###############################################################
#  Generated by:      Cadence Innovus 20.13-s083_1
#  OS:                Linux x86_64(Host ID iron-502-27)
#  Generated on:      Fri Jun 17 14:07:25 2022
#  Design:            user_proj_example
#  Command:           write_lef_abstract -specifyTopLayer 5 -PGPinLayers {5 6} -extractBlockObs -stripePin results/user_proj_example.lef
###############################################################

VERSION 5.8 ;

BUSBITCHARS "[]" ;
DIVIDERCHAR "/" ;

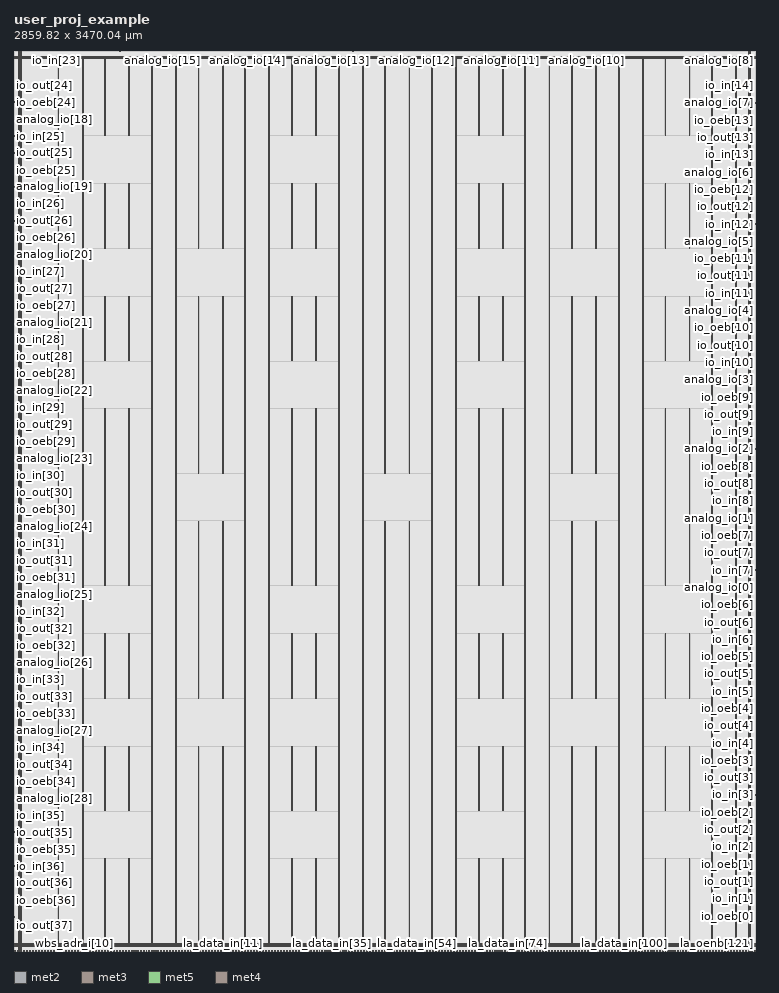
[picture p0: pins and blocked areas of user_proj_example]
MACRO user_proj_example
  CLASS BLOCK ;
  SIZE 2859.820000 BY 3470.040000 ;
  FOREIGN user_proj_example 0.000000 0.000000 ;
  ORIGIN 0 0 ;
  SYMMETRY X Y R90 ;
  PIN wb_clk_i
    DIRECTION INPUT ;
    USE SIGNAL ;
    ANTENNAPARTIALMETALAREA 4.1174 LAYER met2  ;
    ANTENNAPARTIALMETALSIDEAREA 20.426 LAYER met2  ;
    ANTENNAPARTIALCUTAREA 0.04 LAYER via2  ;
    ANTENNAPARTIALMETALAREA 8.6748 LAYER met3  ;
    ANTENNAPARTIALMETALSIDEAREA 46.736 LAYER met3  ;
    ANTENNAMODEL OXIDE1 ;
    ANTENNAGATEAREA 0.576 LAYER met3  ;
    ANTENNAMAXAREACAR 16.2276 LAYER met3  ;
    ANTENNAMAXSIDEAREACAR 83.9896 LAYER met3  ;
    ANTENNAMAXCUTCAR 0.158681 LAYER via3  ;
    PORT
      LAYER met2 ;
        RECT 0.620000 0.000000 0.760000 0.485000 ;
    END
  END wb_clk_i
  PIN wb_rst_i
    DIRECTION INPUT ;
    USE SIGNAL ;
    ANTENNAPARTIALMETALAREA 5.373 LAYER met2  ;
    ANTENNAPARTIALMETALSIDEAREA 26.691 LAYER met2  ;
    ANTENNAPARTIALCUTAREA 0.04 LAYER via2  ;
    ANTENNAPARTIALMETALAREA 4.1208 LAYER met3  ;
    ANTENNAPARTIALMETALSIDEAREA 22.448 LAYER met3  ;
    ANTENNAMODEL OXIDE1 ;
    ANTENNAGATEAREA 4.411 LAYER met3  ;
    ANTENNAMAXAREACAR 28.0961 LAYER met3  ;
    ANTENNAMAXSIDEAREACAR 138.749 LAYER met3  ;
    ANTENNAMAXCUTCAR 0.307654 LAYER via3  ;
    PORT
      LAYER met2 ;
        RECT 6.140000 0.000000 6.280000 0.485000 ;
    END
  END wb_rst_i
  PIN wbs_stb_i
    DIRECTION INPUT ;
    USE SIGNAL ;
    ANTENNAPARTIALMETALAREA 4.0627 LAYER met2  ;
    ANTENNAPARTIALMETALSIDEAREA 20.2055 LAYER met2  ;
    ANTENNAMODEL OXIDE1 ;
    ANTENNAGATEAREA 0.126 LAYER met2  ;
    ANTENNAMAXAREACAR 44.8623 LAYER met2  ;
    ANTENNAMAXSIDEAREACAR 217.206 LAYER met2  ;
    ANTENNAMAXCUTCAR 0.407937 LAYER via2  ;
    PORT
      LAYER met2 ;
        RECT 23.620000 0.000000 23.760000 0.485000 ;
    END
  END wbs_stb_i
  PIN wbs_cyc_i
    DIRECTION INPUT ;
    USE SIGNAL ;
    ANTENNAPARTIALMETALAREA 4.2055 LAYER met2  ;
    ANTENNAPARTIALMETALSIDEAREA 20.9195 LAYER met2  ;
    ANTENNAMODEL OXIDE1 ;
    ANTENNAGATEAREA 0.126 LAYER met2  ;
    ANTENNAMAXAREACAR 52.6694 LAYER met2  ;
    ANTENNAMAXSIDEAREACAR 253.103 LAYER met2  ;
    ANTENNAMAXCUTCAR 0.407937 LAYER via2  ;
    PORT
      LAYER met2 ;
        RECT 17.640000 0.000000 17.780000 0.485000 ;
    END
  END wbs_cyc_i
  PIN wbs_we_i
    DIRECTION INPUT ;
    USE SIGNAL ;
    ANTENNAPARTIALMETALAREA 5.0655 LAYER met2  ;
    ANTENNAPARTIALMETALSIDEAREA 24.9935 LAYER met2  ;
    ANTENNAMODEL OXIDE1 ;
    ANTENNAGATEAREA 0.3735 LAYER met2  ;
    ANTENNAMAXAREACAR 17.5253 LAYER met2  ;
    ANTENNAMAXSIDEAREACAR 78.1749 LAYER met2  ;
    ANTENNAMAXCUTCAR 0.407937 LAYER via2  ;
    PORT
      LAYER met2 ;
        RECT 29.600000 0.000000 29.740000 0.485000 ;
    END
  END wbs_we_i
  PIN wbs_sel_i[3]
    DIRECTION INPUT ;
    USE SIGNAL ;
    PORT
      LAYER met2 ;
        RECT 122.060000 0.000000 122.200000 0.485000 ;
    END
  END wbs_sel_i[3]
  PIN wbs_sel_i[2]
    DIRECTION INPUT ;
    USE SIGNAL ;
    PORT
      LAYER met2 ;
        RECT 99.060000 0.000000 99.200000 0.485000 ;
    END
  END wbs_sel_i[2]
  PIN wbs_sel_i[1]
    DIRECTION INPUT ;
    USE SIGNAL ;
    PORT
      LAYER met2 ;
        RECT 75.600000 0.000000 75.740000 0.485000 ;
    END
  END wbs_sel_i[1]
  PIN wbs_sel_i[0]
    DIRECTION INPUT ;
    USE SIGNAL ;
    PORT
      LAYER met2 ;
        RECT 52.600000 0.000000 52.740000 0.485000 ;
    END
  END wbs_sel_i[0]
  PIN wbs_dat_i[31]
    DIRECTION INPUT ;
    USE SIGNAL ;
    PORT
      LAYER met2 ;
        RECT 603.680000 0.000000 603.820000 0.485000 ;
    END
  END wbs_dat_i[31]
  PIN wbs_dat_i[30]
    DIRECTION INPUT ;
    USE SIGNAL ;
    PORT
      LAYER met2 ;
        RECT 586.200000 0.000000 586.340000 0.485000 ;
    END
  END wbs_dat_i[30]
  PIN wbs_dat_i[29]
    DIRECTION INPUT ;
    USE SIGNAL ;
    PORT
      LAYER met2 ;
        RECT 568.720000 0.000000 568.860000 0.485000 ;
    END
  END wbs_dat_i[29]
  PIN wbs_dat_i[28]
    DIRECTION INPUT ;
    USE SIGNAL ;
    PORT
      LAYER met2 ;
        RECT 551.240000 0.000000 551.380000 0.485000 ;
    END
  END wbs_dat_i[28]
  PIN wbs_dat_i[27]
    DIRECTION INPUT ;
    USE SIGNAL ;
    PORT
      LAYER met2 ;
        RECT 533.760000 0.000000 533.900000 0.485000 ;
    END
  END wbs_dat_i[27]
  PIN wbs_dat_i[26]
    DIRECTION INPUT ;
    USE SIGNAL ;
    PORT
      LAYER met2 ;
        RECT 516.740000 0.000000 516.880000 0.485000 ;
    END
  END wbs_dat_i[26]
  PIN wbs_dat_i[25]
    DIRECTION INPUT ;
    USE SIGNAL ;
    PORT
      LAYER met2 ;
        RECT 499.260000 0.000000 499.400000 0.485000 ;
    END
  END wbs_dat_i[25]
  PIN wbs_dat_i[24]
    DIRECTION INPUT ;
    USE SIGNAL ;
    PORT
      LAYER met2 ;
        RECT 481.780000 0.000000 481.920000 0.485000 ;
    END
  END wbs_dat_i[24]
  PIN wbs_dat_i[23]
    DIRECTION INPUT ;
    USE SIGNAL ;
    ANTENNAPARTIALMETALAREA 6.0883 LAYER met2  ;
    ANTENNAPARTIALMETALSIDEAREA 30.2155 LAYER met2  ;
    ANTENNAMODEL OXIDE1 ;
    ANTENNAGATEAREA 0.126 LAYER met2  ;
    ANTENNAMAXAREACAR 50.3571 LAYER met2  ;
    ANTENNAMAXSIDEAREACAR 245.865 LAYER met2  ;
    ANTENNAMAXCUTCAR 0.407937 LAYER via2  ;
    PORT
      LAYER met2 ;
        RECT 464.300000 0.000000 464.440000 0.485000 ;
    END
  END wbs_dat_i[23]
  PIN wbs_dat_i[22]
    DIRECTION INPUT ;
    USE SIGNAL ;
    ANTENNAPARTIALMETALAREA 6.3475 LAYER met2  ;
    ANTENNAPARTIALMETALSIDEAREA 31.6295 LAYER met2  ;
    ANTENNAMODEL OXIDE1 ;
    ANTENNAGATEAREA 0.126 LAYER met2  ;
    ANTENNAMAXAREACAR 67.3623 LAYER met2  ;
    ANTENNAMAXSIDEAREACAR 327.397 LAYER met2  ;
    ANTENNAMAXCUTCAR 0.407937 LAYER via2  ;
    PORT
      LAYER met2 ;
        RECT 446.820000 0.000000 446.960000 0.485000 ;
    END
  END wbs_dat_i[22]
  PIN wbs_dat_i[21]
    DIRECTION INPUT ;
    USE SIGNAL ;
    ANTENNAPARTIALMETALAREA 5.5859 LAYER met2  ;
    ANTENNAPARTIALMETALSIDEAREA 27.8215 LAYER met2  ;
    ANTENNAMODEL OXIDE1 ;
    ANTENNAGATEAREA 0.126 LAYER met2  ;
    ANTENNAMAXAREACAR 59.7845 LAYER met2  ;
    ANTENNAMAXSIDEAREACAR 289.508 LAYER met2  ;
    ANTENNAMAXCUTCAR 0.407937 LAYER via2  ;
    PORT
      LAYER met2 ;
        RECT 429.800000 0.000000 429.940000 0.485000 ;
    END
  END wbs_dat_i[21]
  PIN wbs_dat_i[20]
    DIRECTION INPUT ;
    USE SIGNAL ;
    ANTENNAPARTIALMETALAREA 6.2383 LAYER met2  ;
    ANTENNAPARTIALMETALSIDEAREA 31.0835 LAYER met2  ;
    ANTENNAMODEL OXIDE1 ;
    ANTENNAGATEAREA 0.126 LAYER met2  ;
    ANTENNAMAXAREACAR 51.5476 LAYER met2  ;
    ANTENNAMAXSIDEAREACAR 252.754 LAYER met2  ;
    ANTENNAMAXCUTCAR 0.407937 LAYER via2  ;
    PORT
      LAYER met2 ;
        RECT 412.320000 0.000000 412.460000 0.485000 ;
    END
  END wbs_dat_i[20]
  PIN wbs_dat_i[19]
    DIRECTION INPUT ;
    USE SIGNAL ;
    ANTENNAPARTIALMETALAREA 5.5859 LAYER met2  ;
    ANTENNAPARTIALMETALSIDEAREA 27.8215 LAYER met2  ;
    ANTENNAMODEL OXIDE1 ;
    ANTENNAGATEAREA 0.126 LAYER met2  ;
    ANTENNAMAXAREACAR 48.8067 LAYER met2  ;
    ANTENNAMAXSIDEAREACAR 234.619 LAYER met2  ;
    ANTENNAMAXCUTCAR 0.407937 LAYER via2  ;
    PORT
      LAYER met2 ;
        RECT 394.840000 0.000000 394.980000 0.485000 ;
    END
  END wbs_dat_i[19]
  PIN wbs_dat_i[18]
    DIRECTION INPUT ;
    USE SIGNAL ;
    ANTENNAPARTIALMETALAREA 6.1095 LAYER met2  ;
    ANTENNAPARTIALMETALSIDEAREA 30.4395 LAYER met2  ;
    ANTENNAMODEL OXIDE1 ;
    ANTENNAGATEAREA 0.126 LAYER met2  ;
    ANTENNAMAXAREACAR 53.477 LAYER met2  ;
    ANTENNAMAXSIDEAREACAR 261.865 LAYER met2  ;
    ANTENNAMAXCUTCAR 0.407937 LAYER via2  ;
    PORT
      LAYER met2 ;
        RECT 377.360000 0.000000 377.500000 0.485000 ;
    END
  END wbs_dat_i[18]
  PIN wbs_dat_i[17]
    DIRECTION INPUT ;
    USE SIGNAL ;
    ANTENNAPARTIALMETALAREA 5.3339 LAYER met2  ;
    ANTENNAPARTIALMETALSIDEAREA 26.5615 LAYER met2  ;
    ANTENNAMODEL OXIDE1 ;
    ANTENNAGATEAREA 0.126 LAYER met2  ;
    ANTENNAMAXAREACAR 52.8353 LAYER met2  ;
    ANTENNAMAXSIDEAREACAR 251.254 LAYER met2  ;
    ANTENNAMAXCUTCAR 0.407937 LAYER via2  ;
    PORT
      LAYER met2 ;
        RECT 359.880000 0.000000 360.020000 0.485000 ;
    END
  END wbs_dat_i[17]
  PIN wbs_dat_i[16]
    DIRECTION INPUT ;
    USE SIGNAL ;
    ANTENNAPARTIALMETALAREA 5.4599 LAYER met2  ;
    ANTENNAPARTIALMETALSIDEAREA 27.1915 LAYER met2  ;
    ANTENNAMODEL OXIDE1 ;
    ANTENNAGATEAREA 0.126 LAYER met2  ;
    ANTENNAMAXAREACAR 45.3698 LAYER met2  ;
    ANTENNAMAXSIDEAREACAR 221.865 LAYER met2  ;
    ANTENNAMAXCUTCAR 0.407937 LAYER via2  ;
    PORT
      LAYER met2 ;
        RECT 342.400000 0.000000 342.540000 0.485000 ;
    END
  END wbs_dat_i[16]
  PIN wbs_dat_i[15]
    DIRECTION INPUT ;
    USE SIGNAL ;
    ANTENNAPARTIALMETALAREA 6.4215 LAYER met2  ;
    ANTENNAPARTIALMETALSIDEAREA 31.8815 LAYER met2  ;
    ANTENNAMODEL OXIDE1 ;
    ANTENNAGATEAREA 0.2475 LAYER met2  ;
    ANTENNAMAXAREACAR 28.7937 LAYER met2  ;
    ANTENNAMAXSIDEAREACAR 138.541 LAYER met2  ;
    ANTENNAMAXCUTCAR 0.207677 LAYER via2  ;
    PORT
      LAYER met2 ;
        RECT 325.380000 0.000000 325.520000 0.485000 ;
    END
  END wbs_dat_i[15]
  PIN wbs_dat_i[14]
    DIRECTION INPUT ;
    USE SIGNAL ;
    ANTENNAPARTIALMETALAREA 4.5651 LAYER met2  ;
    ANTENNAPARTIALMETALSIDEAREA 22.5995 LAYER met2  ;
    ANTENNAMODEL OXIDE1 ;
    ANTENNAGATEAREA 0.2475 LAYER met2  ;
    ANTENNAMAXAREACAR 19.302 LAYER met2  ;
    ANTENNAMAXSIDEAREACAR 94.2182 LAYER met2  ;
    ANTENNAMAXCUTCAR 0.207677 LAYER via2  ;
    PORT
      LAYER met2 ;
        RECT 307.900000 0.000000 308.040000 0.485000 ;
    END
  END wbs_dat_i[14]
  PIN wbs_dat_i[13]
    DIRECTION INPUT ;
    USE SIGNAL ;
    ANTENNAPARTIALMETALAREA 5.7761 LAYER met2  ;
    ANTENNAPARTIALMETALSIDEAREA 28.6545 LAYER met2  ;
    ANTENNAMODEL OXIDE1 ;
    ANTENNAGATEAREA 0.2475 LAYER met2  ;
    ANTENNAMAXAREACAR 24.195 LAYER met2  ;
    ANTENNAMAXSIDEAREACAR 118.683 LAYER met2  ;
    ANTENNAMAXCUTCAR 0.207677 LAYER via2  ;
    PORT
      LAYER met2 ;
        RECT 290.420000 0.000000 290.560000 0.485000 ;
    END
  END wbs_dat_i[13]
  PIN wbs_dat_i[12]
    DIRECTION INPUT ;
    USE SIGNAL ;
    ANTENNAPARTIALMETALAREA 5.5507 LAYER met2  ;
    ANTENNAPARTIALMETALSIDEAREA 27.5275 LAYER met2  ;
    ANTENNAMODEL OXIDE1 ;
    ANTENNAGATEAREA 0.2475 LAYER met2  ;
    ANTENNAMAXAREACAR 24.0063 LAYER met2  ;
    ANTENNAMAXSIDEAREACAR 117.467 LAYER met2  ;
    ANTENNAMAXCUTCAR 0.207677 LAYER via2  ;
    PORT
      LAYER met2 ;
        RECT 272.940000 0.000000 273.080000 0.485000 ;
    END
  END wbs_dat_i[12]
  PIN wbs_dat_i[11]
    DIRECTION INPUT ;
    USE SIGNAL ;
    ANTENNAPARTIALMETALAREA 5.1699 LAYER met2  ;
    ANTENNAPARTIALMETALSIDEAREA 25.6235 LAYER met2  ;
    ANTENNAMODEL OXIDE1 ;
    ANTENNAGATEAREA 0.2475 LAYER met2  ;
    ANTENNAMAXAREACAR 21.7457 LAYER met2  ;
    ANTENNAMAXSIDEAREACAR 106.436 LAYER met2  ;
    ANTENNAMAXCUTCAR 0.207677 LAYER via2  ;
    PORT
      LAYER met2 ;
        RECT 255.460000 0.000000 255.600000 0.485000 ;
    END
  END wbs_dat_i[11]
  PIN wbs_dat_i[10]
    DIRECTION INPUT ;
    USE SIGNAL ;
    ANTENNAPARTIALMETALAREA 4.8507 LAYER met2  ;
    ANTENNAPARTIALMETALSIDEAREA 24.0275 LAYER met2  ;
    ANTENNAMODEL OXIDE1 ;
    ANTENNAGATEAREA 0.2475 LAYER met2  ;
    ANTENNAMAXAREACAR 22.479 LAYER met2  ;
    ANTENNAMAXSIDEAREACAR 109.83 LAYER met2  ;
    ANTENNAMAXCUTCAR 0.207677 LAYER via2  ;
    PORT
      LAYER met2 ;
        RECT 237.980000 0.000000 238.120000 0.485000 ;
    END
  END wbs_dat_i[10]
  PIN wbs_dat_i[9]
    DIRECTION INPUT ;
    USE SIGNAL ;
    ANTENNAPARTIALMETALAREA 6.9356 LAYER met2  ;
    ANTENNAPARTIALMETALSIDEAREA 34.517 LAYER met2  ;
    ANTENNAPARTIALCUTAREA 0.04 LAYER via2  ;
    ANTENNAPARTIALMETALAREA 62.659 LAYER met3  ;
    ANTENNAPARTIALMETALSIDEAREA 334.648 LAYER met3  ;
    ANTENNAPARTIALCUTAREA 0.04 LAYER via3  ;
    ANTENNAPARTIALMETALAREA 0.6516 LAYER met4  ;
    ANTENNAPARTIALMETALSIDEAREA 4.416 LAYER met4  ;
    ANTENNAMODEL OXIDE1 ;
    ANTENNAGATEAREA 0.2475 LAYER met4  ;
    ANTENNAMAXAREACAR 10.4438 LAYER met4  ;
    ANTENNAMAXSIDEAREACAR 58.4606 LAYER met4  ;
    ANTENNAMAXCUTCAR 0.530909 LAYER via4  ;
    PORT
      LAYER met2 ;
        RECT 220.960000 0.000000 221.100000 0.485000 ;
    END
  END wbs_dat_i[9]
  PIN wbs_dat_i[8]
    DIRECTION INPUT ;
    USE SIGNAL ;
    ANTENNAPARTIALMETALAREA 6.5503 LAYER met2  ;
    ANTENNAPARTIALMETALSIDEAREA 32.5255 LAYER met2  ;
    ANTENNAMODEL OXIDE1 ;
    ANTENNAGATEAREA 0.2475 LAYER met2  ;
    ANTENNAMAXAREACAR 39.3582 LAYER met2  ;
    ANTENNAMAXSIDEAREACAR 194.226 LAYER met2  ;
    ANTENNAMAXCUTCAR 0.207677 LAYER via2  ;
    PORT
      LAYER met2 ;
        RECT 203.480000 0.000000 203.620000 0.485000 ;
    END
  END wbs_dat_i[8]
  PIN wbs_dat_i[7]
    DIRECTION INPUT ;
    USE SIGNAL ;
    ANTENNAPARTIALMETALAREA 4.9935 LAYER met2  ;
    ANTENNAPARTIALMETALSIDEAREA 24.7415 LAYER met2  ;
    ANTENNAMODEL OXIDE1 ;
    ANTENNAGATEAREA 0.2475 LAYER met2  ;
    ANTENNAMAXAREACAR 21.0329 LAYER met2  ;
    ANTENNAMAXSIDEAREACAR 102.873 LAYER met2  ;
    ANTENNAMAXCUTCAR 0.207677 LAYER via2  ;
    PORT
      LAYER met2 ;
        RECT 186.000000 0.000000 186.140000 0.485000 ;
    END
  END wbs_dat_i[7]
  PIN wbs_dat_i[6]
    DIRECTION INPUT ;
    USE SIGNAL ;
    ANTENNAPARTIALMETALAREA 7.2951 LAYER met2  ;
    ANTENNAPARTIALMETALSIDEAREA 36.2495 LAYER met2  ;
    ANTENNAMODEL OXIDE1 ;
    ANTENNAGATEAREA 0.2475 LAYER met2  ;
    ANTENNAMAXAREACAR 30.7432 LAYER met2  ;
    ANTENNAMAXSIDEAREACAR 151.152 LAYER met2  ;
    ANTENNAMAXCUTCAR 0.207677 LAYER via2  ;
    PORT
      LAYER met2 ;
        RECT 168.520000 0.000000 168.660000 0.485000 ;
    END
  END wbs_dat_i[6]
  PIN wbs_dat_i[5]
    DIRECTION INPUT ;
    USE SIGNAL ;
    ANTENNAPARTIALMETALAREA 6.0883 LAYER met2  ;
    ANTENNAPARTIALMETALSIDEAREA 30.2155 LAYER met2  ;
    ANTENNAMODEL OXIDE1 ;
    ANTENNAGATEAREA 0.2475 LAYER met2  ;
    ANTENNAMAXAREACAR 33.5566 LAYER met2  ;
    ANTENNAMAXSIDEAREACAR 162.356 LAYER met2  ;
    ANTENNAMAXCUTCAR 0.207677 LAYER via2  ;
    PORT
      LAYER met2 ;
        RECT 151.040000 0.000000 151.180000 0.485000 ;
    END
  END wbs_dat_i[5]
  PIN wbs_dat_i[4]
    DIRECTION INPUT ;
    USE SIGNAL ;
    ANTENNAPARTIALMETALAREA 5.8363 LAYER met2  ;
    ANTENNAPARTIALMETALSIDEAREA 28.9555 LAYER met2  ;
    ANTENNAMODEL OXIDE1 ;
    ANTENNAGATEAREA 0.2475 LAYER met2  ;
    ANTENNAMAXAREACAR 24.9 LAYER met2  ;
    ANTENNAMAXSIDEAREACAR 121.935 LAYER met2  ;
    ANTENNAMAXCUTCAR 0.207677 LAYER via2  ;
    PORT
      LAYER met2 ;
        RECT 133.560000 0.000000 133.700000 0.485000 ;
    END
  END wbs_dat_i[4]
  PIN wbs_dat_i[3]
    DIRECTION INPUT ;
    USE SIGNAL ;
    ANTENNAPARTIALMETALAREA 4.2179 LAYER met2  ;
    ANTENNAPARTIALMETALSIDEAREA 20.8635 LAYER met2  ;
    ANTENNAMODEL OXIDE1 ;
    ANTENNAGATEAREA 0.2475 LAYER met2  ;
    ANTENNAMAXAREACAR 19.8903 LAYER met2  ;
    ANTENNAMAXSIDEAREACAR 94.0242 LAYER met2  ;
    ANTENNAMAXCUTCAR 0.207677 LAYER via2  ;
    PORT
      LAYER met2 ;
        RECT 110.560000 0.000000 110.700000 0.485000 ;
    END
  END wbs_dat_i[3]
  PIN wbs_dat_i[2]
    DIRECTION INPUT ;
    USE SIGNAL ;
    ANTENNAPARTIALMETALAREA 5.6123 LAYER met2  ;
    ANTENNAPARTIALMETALSIDEAREA 27.8355 LAYER met2  ;
    ANTENNAMODEL OXIDE1 ;
    ANTENNAGATEAREA 0.2475 LAYER met2  ;
    ANTENNAMAXAREACAR 23.944 LAYER met2  ;
    ANTENNAMAXSIDEAREACAR 117.156 LAYER met2  ;
    ANTENNAMAXCUTCAR 0.207677 LAYER via2  ;
    PORT
      LAYER met2 ;
        RECT 87.560000 0.000000 87.700000 0.485000 ;
    END
  END wbs_dat_i[2]
  PIN wbs_dat_i[1]
    DIRECTION INPUT ;
    USE SIGNAL ;
    ANTENNAPARTIALMETALAREA 6.3935 LAYER met2  ;
    ANTENNAPARTIALMETALSIDEAREA 31.7415 LAYER met2  ;
    ANTENNAMODEL OXIDE1 ;
    ANTENNAGATEAREA 0.2475 LAYER met2  ;
    ANTENNAMAXAREACAR 27.4382 LAYER met2  ;
    ANTENNAMAXSIDEAREACAR 132.036 LAYER met2  ;
    ANTENNAMAXCUTCAR 0.207677 LAYER via2  ;
    PORT
      LAYER met2 ;
        RECT 64.100000 0.000000 64.240000 0.485000 ;
    END
  END wbs_dat_i[1]
  PIN wbs_dat_i[0]
    DIRECTION INPUT ;
    USE SIGNAL ;
    ANTENNAPARTIALMETALAREA 6.1219 LAYER met2  ;
    ANTENNAPARTIALMETALSIDEAREA 30.3835 LAYER met2  ;
    ANTENNAMODEL OXIDE1 ;
    ANTENNAGATEAREA 0.2475 LAYER met2  ;
    ANTENNAMAXAREACAR 44.4584 LAYER met2  ;
    ANTENNAMAXSIDEAREACAR 215.972 LAYER met2  ;
    ANTENNAMAXCUTCAR 0.207677 LAYER via2  ;
    PORT
      LAYER met2 ;
        RECT 41.100000 0.000000 41.240000 0.485000 ;
    END
  END wbs_dat_i[0]
  PIN wbs_adr_i[31]
    DIRECTION INPUT ;
    USE SIGNAL ;
    ANTENNAPARTIALMETALAREA 5.8975 LAYER met2  ;
    ANTENNAPARTIALMETALSIDEAREA 29.0255 LAYER met2  ;
    ANTENNAMODEL OXIDE1 ;
    ANTENNAGATEAREA 0.3735 LAYER met2  ;
    ANTENNAMAXAREACAR 23.1648 LAYER met2  ;
    ANTENNAMAXSIDEAREACAR 105.121 LAYER met2  ;
    ANTENNAMAXCUTCAR 0.586508 LAYER via2  ;
    PORT
      LAYER met2 ;
        RECT 597.700000 0.000000 597.840000 0.485000 ;
    END
  END wbs_adr_i[31]
  PIN wbs_adr_i[30]
    DIRECTION INPUT ;
    USE SIGNAL ;
    ANTENNAPARTIALMETALAREA 4.7555 LAYER met2  ;
    ANTENNAPARTIALMETALSIDEAREA 23.5515 LAYER met2  ;
    ANTENNAMODEL OXIDE1 ;
    ANTENNAGATEAREA 0.3735 LAYER met2  ;
    ANTENNAMAXAREACAR 48.7097 LAYER met2  ;
    ANTENNAMAXSIDEAREACAR 237.777 LAYER met2  ;
    ANTENNAMAXCUTCAR 0.407937 LAYER via2  ;
    PORT
      LAYER met2 ;
        RECT 580.220000 0.000000 580.360000 0.485000 ;
    END
  END wbs_adr_i[30]
  PIN wbs_adr_i[29]
    DIRECTION INPUT ;
    USE SIGNAL ;
    ANTENNAPARTIALMETALAREA 5.1363 LAYER met2  ;
    ANTENNAPARTIALMETALSIDEAREA 25.4555 LAYER met2  ;
    ANTENNAMODEL OXIDE1 ;
    ANTENNAGATEAREA 0.3735 LAYER met2  ;
    ANTENNAMAXAREACAR 62.924 LAYER met2  ;
    ANTENNAMAXSIDEAREACAR 310.146 LAYER met2  ;
    ANTENNAMAXCUTCAR 0.586508 LAYER via2  ;
    PORT
      LAYER met2 ;
        RECT 563.200000 0.000000 563.340000 0.485000 ;
    END
  END wbs_adr_i[29]
  PIN wbs_adr_i[28]
    DIRECTION INPUT ;
    USE SIGNAL ;
    ANTENNAPARTIALMETALAREA 4.1174 LAYER met2  ;
    ANTENNAPARTIALMETALSIDEAREA 20.426 LAYER met2  ;
    ANTENNAPARTIALCUTAREA 0.04 LAYER via2  ;
    ANTENNAPARTIALMETALAREA 7.2948 LAYER met3  ;
    ANTENNAPARTIALMETALSIDEAREA 39.376 LAYER met3  ;
    ANTENNAMODEL OXIDE1 ;
    ANTENNAGATEAREA 0.3735 LAYER met3  ;
    ANTENNAMAXAREACAR 26.735 LAYER met3  ;
    ANTENNAMAXSIDEAREACAR 134.756 LAYER met3  ;
    ANTENNAMAXCUTCAR 0.396701 LAYER via3  ;
    PORT
      LAYER met2 ;
        RECT 545.720000 0.000000 545.860000 0.485000 ;
    END
  END wbs_adr_i[28]
  PIN wbs_adr_i[27]
    DIRECTION INPUT ;
    USE SIGNAL ;
    ANTENNAPARTIALMETALAREA 4.7463 LAYER met2  ;
    ANTENNAPARTIALMETALSIDEAREA 23.3975 LAYER met2  ;
    ANTENNAMODEL OXIDE1 ;
    ANTENNAGATEAREA 0.3735 LAYER met2  ;
    ANTENNAMAXAREACAR 14.8313 LAYER met2  ;
    ANTENNAMAXSIDEAREACAR 70.4358 LAYER met2  ;
    ANTENNAMAXCUTCAR 0.407937 LAYER via2  ;
    PORT
      LAYER met2 ;
        RECT 528.240000 0.000000 528.380000 0.485000 ;
    END
  END wbs_adr_i[27]
  PIN wbs_adr_i[26]
    DIRECTION INPUT ;
    USE SIGNAL ;
    ANTENNAPARTIALMETALAREA 4.8039 LAYER met2  ;
    ANTENNAPARTIALMETALSIDEAREA 23.8035 LAYER met2  ;
    ANTENNAMODEL OXIDE1 ;
    ANTENNAGATEAREA 0.3735 LAYER met2  ;
    ANTENNAMAXAREACAR 16.417 LAYER met2  ;
    ANTENNAMAXSIDEAREACAR 71.6793 LAYER met2  ;
    ANTENNAMAXCUTCAR 0.407937 LAYER via2  ;
    PORT
      LAYER met2 ;
        RECT 510.760000 0.000000 510.900000 0.485000 ;
    END
  END wbs_adr_i[26]
  PIN wbs_adr_i[25]
    DIRECTION INPUT ;
    USE SIGNAL ;
    ANTENNAPARTIALMETALAREA 4.6603 LAYER met2  ;
    ANTENNAPARTIALMETALSIDEAREA 23.0755 LAYER met2  ;
    ANTENNAMODEL OXIDE1 ;
    ANTENNAGATEAREA 0.3735 LAYER met2  ;
    ANTENNAMAXAREACAR 23.4076 LAYER met2  ;
    ANTENNAMAXSIDEAREACAR 111.267 LAYER met2  ;
    ANTENNAMAXCUTCAR 0.407937 LAYER via2  ;
    PORT
      LAYER met2 ;
        RECT 493.280000 0.000000 493.420000 0.485000 ;
    END
  END wbs_adr_i[25]
  PIN wbs_adr_i[24]
    DIRECTION INPUT ;
    USE SIGNAL ;
    ANTENNAPARTIALMETALAREA 4.5175 LAYER met2  ;
    ANTENNAPARTIALMETALSIDEAREA 22.3615 LAYER met2  ;
    ANTENNAMODEL OXIDE1 ;
    ANTENNAGATEAREA 0.3735 LAYER met2  ;
    ANTENNAMAXAREACAR 27.0437 LAYER met2  ;
    ANTENNAMAXSIDEAREACAR 128.577 LAYER met2  ;
    ANTENNAMAXCUTCAR 0.407937 LAYER via2  ;
    PORT
      LAYER met2 ;
        RECT 475.800000 0.000000 475.940000 0.485000 ;
    END
  END wbs_adr_i[24]
  PIN wbs_adr_i[23]
    DIRECTION INPUT ;
    USE SIGNAL ;
    ANTENNAPARTIALMETALAREA 4.3543 LAYER met2  ;
    ANTENNAPARTIALMETALSIDEAREA 21.4235 LAYER met2  ;
    ANTENNAMODEL OXIDE1 ;
    ANTENNAGATEAREA 0.2475 LAYER met2  ;
    ANTENNAMAXAREACAR 18.7345 LAYER met2  ;
    ANTENNAMAXSIDEAREACAR 89.7131 LAYER met2  ;
    ANTENNAPARTIALCUTAREA 0.04 LAYER via2  ;
    ANTENNAMAXCUTCAR 0.369293 LAYER via2  ;
    ANTENNAPARTIALMETALAREA 2.6028 LAYER met3  ;
    ANTENNAPARTIALMETALSIDEAREA 14.352 LAYER met3  ;
    ANTENNAGATEAREA 0.3735 LAYER met3  ;
    ANTENNAMAXAREACAR 25.7032 LAYER met3  ;
    ANTENNAMAXSIDEAREACAR 128.139 LAYER met3  ;
    ANTENNAMAXCUTCAR 0.725397 LAYER via3  ;
    PORT
      LAYER met2 ;
        RECT 458.780000 0.000000 458.920000 0.485000 ;
    END
  END wbs_adr_i[23]
  PIN wbs_adr_i[22]
    DIRECTION INPUT ;
    USE SIGNAL ;
    ANTENNAPARTIALMETALAREA 4.7203 LAYER met2  ;
    ANTENNAPARTIALMETALSIDEAREA 23.2575 LAYER met2  ;
    ANTENNAMODEL OXIDE1 ;
    ANTENNAGATEAREA 0.3735 LAYER met2  ;
    ANTENNAMAXAREACAR 18.8924 LAYER met2  ;
    ANTENNAMAXSIDEAREACAR 91.3883 LAYER met2  ;
    ANTENNAMAXCUTCAR 0.407937 LAYER via2  ;
    PORT
      LAYER met2 ;
        RECT 441.300000 0.000000 441.440000 0.485000 ;
    END
  END wbs_adr_i[22]
  PIN wbs_adr_i[21]
    DIRECTION INPUT ;
    USE SIGNAL ;
    ANTENNAPARTIALMETALAREA 4.8828 LAYER met2  ;
    ANTENNAPARTIALMETALSIDEAREA 24.08 LAYER met2  ;
    ANTENNAMODEL OXIDE1 ;
    ANTENNAGATEAREA 0.3735 LAYER met2  ;
    ANTENNAMAXAREACAR 20.0794 LAYER met2  ;
    ANTENNAMAXSIDEAREACAR 96.4911 LAYER met2  ;
    ANTENNAMAXCUTCAR 0.407937 LAYER via2  ;
    PORT
      LAYER met2 ;
        RECT 423.820000 0.000000 423.960000 0.485000 ;
    END
  END wbs_adr_i[21]
  PIN wbs_adr_i[20]
    DIRECTION INPUT ;
    USE SIGNAL ;
    ANTENNAPARTIALMETALAREA 5.0319 LAYER met2  ;
    ANTENNAPARTIALMETALSIDEAREA 24.8255 LAYER met2  ;
    ANTENNAMODEL OXIDE1 ;
    ANTENNAGATEAREA 0.3735 LAYER met2  ;
    ANTENNAMAXAREACAR 19.5898 LAYER met2  ;
    ANTENNAMAXSIDEAREACAR 94.0426 LAYER met2  ;
    ANTENNAMAXCUTCAR 0.407937 LAYER via2  ;
    PORT
      LAYER met2 ;
        RECT 406.340000 0.000000 406.480000 0.485000 ;
    END
  END wbs_adr_i[20]
  PIN wbs_adr_i[19]
    DIRECTION INPUT ;
    USE SIGNAL ;
    ANTENNAPARTIALMETALAREA 5.5107 LAYER met2  ;
    ANTENNAPARTIALMETALSIDEAREA 27.2195 LAYER met2  ;
    ANTENNAMODEL OXIDE1 ;
    ANTENNAGATEAREA 0.3735 LAYER met2  ;
    ANTENNAMAXAREACAR 17.2939 LAYER met2  ;
    ANTENNAMAXSIDEAREACAR 82.5633 LAYER met2  ;
    ANTENNAMAXCUTCAR 0.407937 LAYER via2  ;
    PORT
      LAYER met2 ;
        RECT 388.860000 0.000000 389.000000 0.485000 ;
    END
  END wbs_adr_i[19]
  PIN wbs_adr_i[18]
    DIRECTION INPUT ;
    USE SIGNAL ;
    ANTENNAPARTIALMETALAREA 5.5171 LAYER met2  ;
    ANTENNAPARTIALMETALSIDEAREA 27.3595 LAYER met2  ;
    ANTENNAMODEL OXIDE1 ;
    ANTENNAGATEAREA 0.3735 LAYER met2  ;
    ANTENNAMAXAREACAR 51.2194 LAYER met2  ;
    ANTENNAMAXSIDEAREACAR 246.883 LAYER met2  ;
    ANTENNAMAXCUTCAR 0.407937 LAYER via2  ;
    PORT
      LAYER met2 ;
        RECT 371.380000 0.000000 371.520000 0.485000 ;
    END
  END wbs_adr_i[18]
  PIN wbs_adr_i[17]
    DIRECTION INPUT ;
    USE SIGNAL ;
    ANTENNAPARTIALMETALAREA 5.2173 LAYER met2  ;
    ANTENNAPARTIALMETALSIDEAREA 25.7425 LAYER met2  ;
    ANTENNAMODEL OXIDE1 ;
    ANTENNAGATEAREA 0.3735 LAYER met2  ;
    ANTENNAMAXAREACAR 19.0469 LAYER met2  ;
    ANTENNAMAXSIDEAREACAR 88.3123 LAYER met2  ;
    ANTENNAMAXCUTCAR 0.407937 LAYER via2  ;
    PORT
      LAYER met2 ;
        RECT 354.360000 0.000000 354.500000 0.485000 ;
    END
  END wbs_adr_i[17]
  PIN wbs_adr_i[16]
    DIRECTION INPUT ;
    USE SIGNAL ;
    ANTENNAPARTIALMETALAREA 5.8411 LAYER met2  ;
    ANTENNAPARTIALMETALSIDEAREA 28.8715 LAYER met2  ;
    ANTENNAMODEL OXIDE1 ;
    ANTENNAGATEAREA 0.3735 LAYER met2  ;
    ANTENNAMAXAREACAR 18.6896 LAYER met2  ;
    ANTENNAMAXSIDEAREACAR 89.5419 LAYER met2  ;
    ANTENNAMAXCUTCAR 0.407937 LAYER via2  ;
    PORT
      LAYER met2 ;
        RECT 336.880000 0.000000 337.020000 0.485000 ;
    END
  END wbs_adr_i[16]
  PIN wbs_adr_i[15]
    DIRECTION INPUT ;
    USE SIGNAL ;
    ANTENNAPARTIALMETALAREA 4.2055 LAYER met2  ;
    ANTENNAPARTIALMETALSIDEAREA 20.9195 LAYER met2  ;
    ANTENNAMODEL OXIDE1 ;
    ANTENNAGATEAREA 0.3735 LAYER met2  ;
    ANTENNAMAXAREACAR 60.9423 LAYER met2  ;
    ANTENNAMAXSIDEAREACAR 296.04 LAYER met2  ;
    ANTENNAMAXCUTCAR 0.289606 LAYER via2  ;
    PORT
      LAYER met2 ;
        RECT 319.400000 0.000000 319.540000 0.485000 ;
    END
  END wbs_adr_i[15]
  PIN wbs_adr_i[14]
    DIRECTION INPUT ;
    USE SIGNAL ;
    ANTENNAPARTIALMETALAREA 5.639 LAYER met2  ;
    ANTENNAPARTIALMETALSIDEAREA 27.916 LAYER met2  ;
    ANTENNAMODEL OXIDE1 ;
    ANTENNAGATEAREA 0.2475 LAYER met2  ;
    ANTENNAMAXAREACAR 86.8206 LAYER met2  ;
    ANTENNAMAXSIDEAREACAR 427.752 LAYER met2  ;
    ANTENNAPARTIALCUTAREA 0.04 LAYER via2  ;
    ANTENNAMAXCUTCAR 0.460202 LAYER via2  ;
    ANTENNAPARTIALMETALAREA 15.2988 LAYER met3  ;
    ANTENNAPARTIALMETALSIDEAREA 82.064 LAYER met3  ;
    ANTENNAGATEAREA 0.3735 LAYER met3  ;
    ANTENNAMAXAREACAR 127.781 LAYER met3  ;
    ANTENNAMAXSIDEAREACAR 647.468 LAYER met3  ;
    ANTENNAMAXCUTCAR 0.725397 LAYER via3  ;
    PORT
      LAYER met2 ;
        RECT 301.920000 0.000000 302.060000 0.485000 ;
    END
  END wbs_adr_i[14]
  PIN wbs_adr_i[13]
    DIRECTION INPUT ;
    USE SIGNAL ;
    ANTENNAPARTIALMETALAREA 6.5247 LAYER met2  ;
    ANTENNAPARTIALMETALSIDEAREA 32.1615 LAYER met2  ;
    ANTENNAMODEL OXIDE1 ;
    ANTENNAGATEAREA 0.3735 LAYER met2  ;
    ANTENNAMAXAREACAR 23.5695 LAYER met2  ;
    ANTENNAMAXSIDEAREACAR 109.755 LAYER met2  ;
    ANTENNAMAXCUTCAR 0.407937 LAYER via2  ;
    PORT
      LAYER met2 ;
        RECT 284.440000 0.000000 284.580000 0.485000 ;
    END
  END wbs_adr_i[13]
  PIN wbs_adr_i[12]
    DIRECTION INPUT ;
    USE SIGNAL ;
    ANTENNAPARTIALMETALAREA 5.3828 LAYER met2  ;
    ANTENNAPARTIALMETALSIDEAREA 26.572 LAYER met2  ;
    ANTENNAMODEL OXIDE1 ;
    ANTENNAGATEAREA 0.2475 LAYER met2  ;
    ANTENNAMAXAREACAR 99.3741 LAYER met2  ;
    ANTENNAMAXSIDEAREACAR 489.099 LAYER met2  ;
    ANTENNAPARTIALCUTAREA 0.04 LAYER via2  ;
    ANTENNAMAXCUTCAR 0.460202 LAYER via2  ;
    ANTENNAPARTIALMETALAREA 17.1348 LAYER met3  ;
    ANTENNAPARTIALMETALSIDEAREA 91.856 LAYER met3  ;
    ANTENNAGATEAREA 0.3735 LAYER met3  ;
    ANTENNAMAXAREACAR 145.25 LAYER met3  ;
    ANTENNAMAXSIDEAREACAR 735.032 LAYER met3  ;
    ANTENNAMAXCUTCAR 0.725397 LAYER via3  ;
    PORT
      LAYER met2 ;
        RECT 266.960000 0.000000 267.100000 0.485000 ;
    END
  END wbs_adr_i[12]
  PIN wbs_adr_i[11]
    DIRECTION INPUT ;
    USE SIGNAL ;
    ANTENNAPARTIALMETALAREA 5.555 LAYER met2  ;
    ANTENNAPARTIALMETALSIDEAREA 27.475 LAYER met2  ;
    ANTENNAPARTIALCUTAREA 0.04 LAYER via2  ;
    ANTENNAPARTIALMETALAREA 11.785 LAYER met3  ;
    ANTENNAPARTIALMETALSIDEAREA 63.32 LAYER met3  ;
    ANTENNAPARTIALCUTAREA 0.04 LAYER via3  ;
    ANTENNAPARTIALMETALAREA 1.3032 LAYER met4  ;
    ANTENNAPARTIALMETALSIDEAREA 8.832 LAYER met4  ;
    ANTENNAMODEL OXIDE1 ;
    ANTENNAGATEAREA 0.3735 LAYER met4  ;
    ANTENNAMAXAREACAR 48.1769 LAYER met4  ;
    ANTENNAMAXSIDEAREACAR 255.093 LAYER met4  ;
    ANTENNAMAXCUTCAR 1.04286 LAYER via4  ;
    PORT
      LAYER met2 ;
        RECT 249.940000 0.000000 250.080000 0.485000 ;
    END
  END wbs_adr_i[11]
  PIN wbs_adr_i[10]
    DIRECTION INPUT ;
    USE SIGNAL ;
    ANTENNAPARTIALMETALAREA 5.4219 LAYER met2  ;
    ANTENNAPARTIALMETALSIDEAREA 26.8835 LAYER met2  ;
    ANTENNAMODEL OXIDE1 ;
    ANTENNAGATEAREA 0.3735 LAYER met2  ;
    ANTENNAMAXAREACAR 35.0128 LAYER met2  ;
    ANTENNAMAXSIDEAREACAR 166.076 LAYER met2  ;
    ANTENNAMAXCUTCAR 0.289606 LAYER via2  ;
    PORT
      LAYER met2 ;
        RECT 232.460000 0.000000 232.600000 0.485000 ;
    END
  END wbs_adr_i[10]
  PIN wbs_adr_i[9]
    DIRECTION INPUT ;
    USE SIGNAL ;
    ANTENNAPARTIALMETALAREA 5.9434 LAYER met2  ;
    ANTENNAPARTIALMETALSIDEAREA 29.33 LAYER met2  ;
    ANTENNAMODEL OXIDE1 ;
    ANTENNAGATEAREA 0.2475 LAYER met2  ;
    ANTENNAMAXAREACAR 25.5665 LAYER met2  ;
    ANTENNAMAXSIDEAREACAR 121.949 LAYER met2  ;
    ANTENNAPARTIALCUTAREA 0.04 LAYER via2  ;
    ANTENNAMAXCUTCAR 0.369293 LAYER via2  ;
    ANTENNAPARTIALMETALAREA 7.4328 LAYER met3  ;
    ANTENNAPARTIALMETALSIDEAREA 40.112 LAYER met3  ;
    ANTENNAGATEAREA 0.3735 LAYER met3  ;
    ANTENNAMAXAREACAR 45.4669 LAYER met3  ;
    ANTENNAMAXSIDEAREACAR 229.344 LAYER met3  ;
    ANTENNAMAXCUTCAR 0.725397 LAYER via3  ;
    PORT
      LAYER met2 ;
        RECT 214.980000 0.000000 215.120000 0.485000 ;
    END
  END wbs_adr_i[9]
  PIN wbs_adr_i[8]
    DIRECTION INPUT ;
    USE SIGNAL ;
    ANTENNAPARTIALMETALAREA 4.7889 LAYER met2  ;
    ANTENNAPARTIALMETALSIDEAREA 23.6005 LAYER met2  ;
    ANTENNAMODEL OXIDE1 ;
    ANTENNAGATEAREA 0.3735 LAYER met2  ;
    ANTENNAMAXAREACAR 36.934 LAYER met2  ;
    ANTENNAMAXSIDEAREACAR 177.086 LAYER met2  ;
    ANTENNAMAXCUTCAR 0.407937 LAYER via2  ;
    PORT
      LAYER met2 ;
        RECT 197.500000 0.000000 197.640000 0.485000 ;
    END
  END wbs_adr_i[8]
  PIN wbs_adr_i[7]
    DIRECTION INPUT ;
    USE SIGNAL ;
    ANTENNAPARTIALMETALAREA 5.0269 LAYER met2  ;
    ANTENNAPARTIALMETALSIDEAREA 24.7905 LAYER met2  ;
    ANTENNAMODEL OXIDE1 ;
    ANTENNAGATEAREA 0.3735 LAYER met2  ;
    ANTENNAMAXAREACAR 48.9371 LAYER met2  ;
    ANTENNAMAXSIDEAREACAR 236.909 LAYER met2  ;
    ANTENNAMAXCUTCAR 0.407937 LAYER via2  ;
    PORT
      LAYER met2 ;
        RECT 180.020000 0.000000 180.160000 0.485000 ;
    END
  END wbs_adr_i[7]
  PIN wbs_adr_i[6]
    DIRECTION INPUT ;
    USE SIGNAL ;
    ANTENNAPARTIALMETALAREA 4.2031 LAYER met2  ;
    ANTENNAPARTIALMETALSIDEAREA 20.7095 LAYER met2  ;
    ANTENNAMODEL OXIDE1 ;
    ANTENNAGATEAREA 0.2475 LAYER met2  ;
    ANTENNAMAXAREACAR 18.0598 LAYER met2  ;
    ANTENNAMAXSIDEAREACAR 86.7636 LAYER met2  ;
    ANTENNAPARTIALCUTAREA 0.04 LAYER via2  ;
    ANTENNAMAXCUTCAR 0.369293 LAYER via2  ;
    ANTENNAPARTIALMETALAREA 10.3308 LAYER met3  ;
    ANTENNAPARTIALMETALSIDEAREA 55.568 LAYER met3  ;
    ANTENNAGATEAREA 0.3735 LAYER met3  ;
    ANTENNAMAXAREACAR 45.7192 LAYER met3  ;
    ANTENNAMAXSIDEAREACAR 235.54 LAYER met3  ;
    ANTENNAMAXCUTCAR 0.725397 LAYER via3  ;
    PORT
      LAYER met2 ;
        RECT 163.000000 0.000000 163.140000 0.485000 ;
    END
  END wbs_adr_i[6]
  PIN wbs_adr_i[5]
    DIRECTION INPUT ;
    USE SIGNAL ;
    ANTENNAPARTIALMETALAREA 5.8627 LAYER met2  ;
    ANTENNAPARTIALMETALSIDEAREA 28.9695 LAYER met2  ;
    ANTENNAMODEL OXIDE1 ;
    ANTENNAGATEAREA 0.3735 LAYER met2  ;
    ANTENNAMAXAREACAR 29.3304 LAYER met2  ;
    ANTENNAMAXSIDEAREACAR 138.876 LAYER met2  ;
    ANTENNAMAXCUTCAR 0.407937 LAYER via2  ;
    PORT
      LAYER met2 ;
        RECT 145.520000 0.000000 145.660000 0.485000 ;
    END
  END wbs_adr_i[5]
  PIN wbs_adr_i[4]
    DIRECTION INPUT ;
    USE SIGNAL ;
    ANTENNAPARTIALMETALAREA 5.1911 LAYER met2  ;
    ANTENNAPARTIALMETALSIDEAREA 25.6375 LAYER met2  ;
    ANTENNAMODEL OXIDE1 ;
    ANTENNAGATEAREA 0.2475 LAYER met2  ;
    ANTENNAMAXAREACAR 22.9434 LAYER met2  ;
    ANTENNAMAXSIDEAREACAR 107.479 LAYER met2  ;
    ANTENNAPARTIALCUTAREA 0.04 LAYER via2  ;
    ANTENNAMAXCUTCAR 0.369293 LAYER via2  ;
    ANTENNAPARTIALMETALAREA 6.0528 LAYER met3  ;
    ANTENNAPARTIALMETALSIDEAREA 32.752 LAYER met3  ;
    ANTENNAGATEAREA 0.3735 LAYER met3  ;
    ANTENNAMAXAREACAR 39.1491 LAYER met3  ;
    ANTENNAMAXSIDEAREACAR 195.168 LAYER met3  ;
    ANTENNAMAXCUTCAR 0.725397 LAYER via3  ;
    PORT
      LAYER met2 ;
        RECT 128.040000 0.000000 128.180000 0.485000 ;
    END
  END wbs_adr_i[4]
  PIN wbs_adr_i[3]
    DIRECTION INPUT ;
    USE SIGNAL ;
    ANTENNAPARTIALMETALAREA 5.2525 LAYER met2  ;
    ANTENNAPARTIALMETALSIDEAREA 26.0365 LAYER met2  ;
    ANTENNAMODEL OXIDE1 ;
    ANTENNAGATEAREA 0.3735 LAYER met2  ;
    ANTENNAMAXAREACAR 25.0366 LAYER met2  ;
    ANTENNAMAXSIDEAREACAR 116.196 LAYER met2  ;
    ANTENNAMAXCUTCAR 0.289606 LAYER via2  ;
    PORT
      LAYER met2 ;
        RECT 104.580000 0.000000 104.720000 0.485000 ;
    END
  END wbs_adr_i[3]
  PIN wbs_adr_i[2]
    DIRECTION INPUT ;
    USE SIGNAL ;
    ANTENNAPARTIALMETALAREA 6.1147 LAYER met2  ;
    ANTENNAPARTIALMETALSIDEAREA 30.2295 LAYER met2  ;
    ANTENNAMODEL OXIDE1 ;
    ANTENNAGATEAREA 0.9125 LAYER met2  ;
    ANTENNAMAXAREACAR 12.779 LAYER met2  ;
    ANTENNAMAXSIDEAREACAR 61.4858 LAYER met2  ;
    ANTENNAMAXCUTCAR 0.298586 LAYER via2  ;
    PORT
      LAYER met2 ;
        RECT 81.580000 0.000000 81.720000 0.485000 ;
    END
  END wbs_adr_i[2]
  PIN wbs_adr_i[1]
    DIRECTION INPUT ;
    USE SIGNAL ;
    ANTENNAPARTIALMETALAREA 7.1815 LAYER met2  ;
    ANTENNAPARTIALMETALSIDEAREA 35.5635 LAYER met2  ;
    ANTENNAMODEL OXIDE1 ;
    ANTENNAGATEAREA 0.3735 LAYER met2  ;
    ANTENNAMAXAREACAR 48.5502 LAYER met2  ;
    ANTENNAMAXSIDEAREACAR 234.975 LAYER met2  ;
    ANTENNAMAXCUTCAR 0.407937 LAYER via2  ;
    PORT
      LAYER met2 ;
        RECT 58.580000 0.000000 58.720000 0.485000 ;
    END
  END wbs_adr_i[1]
  PIN wbs_adr_i[0]
    DIRECTION INPUT ;
    USE SIGNAL ;
    ANTENNAPARTIALMETALAREA 4.1579 LAYER met2  ;
    ANTENNAPARTIALMETALSIDEAREA 20.6815 LAYER met2  ;
    ANTENNAMODEL OXIDE1 ;
    ANTENNAGATEAREA 0.665 LAYER met2  ;
    ANTENNAMAXAREACAR 7.82158 LAYER met2  ;
    ANTENNAMAXSIDEAREACAR 36.8752 LAYER met2  ;
    ANTENNAMAXCUTCAR 0.0772932 LAYER via2  ;
    PORT
      LAYER met2 ;
        RECT 35.120000 0.000000 35.260000 0.485000 ;
    END
  END wbs_adr_i[0]
  PIN wbs_ack_o
    DIRECTION OUTPUT ;
    USE SIGNAL ;
    ANTENNADIFFAREA 0.429 LAYER met2  ;
    ANTENNAPARTIALMETALAREA 4.764 LAYER met2  ;
    ANTENNAPARTIALMETALSIDEAREA 23.541 LAYER met2  ;
    ANTENNAPARTIALCUTAREA 0.04 LAYER via2  ;
    ANTENNADIFFAREA 0.429 LAYER met3  ;
    ANTENNAPARTIALMETALAREA 31.6278 LAYER met3  ;
    ANTENNAPARTIALMETALSIDEAREA 169.152 LAYER met3  ;
    ANTENNAMODEL OXIDE1 ;
    ANTENNAGATEAREA 0.495 LAYER met3  ;
    ANTENNAMAXAREACAR 67.9077 LAYER met3  ;
    ANTENNAMAXSIDEAREACAR 356.629 LAYER met3  ;
    ANTENNAMAXCUTCAR 0.288485 LAYER via3  ;
    PORT
      LAYER met2 ;
        RECT 12.120000 0.000000 12.260000 0.485000 ;
    END
  END wbs_ack_o
  PIN wbs_dat_o[31]
    DIRECTION OUTPUT ;
    USE SIGNAL ;
    ANTENNADIFFAREA 0.43675 LAYER met2  ;
    ANTENNAPARTIALMETALAREA 4.0627 LAYER met2  ;
    ANTENNAPARTIALMETALSIDEAREA 20.2055 LAYER met2  ;
    PORT
      LAYER met2 ;
        RECT 609.200000 0.000000 609.340000 0.485000 ;
    END
  END wbs_dat_o[31]
  PIN wbs_dat_o[30]
    DIRECTION OUTPUT ;
    USE SIGNAL ;
    ANTENNADIFFAREA 0.43675 LAYER met2  ;
    ANTENNAPARTIALMETALAREA 4.0627 LAYER met2  ;
    ANTENNAPARTIALMETALSIDEAREA 20.2055 LAYER met2  ;
    PORT
      LAYER met2 ;
        RECT 592.180000 0.000000 592.320000 0.485000 ;
    END
  END wbs_dat_o[30]
  PIN wbs_dat_o[29]
    DIRECTION OUTPUT ;
    USE SIGNAL ;
    ANTENNADIFFAREA 0.43675 LAYER met2  ;
    ANTENNAPARTIALMETALAREA 4.0627 LAYER met2  ;
    ANTENNAPARTIALMETALSIDEAREA 20.2055 LAYER met2  ;
    PORT
      LAYER met2 ;
        RECT 574.700000 0.000000 574.840000 0.485000 ;
    END
  END wbs_dat_o[29]
  PIN wbs_dat_o[28]
    DIRECTION OUTPUT ;
    USE SIGNAL ;
    ANTENNADIFFAREA 0.43675 LAYER met2  ;
    ANTENNAPARTIALMETALAREA 4.4435 LAYER met2  ;
    ANTENNAPARTIALMETALSIDEAREA 22.1095 LAYER met2  ;
    PORT
      LAYER met2 ;
        RECT 557.220000 0.000000 557.360000 0.485000 ;
    END
  END wbs_dat_o[28]
  PIN wbs_dat_o[27]
    DIRECTION OUTPUT ;
    USE SIGNAL ;
    ANTENNADIFFAREA 0.43675 LAYER met2  ;
    ANTENNAPARTIALMETALAREA 4.0627 LAYER met2  ;
    ANTENNAPARTIALMETALSIDEAREA 20.2055 LAYER met2  ;
    PORT
      LAYER met2 ;
        RECT 539.740000 0.000000 539.880000 0.485000 ;
    END
  END wbs_dat_o[27]
  PIN wbs_dat_o[26]
    DIRECTION OUTPUT ;
    USE SIGNAL ;
    ANTENNADIFFAREA 0.43675 LAYER met2  ;
    ANTENNAPARTIALMETALAREA 4.0627 LAYER met2  ;
    ANTENNAPARTIALMETALSIDEAREA 20.2055 LAYER met2  ;
    PORT
      LAYER met2 ;
        RECT 522.260000 0.000000 522.400000 0.485000 ;
    END
  END wbs_dat_o[26]
  PIN wbs_dat_o[25]
    DIRECTION OUTPUT ;
    USE SIGNAL ;
    ANTENNADIFFAREA 0.43675 LAYER met2  ;
    ANTENNAPARTIALMETALAREA 4.1103 LAYER met2  ;
    ANTENNAPARTIALMETALSIDEAREA 20.4435 LAYER met2  ;
    PORT
      LAYER met2 ;
        RECT 504.780000 0.000000 504.920000 0.485000 ;
    END
  END wbs_dat_o[25]
  PIN wbs_dat_o[24]
    DIRECTION OUTPUT ;
    USE SIGNAL ;
    ANTENNADIFFAREA 0.43675 LAYER met2  ;
    ANTENNAPARTIALMETALAREA 4.1915 LAYER met2  ;
    ANTENNAPARTIALMETALSIDEAREA 20.8495 LAYER met2  ;
    PORT
      LAYER met2 ;
        RECT 487.760000 0.000000 487.900000 0.485000 ;
    END
  END wbs_dat_o[24]
  PIN wbs_dat_o[23]
    DIRECTION OUTPUT ;
    USE SIGNAL ;
    ANTENNADIFFAREA 0.43675 LAYER met2  ;
    ANTENNAPARTIALMETALAREA 4.1271 LAYER met2  ;
    ANTENNAPARTIALMETALSIDEAREA 20.5275 LAYER met2  ;
    PORT
      LAYER met2 ;
        RECT 470.280000 0.000000 470.420000 0.485000 ;
    END
  END wbs_dat_o[23]
  PIN wbs_dat_o[22]
    DIRECTION OUTPUT ;
    USE SIGNAL ;
    ANTENNADIFFAREA 0.43675 LAYER met2  ;
    ANTENNAPARTIALMETALAREA 4.1271 LAYER met2  ;
    ANTENNAPARTIALMETALSIDEAREA 20.5275 LAYER met2  ;
    PORT
      LAYER met2 ;
        RECT 452.800000 0.000000 452.940000 0.485000 ;
    END
  END wbs_dat_o[22]
  PIN wbs_dat_o[21]
    DIRECTION OUTPUT ;
    USE SIGNAL ;
    ANTENNADIFFAREA 0.43675 LAYER met2  ;
    ANTENNAPARTIALMETALAREA 4.1103 LAYER met2  ;
    ANTENNAPARTIALMETALSIDEAREA 20.4435 LAYER met2  ;
    PORT
      LAYER met2 ;
        RECT 435.320000 0.000000 435.460000 0.485000 ;
    END
  END wbs_dat_o[21]
  PIN wbs_dat_o[20]
    DIRECTION OUTPUT ;
    USE SIGNAL ;
    ANTENNADIFFAREA 0.43675 LAYER met2  ;
    ANTENNAPARTIALMETALAREA 4.1915 LAYER met2  ;
    ANTENNAPARTIALMETALSIDEAREA 20.8495 LAYER met2  ;
    PORT
      LAYER met2 ;
        RECT 417.840000 0.000000 417.980000 0.485000 ;
    END
  END wbs_dat_o[20]
  PIN wbs_dat_o[19]
    DIRECTION OUTPUT ;
    USE SIGNAL ;
    ANTENNADIFFAREA 0.43675 LAYER met2  ;
    ANTENNAPARTIALMETALAREA 4.0627 LAYER met2  ;
    ANTENNAPARTIALMETALSIDEAREA 20.2055 LAYER met2  ;
    PORT
      LAYER met2 ;
        RECT 400.360000 0.000000 400.500000 0.485000 ;
    END
  END wbs_dat_o[19]
  PIN wbs_dat_o[18]
    DIRECTION OUTPUT ;
    USE SIGNAL ;
    ANTENNADIFFAREA 0.43675 LAYER met2  ;
    ANTENNAPARTIALMETALAREA 4.0627 LAYER met2  ;
    ANTENNAPARTIALMETALSIDEAREA 20.2055 LAYER met2  ;
    PORT
      LAYER met2 ;
        RECT 383.340000 0.000000 383.480000 0.485000 ;
    END
  END wbs_dat_o[18]
  PIN wbs_dat_o[17]
    DIRECTION OUTPUT ;
    USE SIGNAL ;
    ANTENNADIFFAREA 0.43675 LAYER met2  ;
    ANTENNAPARTIALMETALAREA 4.0627 LAYER met2  ;
    ANTENNAPARTIALMETALSIDEAREA 20.2055 LAYER met2  ;
    PORT
      LAYER met2 ;
        RECT 365.860000 0.000000 366.000000 0.485000 ;
    END
  END wbs_dat_o[17]
  PIN wbs_dat_o[16]
    DIRECTION OUTPUT ;
    USE SIGNAL ;
    ANTENNADIFFAREA 0.43675 LAYER met2  ;
    ANTENNAPARTIALMETALAREA 4.0627 LAYER met2  ;
    ANTENNAPARTIALMETALSIDEAREA 20.2055 LAYER met2  ;
    PORT
      LAYER met2 ;
        RECT 348.380000 0.000000 348.520000 0.485000 ;
    END
  END wbs_dat_o[16]
  PIN wbs_dat_o[15]
    DIRECTION OUTPUT ;
    USE SIGNAL ;
    ANTENNADIFFAREA 0.429 LAYER met2  ;
    ANTENNAPARTIALMETALAREA 10.6747 LAYER met2  ;
    ANTENNAPARTIALMETALSIDEAREA 53.1475 LAYER met2  ;
    PORT
      LAYER met2 ;
        RECT 330.900000 0.000000 331.040000 0.485000 ;
    END
  END wbs_dat_o[15]
  PIN wbs_dat_o[14]
    DIRECTION OUTPUT ;
    USE SIGNAL ;
    ANTENNAPARTIALMETALAREA 9.4976 LAYER met2  ;
    ANTENNAPARTIALMETALSIDEAREA 47.327 LAYER met2  ;
    ANTENNAPARTIALCUTAREA 0.04 LAYER via2  ;
    ANTENNADIFFAREA 0.429 LAYER met3  ;
    ANTENNAPARTIALMETALAREA 52.5108 LAYER met3  ;
    ANTENNAPARTIALMETALSIDEAREA 280.528 LAYER met3  ;
    PORT
      LAYER met2 ;
        RECT 313.420000 0.000000 313.560000 0.485000 ;
    END
  END wbs_dat_o[14]
  PIN wbs_dat_o[13]
    DIRECTION OUTPUT ;
    USE SIGNAL ;
    ANTENNADIFFAREA 0.429 LAYER met2  ;
    ANTENNAPARTIALMETALAREA 9.2635 LAYER met2  ;
    ANTENNAPARTIALMETALSIDEAREA 46.0915 LAYER met2  ;
    PORT
      LAYER met2 ;
        RECT 296.400000 0.000000 296.540000 0.485000 ;
    END
  END wbs_dat_o[13]
  PIN wbs_dat_o[12]
    DIRECTION OUTPUT ;
    USE SIGNAL ;
    ANTENNAPARTIALMETALAREA 8.5372 LAYER met2  ;
    ANTENNAPARTIALMETALSIDEAREA 42.525 LAYER met2  ;
    ANTENNAPARTIALCUTAREA 0.04 LAYER via2  ;
    ANTENNADIFFAREA 0.429 LAYER met3  ;
    ANTENNAPARTIALMETALAREA 60.7908 LAYER met3  ;
    ANTENNAPARTIALMETALSIDEAREA 324.688 LAYER met3  ;
    PORT
      LAYER met2 ;
        RECT 278.920000 0.000000 279.060000 0.485000 ;
    END
  END wbs_dat_o[12]
  PIN wbs_dat_o[11]
    DIRECTION OUTPUT ;
    USE SIGNAL ;
    ANTENNAPARTIALMETALAREA 11.4198 LAYER met2  ;
    ANTENNAPARTIALMETALSIDEAREA 56.938 LAYER met2  ;
    ANTENNAPARTIALCUTAREA 0.04 LAYER via2  ;
    ANTENNADIFFAREA 0.429 LAYER met3  ;
    ANTENNAPARTIALMETALAREA 69.1128 LAYER met3  ;
    ANTENNAPARTIALMETALSIDEAREA 369.072 LAYER met3  ;
    PORT
      LAYER met2 ;
        RECT 261.440000 0.000000 261.580000 0.485000 ;
    END
  END wbs_dat_o[11]
  PIN wbs_dat_o[10]
    DIRECTION OUTPUT ;
    USE SIGNAL ;
    ANTENNAPARTIALMETALAREA 12.2304 LAYER met2  ;
    ANTENNAPARTIALMETALSIDEAREA 60.991 LAYER met2  ;
    ANTENNAPARTIALCUTAREA 0.04 LAYER via2  ;
    ANTENNADIFFAREA 0.429 LAYER met3  ;
    ANTENNAPARTIALMETALAREA 73.5348 LAYER met3  ;
    ANTENNAPARTIALMETALSIDEAREA 392.656 LAYER met3  ;
    PORT
      LAYER met2 ;
        RECT 243.960000 0.000000 244.100000 0.485000 ;
    END
  END wbs_dat_o[10]
  PIN wbs_dat_o[9]
    DIRECTION OUTPUT ;
    USE SIGNAL ;
    ANTENNAPARTIALMETALAREA 10.1808 LAYER met2  ;
    ANTENNAPARTIALMETALSIDEAREA 50.743 LAYER met2  ;
    ANTENNAPARTIALCUTAREA 0.04 LAYER via2  ;
    ANTENNADIFFAREA 0.429 LAYER met3  ;
    ANTENNAPARTIALMETALAREA 76.7508 LAYER met3  ;
    ANTENNAPARTIALMETALSIDEAREA 409.808 LAYER met3  ;
    PORT
      LAYER met2 ;
        RECT 226.480000 0.000000 226.620000 0.485000 ;
    END
  END wbs_dat_o[9]
  PIN wbs_dat_o[8]
    DIRECTION OUTPUT ;
    USE SIGNAL ;
    ANTENNAPARTIALMETALAREA 11.9152 LAYER met2  ;
    ANTENNAPARTIALMETALSIDEAREA 59.297 LAYER met2  ;
    ANTENNAPARTIALCUTAREA 0.04 LAYER via2  ;
    ANTENNADIFFAREA 0.429 LAYER met3  ;
    ANTENNAPARTIALMETALAREA 41.3328 LAYER met3  ;
    ANTENNAPARTIALMETALSIDEAREA 220.912 LAYER met3  ;
    PORT
      LAYER met2 ;
        RECT 209.000000 0.000000 209.140000 0.485000 ;
    END
  END wbs_dat_o[8]
  PIN wbs_dat_o[7]
    DIRECTION OUTPUT ;
    USE SIGNAL ;
    ANTENNAPARTIALMETALAREA 11.2418 LAYER met2  ;
    ANTENNAPARTIALMETALSIDEAREA 55.93 LAYER met2  ;
    ANTENNAPARTIALCUTAREA 0.04 LAYER via2  ;
    ANTENNADIFFAREA 0.429 LAYER met3  ;
    ANTENNAPARTIALMETALAREA 41.2848 LAYER met3  ;
    ANTENNAPARTIALMETALSIDEAREA 220.656 LAYER met3  ;
    PORT
      LAYER met2 ;
        RECT 191.980000 0.000000 192.120000 0.485000 ;
    END
  END wbs_dat_o[7]
  PIN wbs_dat_o[6]
    DIRECTION OUTPUT ;
    USE SIGNAL ;
    ANTENNAPARTIALMETALAREA 8.8366 LAYER met2  ;
    ANTENNAPARTIALMETALSIDEAREA 43.904 LAYER met2  ;
    ANTENNAPARTIALCUTAREA 0.04 LAYER via2  ;
    ANTENNADIFFAREA 0.429 LAYER met3  ;
    ANTENNAPARTIALMETALAREA 32.1348 LAYER met3  ;
    ANTENNAPARTIALMETALSIDEAREA 171.856 LAYER met3  ;
    PORT
      LAYER met2 ;
        RECT 174.500000 0.000000 174.640000 0.485000 ;
    END
  END wbs_dat_o[6]
  PIN wbs_dat_o[5]
    DIRECTION OUTPUT ;
    USE SIGNAL ;
    ANTENNAPARTIALMETALAREA 9.8392 LAYER met2  ;
    ANTENNAPARTIALMETALSIDEAREA 49.035 LAYER met2  ;
    ANTENNAPARTIALCUTAREA 0.04 LAYER via2  ;
    ANTENNADIFFAREA 0.429 LAYER met3  ;
    ANTENNAPARTIALMETALAREA 96.5808 LAYER met3  ;
    ANTENNAPARTIALMETALSIDEAREA 515.568 LAYER met3  ;
    PORT
      LAYER met2 ;
        RECT 157.020000 0.000000 157.160000 0.485000 ;
    END
  END wbs_dat_o[5]
  PIN wbs_dat_o[4]
    DIRECTION OUTPUT ;
    USE SIGNAL ;
    ANTENNAPARTIALMETALAREA 10.217 LAYER met2  ;
    ANTENNAPARTIALMETALSIDEAREA 50.806 LAYER met2  ;
    ANTENNAPARTIALCUTAREA 0.04 LAYER via2  ;
    ANTENNADIFFAREA 0.429 LAYER met3  ;
    ANTENNAPARTIALMETALAREA 31.3068 LAYER met3  ;
    ANTENNAPARTIALMETALSIDEAREA 167.44 LAYER met3  ;
    PORT
      LAYER met2 ;
        RECT 139.540000 0.000000 139.680000 0.485000 ;
    END
  END wbs_dat_o[4]
  PIN wbs_dat_o[3]
    DIRECTION OUTPUT ;
    USE SIGNAL ;
    ANTENNADIFFAREA 0.429 LAYER met2  ;
    ANTENNAPARTIALMETALAREA 9.7899 LAYER met2  ;
    ANTENNAPARTIALMETALSIDEAREA 48.7235 LAYER met2  ;
    PORT
      LAYER met2 ;
        RECT 116.540000 0.000000 116.680000 0.485000 ;
    END
  END wbs_dat_o[3]
  PIN wbs_dat_o[2]
    DIRECTION OUTPUT ;
    USE SIGNAL ;
    ANTENNAPARTIALMETALAREA 10.896 LAYER met2  ;
    ANTENNAPARTIALMETALSIDEAREA 54.201 LAYER met2  ;
    ANTENNAPARTIALCUTAREA 0.04 LAYER via2  ;
    ANTENNADIFFAREA 0.429 LAYER met3  ;
    ANTENNAPARTIALMETALAREA 19.9848 LAYER met3  ;
    ANTENNAPARTIALMETALSIDEAREA 107.056 LAYER met3  ;
    PORT
      LAYER met2 ;
        RECT 93.080000 0.000000 93.220000 0.485000 ;
    END
  END wbs_dat_o[2]
  PIN wbs_dat_o[1]
    DIRECTION OUTPUT ;
    USE SIGNAL ;
    ANTENNAPARTIALMETALAREA 8.6436 LAYER met2  ;
    ANTENNAPARTIALMETALSIDEAREA 43.057 LAYER met2  ;
    ANTENNAPARTIALCUTAREA 0.04 LAYER via2  ;
    ANTENNADIFFAREA 0.429 LAYER met3  ;
    ANTENNAPARTIALMETALAREA 122.705 LAYER met3  ;
    ANTENNAPARTIALMETALSIDEAREA 654.896 LAYER met3  ;
    PORT
      LAYER met2 ;
        RECT 70.080000 0.000000 70.220000 0.485000 ;
    END
  END wbs_dat_o[1]
  PIN wbs_dat_o[0]
    DIRECTION OUTPUT ;
    USE SIGNAL ;
    ANTENNAPARTIALMETALAREA 12.737 LAYER met2  ;
    ANTENNAPARTIALMETALSIDEAREA 63.406 LAYER met2  ;
    ANTENNAPARTIALCUTAREA 0.04 LAYER via2  ;
    ANTENNADIFFAREA 0.429 LAYER met3  ;
    ANTENNAPARTIALMETALAREA 35.3088 LAYER met3  ;
    ANTENNAPARTIALMETALSIDEAREA 188.784 LAYER met3  ;
    PORT
      LAYER met2 ;
        RECT 46.620000 0.000000 46.760000 0.485000 ;
    END
  END wbs_dat_o[0]
  PIN la_data_in[127]
    DIRECTION INPUT ;
    USE SIGNAL ;
    PORT
      LAYER met2 ;
        RECT 2825.020000 0.000000 2825.160000 0.485000 ;
    END
  END la_data_in[127]
  PIN la_data_in[126]
    DIRECTION INPUT ;
    USE SIGNAL ;
    PORT
      LAYER met2 ;
        RECT 2807.540000 0.000000 2807.680000 0.485000 ;
    END
  END la_data_in[126]
  PIN la_data_in[125]
    DIRECTION INPUT ;
    USE SIGNAL ;
    PORT
      LAYER met2 ;
        RECT 2790.060000 0.000000 2790.200000 0.485000 ;
    END
  END la_data_in[125]
  PIN la_data_in[124]
    DIRECTION INPUT ;
    USE SIGNAL ;
    PORT
      LAYER met2 ;
        RECT 2772.580000 0.000000 2772.720000 0.485000 ;
    END
  END la_data_in[124]
  PIN la_data_in[123]
    DIRECTION INPUT ;
    USE SIGNAL ;
    PORT
      LAYER met2 ;
        RECT 2755.560000 0.000000 2755.700000 0.485000 ;
    END
  END la_data_in[123]
  PIN la_data_in[122]
    DIRECTION INPUT ;
    USE SIGNAL ;
    PORT
      LAYER met2 ;
        RECT 2738.080000 0.000000 2738.220000 0.485000 ;
    END
  END la_data_in[122]
  PIN la_data_in[121]
    DIRECTION INPUT ;
    USE SIGNAL ;
    PORT
      LAYER met2 ;
        RECT 2720.600000 0.000000 2720.740000 0.485000 ;
    END
  END la_data_in[121]
  PIN la_data_in[120]
    DIRECTION INPUT ;
    USE SIGNAL ;
    PORT
      LAYER met2 ;
        RECT 2703.120000 0.000000 2703.260000 0.485000 ;
    END
  END la_data_in[120]
  PIN la_data_in[119]
    DIRECTION INPUT ;
    USE SIGNAL ;
    PORT
      LAYER met2 ;
        RECT 2685.640000 0.000000 2685.780000 0.485000 ;
    END
  END la_data_in[119]
  PIN la_data_in[118]
    DIRECTION INPUT ;
    USE SIGNAL ;
    PORT
      LAYER met2 ;
        RECT 2668.160000 0.000000 2668.300000 0.485000 ;
    END
  END la_data_in[118]
  PIN la_data_in[117]
    DIRECTION INPUT ;
    USE SIGNAL ;
    PORT
      LAYER met2 ;
        RECT 2651.140000 0.000000 2651.280000 0.485000 ;
    END
  END la_data_in[117]
  PIN la_data_in[116]
    DIRECTION INPUT ;
    USE SIGNAL ;
    PORT
      LAYER met2 ;
        RECT 2633.660000 0.000000 2633.800000 0.485000 ;
    END
  END la_data_in[116]
  PIN la_data_in[115]
    DIRECTION INPUT ;
    USE SIGNAL ;
    PORT
      LAYER met2 ;
        RECT 2616.180000 0.000000 2616.320000 0.485000 ;
    END
  END la_data_in[115]
  PIN la_data_in[114]
    DIRECTION INPUT ;
    USE SIGNAL ;
    PORT
      LAYER met2 ;
        RECT 2598.700000 0.000000 2598.840000 0.485000 ;
    END
  END la_data_in[114]
  PIN la_data_in[113]
    DIRECTION INPUT ;
    USE SIGNAL ;
    PORT
      LAYER met2 ;
        RECT 2581.220000 0.000000 2581.360000 0.485000 ;
    END
  END la_data_in[113]
  PIN la_data_in[112]
    DIRECTION INPUT ;
    USE SIGNAL ;
    PORT
      LAYER met2 ;
        RECT 2563.740000 0.000000 2563.880000 0.485000 ;
    END
  END la_data_in[112]
  PIN la_data_in[111]
    DIRECTION INPUT ;
    USE SIGNAL ;
    PORT
      LAYER met2 ;
        RECT 2546.720000 0.000000 2546.860000 0.485000 ;
    END
  END la_data_in[111]
  PIN la_data_in[110]
    DIRECTION INPUT ;
    USE SIGNAL ;
    PORT
      LAYER met2 ;
        RECT 2529.240000 0.000000 2529.380000 0.485000 ;
    END
  END la_data_in[110]
  PIN la_data_in[109]
    DIRECTION INPUT ;
    USE SIGNAL ;
    PORT
      LAYER met2 ;
        RECT 2511.760000 0.000000 2511.900000 0.485000 ;
    END
  END la_data_in[109]
  PIN la_data_in[108]
    DIRECTION INPUT ;
    USE SIGNAL ;
    PORT
      LAYER met2 ;
        RECT 2494.280000 0.000000 2494.420000 0.485000 ;
    END
  END la_data_in[108]
  PIN la_data_in[107]
    DIRECTION INPUT ;
    USE SIGNAL ;
    PORT
      LAYER met2 ;
        RECT 2476.800000 0.000000 2476.940000 0.485000 ;
    END
  END la_data_in[107]
  PIN la_data_in[106]
    DIRECTION INPUT ;
    USE SIGNAL ;
    PORT
      LAYER met2 ;
        RECT 2459.780000 0.000000 2459.920000 0.485000 ;
    END
  END la_data_in[106]
  PIN la_data_in[105]
    DIRECTION INPUT ;
    USE SIGNAL ;
    PORT
      LAYER met2 ;
        RECT 2442.300000 0.000000 2442.440000 0.485000 ;
    END
  END la_data_in[105]
  PIN la_data_in[104]
    DIRECTION INPUT ;
    USE SIGNAL ;
    PORT
      LAYER met2 ;
        RECT 2424.820000 0.000000 2424.960000 0.485000 ;
    END
  END la_data_in[104]
  PIN la_data_in[103]
    DIRECTION INPUT ;
    USE SIGNAL ;
    PORT
      LAYER met2 ;
        RECT 2407.340000 0.000000 2407.480000 0.485000 ;
    END
  END la_data_in[103]
  PIN la_data_in[102]
    DIRECTION INPUT ;
    USE SIGNAL ;
    PORT
      LAYER met2 ;
        RECT 2389.860000 0.000000 2390.000000 0.485000 ;
    END
  END la_data_in[102]
  PIN la_data_in[101]
    DIRECTION INPUT ;
    USE SIGNAL ;
    PORT
      LAYER met2 ;
        RECT 2372.380000 0.000000 2372.520000 0.485000 ;
    END
  END la_data_in[101]
  PIN la_data_in[100]
    DIRECTION INPUT ;
    USE SIGNAL ;
    PORT
      LAYER met2 ;
        RECT 2355.360000 0.000000 2355.500000 0.485000 ;
    END
  END la_data_in[100]
  PIN la_data_in[99]
    DIRECTION INPUT ;
    USE SIGNAL ;
    PORT
      LAYER met2 ;
        RECT 2337.880000 0.000000 2338.020000 0.485000 ;
    END
  END la_data_in[99]
  PIN la_data_in[98]
    DIRECTION INPUT ;
    USE SIGNAL ;
    PORT
      LAYER met2 ;
        RECT 2320.400000 0.000000 2320.540000 0.485000 ;
    END
  END la_data_in[98]
  PIN la_data_in[97]
    DIRECTION INPUT ;
    USE SIGNAL ;
    PORT
      LAYER met2 ;
        RECT 2302.920000 0.000000 2303.060000 0.485000 ;
    END
  END la_data_in[97]
  PIN la_data_in[96]
    DIRECTION INPUT ;
    USE SIGNAL ;
    PORT
      LAYER met2 ;
        RECT 2285.440000 0.000000 2285.580000 0.485000 ;
    END
  END la_data_in[96]
  PIN la_data_in[95]
    DIRECTION INPUT ;
    USE SIGNAL ;
    PORT
      LAYER met2 ;
        RECT 2267.960000 0.000000 2268.100000 0.485000 ;
    END
  END la_data_in[95]
  PIN la_data_in[94]
    DIRECTION INPUT ;
    USE SIGNAL ;
    PORT
      LAYER met2 ;
        RECT 2250.940000 0.000000 2251.080000 0.485000 ;
    END
  END la_data_in[94]
  PIN la_data_in[93]
    DIRECTION INPUT ;
    USE SIGNAL ;
    PORT
      LAYER met2 ;
        RECT 2233.460000 0.000000 2233.600000 0.485000 ;
    END
  END la_data_in[93]
  PIN la_data_in[92]
    DIRECTION INPUT ;
    USE SIGNAL ;
    PORT
      LAYER met2 ;
        RECT 2215.980000 0.000000 2216.120000 0.485000 ;
    END
  END la_data_in[92]
  PIN la_data_in[91]
    DIRECTION INPUT ;
    USE SIGNAL ;
    PORT
      LAYER met2 ;
        RECT 2198.500000 0.000000 2198.640000 0.485000 ;
    END
  END la_data_in[91]
  PIN la_data_in[90]
    DIRECTION INPUT ;
    USE SIGNAL ;
    PORT
      LAYER met2 ;
        RECT 2181.020000 0.000000 2181.160000 0.485000 ;
    END
  END la_data_in[90]
  PIN la_data_in[89]
    DIRECTION INPUT ;
    USE SIGNAL ;
    PORT
      LAYER met2 ;
        RECT 2163.540000 0.000000 2163.680000 0.485000 ;
    END
  END la_data_in[89]
  PIN la_data_in[88]
    DIRECTION INPUT ;
    USE SIGNAL ;
    PORT
      LAYER met2 ;
        RECT 2146.520000 0.000000 2146.660000 0.485000 ;
    END
  END la_data_in[88]
  PIN la_data_in[87]
    DIRECTION INPUT ;
    USE SIGNAL ;
    PORT
      LAYER met2 ;
        RECT 2129.040000 0.000000 2129.180000 0.485000 ;
    END
  END la_data_in[87]
  PIN la_data_in[86]
    DIRECTION INPUT ;
    USE SIGNAL ;
    PORT
      LAYER met2 ;
        RECT 2111.560000 0.000000 2111.700000 0.485000 ;
    END
  END la_data_in[86]
  PIN la_data_in[85]
    DIRECTION INPUT ;
    USE SIGNAL ;
    PORT
      LAYER met2 ;
        RECT 2094.080000 0.000000 2094.220000 0.485000 ;
    END
  END la_data_in[85]
  PIN la_data_in[84]
    DIRECTION INPUT ;
    USE SIGNAL ;
    PORT
      LAYER met2 ;
        RECT 2076.600000 0.000000 2076.740000 0.485000 ;
    END
  END la_data_in[84]
  PIN la_data_in[83]
    DIRECTION INPUT ;
    USE SIGNAL ;
    PORT
      LAYER met2 ;
        RECT 2059.580000 0.000000 2059.720000 0.485000 ;
    END
  END la_data_in[83]
  PIN la_data_in[82]
    DIRECTION INPUT ;
    USE SIGNAL ;
    PORT
      LAYER met2 ;
        RECT 2042.100000 0.000000 2042.240000 0.485000 ;
    END
  END la_data_in[82]
  PIN la_data_in[81]
    DIRECTION INPUT ;
    USE SIGNAL ;
    PORT
      LAYER met2 ;
        RECT 2024.620000 0.000000 2024.760000 0.485000 ;
    END
  END la_data_in[81]
  PIN la_data_in[80]
    DIRECTION INPUT ;
    USE SIGNAL ;
    PORT
      LAYER met2 ;
        RECT 2007.140000 0.000000 2007.280000 0.485000 ;
    END
  END la_data_in[80]
  PIN la_data_in[79]
    DIRECTION INPUT ;
    USE SIGNAL ;
    PORT
      LAYER met2 ;
        RECT 1989.660000 0.000000 1989.800000 0.485000 ;
    END
  END la_data_in[79]
  PIN la_data_in[78]
    DIRECTION INPUT ;
    USE SIGNAL ;
    PORT
      LAYER met2 ;
        RECT 1972.180000 0.000000 1972.320000 0.485000 ;
    END
  END la_data_in[78]
  PIN la_data_in[77]
    DIRECTION INPUT ;
    USE SIGNAL ;
    PORT
      LAYER met2 ;
        RECT 1955.160000 0.000000 1955.300000 0.485000 ;
    END
  END la_data_in[77]
  PIN la_data_in[76]
    DIRECTION INPUT ;
    USE SIGNAL ;
    PORT
      LAYER met2 ;
        RECT 1937.680000 0.000000 1937.820000 0.485000 ;
    END
  END la_data_in[76]
  PIN la_data_in[75]
    DIRECTION INPUT ;
    USE SIGNAL ;
    PORT
      LAYER met2 ;
        RECT 1920.200000 0.000000 1920.340000 0.485000 ;
    END
  END la_data_in[75]
  PIN la_data_in[74]
    DIRECTION INPUT ;
    USE SIGNAL ;
    PORT
      LAYER met2 ;
        RECT 1902.720000 0.000000 1902.860000 0.485000 ;
    END
  END la_data_in[74]
  PIN la_data_in[73]
    DIRECTION INPUT ;
    USE SIGNAL ;
    PORT
      LAYER met2 ;
        RECT 1885.240000 0.000000 1885.380000 0.485000 ;
    END
  END la_data_in[73]
  PIN la_data_in[72]
    DIRECTION INPUT ;
    USE SIGNAL ;
    PORT
      LAYER met2 ;
        RECT 1867.760000 0.000000 1867.900000 0.485000 ;
    END
  END la_data_in[72]
  PIN la_data_in[71]
    DIRECTION INPUT ;
    USE SIGNAL ;
    PORT
      LAYER met2 ;
        RECT 1850.740000 0.000000 1850.880000 0.485000 ;
    END
  END la_data_in[71]
  PIN la_data_in[70]
    DIRECTION INPUT ;
    USE SIGNAL ;
    PORT
      LAYER met2 ;
        RECT 1833.260000 0.000000 1833.400000 0.485000 ;
    END
  END la_data_in[70]
  PIN la_data_in[69]
    DIRECTION INPUT ;
    USE SIGNAL ;
    PORT
      LAYER met2 ;
        RECT 1815.780000 0.000000 1815.920000 0.485000 ;
    END
  END la_data_in[69]
  PIN la_data_in[68]
    DIRECTION INPUT ;
    USE SIGNAL ;
    PORT
      LAYER met2 ;
        RECT 1798.300000 0.000000 1798.440000 0.485000 ;
    END
  END la_data_in[68]
  PIN la_data_in[67]
    DIRECTION INPUT ;
    USE SIGNAL ;
    PORT
      LAYER met2 ;
        RECT 1780.820000 0.000000 1780.960000 0.485000 ;
    END
  END la_data_in[67]
  PIN la_data_in[66]
    DIRECTION INPUT ;
    USE SIGNAL ;
    PORT
      LAYER met2 ;
        RECT 1763.340000 0.000000 1763.480000 0.485000 ;
    END
  END la_data_in[66]
  PIN la_data_in[65]
    DIRECTION INPUT ;
    USE SIGNAL ;
    PORT
      LAYER met2 ;
        RECT 1746.320000 0.000000 1746.460000 0.485000 ;
    END
  END la_data_in[65]
  PIN la_data_in[64]
    DIRECTION INPUT ;
    USE SIGNAL ;
    PORT
      LAYER met2 ;
        RECT 1728.840000 0.000000 1728.980000 0.485000 ;
    END
  END la_data_in[64]
  PIN la_data_in[63]
    DIRECTION INPUT ;
    USE SIGNAL ;
    PORT
      LAYER met2 ;
        RECT 1711.360000 0.000000 1711.500000 0.485000 ;
    END
  END la_data_in[63]
  PIN la_data_in[62]
    DIRECTION INPUT ;
    USE SIGNAL ;
    PORT
      LAYER met2 ;
        RECT 1693.880000 0.000000 1694.020000 0.485000 ;
    END
  END la_data_in[62]
  PIN la_data_in[61]
    DIRECTION INPUT ;
    USE SIGNAL ;
    PORT
      LAYER met2 ;
        RECT 1676.400000 0.000000 1676.540000 0.485000 ;
    END
  END la_data_in[61]
  PIN la_data_in[60]
    DIRECTION INPUT ;
    USE SIGNAL ;
    PORT
      LAYER met2 ;
        RECT 1659.380000 0.000000 1659.520000 0.485000 ;
    END
  END la_data_in[60]
  PIN la_data_in[59]
    DIRECTION INPUT ;
    USE SIGNAL ;
    PORT
      LAYER met2 ;
        RECT 1641.900000 0.000000 1642.040000 0.485000 ;
    END
  END la_data_in[59]
  PIN la_data_in[58]
    DIRECTION INPUT ;
    USE SIGNAL ;
    PORT
      LAYER met2 ;
        RECT 1624.420000 0.000000 1624.560000 0.485000 ;
    END
  END la_data_in[58]
  PIN la_data_in[57]
    DIRECTION INPUT ;
    USE SIGNAL ;
    PORT
      LAYER met2 ;
        RECT 1606.940000 0.000000 1607.080000 0.485000 ;
    END
  END la_data_in[57]
  PIN la_data_in[56]
    DIRECTION INPUT ;
    USE SIGNAL ;
    PORT
      LAYER met2 ;
        RECT 1589.460000 0.000000 1589.600000 0.485000 ;
    END
  END la_data_in[56]
  PIN la_data_in[55]
    DIRECTION INPUT ;
    USE SIGNAL ;
    PORT
      LAYER met2 ;
        RECT 1571.980000 0.000000 1572.120000 0.485000 ;
    END
  END la_data_in[55]
  PIN la_data_in[54]
    DIRECTION INPUT ;
    USE SIGNAL ;
    PORT
      LAYER met2 ;
        RECT 1554.960000 0.000000 1555.100000 0.485000 ;
    END
  END la_data_in[54]
  PIN la_data_in[53]
    DIRECTION INPUT ;
    USE SIGNAL ;
    PORT
      LAYER met2 ;
        RECT 1537.480000 0.000000 1537.620000 0.485000 ;
    END
  END la_data_in[53]
  PIN la_data_in[52]
    DIRECTION INPUT ;
    USE SIGNAL ;
    PORT
      LAYER met2 ;
        RECT 1520.000000 0.000000 1520.140000 0.485000 ;
    END
  END la_data_in[52]
  PIN la_data_in[51]
    DIRECTION INPUT ;
    USE SIGNAL ;
    PORT
      LAYER met2 ;
        RECT 1502.520000 0.000000 1502.660000 0.485000 ;
    END
  END la_data_in[51]
  PIN la_data_in[50]
    DIRECTION INPUT ;
    USE SIGNAL ;
    PORT
      LAYER met2 ;
        RECT 1485.040000 0.000000 1485.180000 0.485000 ;
    END
  END la_data_in[50]
  PIN la_data_in[49]
    DIRECTION INPUT ;
    USE SIGNAL ;
    PORT
      LAYER met2 ;
        RECT 1467.560000 0.000000 1467.700000 0.485000 ;
    END
  END la_data_in[49]
  PIN la_data_in[48]
    DIRECTION INPUT ;
    USE SIGNAL ;
    PORT
      LAYER met2 ;
        RECT 1450.540000 0.000000 1450.680000 0.485000 ;
    END
  END la_data_in[48]
  PIN la_data_in[47]
    DIRECTION INPUT ;
    USE SIGNAL ;
    PORT
      LAYER met2 ;
        RECT 1433.060000 0.000000 1433.200000 0.485000 ;
    END
  END la_data_in[47]
  PIN la_data_in[46]
    DIRECTION INPUT ;
    USE SIGNAL ;
    PORT
      LAYER met2 ;
        RECT 1415.580000 0.000000 1415.720000 0.485000 ;
    END
  END la_data_in[46]
  PIN la_data_in[45]
    DIRECTION INPUT ;
    USE SIGNAL ;
    PORT
      LAYER met2 ;
        RECT 1398.100000 0.000000 1398.240000 0.485000 ;
    END
  END la_data_in[45]
  PIN la_data_in[44]
    DIRECTION INPUT ;
    USE SIGNAL ;
    PORT
      LAYER met2 ;
        RECT 1380.620000 0.000000 1380.760000 0.485000 ;
    END
  END la_data_in[44]
  PIN la_data_in[43]
    DIRECTION INPUT ;
    USE SIGNAL ;
    PORT
      LAYER met2 ;
        RECT 1363.600000 0.000000 1363.740000 0.485000 ;
    END
  END la_data_in[43]
  PIN la_data_in[42]
    DIRECTION INPUT ;
    USE SIGNAL ;
    PORT
      LAYER met2 ;
        RECT 1346.120000 0.000000 1346.260000 0.485000 ;
    END
  END la_data_in[42]
  PIN la_data_in[41]
    DIRECTION INPUT ;
    USE SIGNAL ;
    PORT
      LAYER met2 ;
        RECT 1328.640000 0.000000 1328.780000 0.485000 ;
    END
  END la_data_in[41]
  PIN la_data_in[40]
    DIRECTION INPUT ;
    USE SIGNAL ;
    PORT
      LAYER met2 ;
        RECT 1311.160000 0.000000 1311.300000 0.485000 ;
    END
  END la_data_in[40]
  PIN la_data_in[39]
    DIRECTION INPUT ;
    USE SIGNAL ;
    PORT
      LAYER met2 ;
        RECT 1293.680000 0.000000 1293.820000 0.485000 ;
    END
  END la_data_in[39]
  PIN la_data_in[38]
    DIRECTION INPUT ;
    USE SIGNAL ;
    PORT
      LAYER met2 ;
        RECT 1276.200000 0.000000 1276.340000 0.485000 ;
    END
  END la_data_in[38]
  PIN la_data_in[37]
    DIRECTION INPUT ;
    USE SIGNAL ;
    PORT
      LAYER met2 ;
        RECT 1259.180000 0.000000 1259.320000 0.485000 ;
    END
  END la_data_in[37]
  PIN la_data_in[36]
    DIRECTION INPUT ;
    USE SIGNAL ;
    PORT
      LAYER met2 ;
        RECT 1241.700000 0.000000 1241.840000 0.485000 ;
    END
  END la_data_in[36]
  PIN la_data_in[35]
    DIRECTION INPUT ;
    USE SIGNAL ;
    PORT
      LAYER met2 ;
        RECT 1224.220000 0.000000 1224.360000 0.485000 ;
    END
  END la_data_in[35]
  PIN la_data_in[34]
    DIRECTION INPUT ;
    USE SIGNAL ;
    PORT
      LAYER met2 ;
        RECT 1206.740000 0.000000 1206.880000 0.485000 ;
    END
  END la_data_in[34]
  PIN la_data_in[33]
    DIRECTION INPUT ;
    USE SIGNAL ;
    PORT
      LAYER met2 ;
        RECT 1189.260000 0.000000 1189.400000 0.485000 ;
    END
  END la_data_in[33]
  PIN la_data_in[32]
    DIRECTION INPUT ;
    USE SIGNAL ;
    PORT
      LAYER met2 ;
        RECT 1171.780000 0.000000 1171.920000 0.485000 ;
    END
  END la_data_in[32]
  PIN la_data_in[31]
    DIRECTION INPUT ;
    USE SIGNAL ;
    PORT
      LAYER met2 ;
        RECT 1154.760000 0.000000 1154.900000 0.485000 ;
    END
  END la_data_in[31]
  PIN la_data_in[30]
    DIRECTION INPUT ;
    USE SIGNAL ;
    PORT
      LAYER met2 ;
        RECT 1137.280000 0.000000 1137.420000 0.485000 ;
    END
  END la_data_in[30]
  PIN la_data_in[29]
    DIRECTION INPUT ;
    USE SIGNAL ;
    PORT
      LAYER met2 ;
        RECT 1119.800000 0.000000 1119.940000 0.485000 ;
    END
  END la_data_in[29]
  PIN la_data_in[28]
    DIRECTION INPUT ;
    USE SIGNAL ;
    PORT
      LAYER met2 ;
        RECT 1102.320000 0.000000 1102.460000 0.485000 ;
    END
  END la_data_in[28]
  PIN la_data_in[27]
    DIRECTION INPUT ;
    USE SIGNAL ;
    PORT
      LAYER met2 ;
        RECT 1084.840000 0.000000 1084.980000 0.485000 ;
    END
  END la_data_in[27]
  PIN la_data_in[26]
    DIRECTION INPUT ;
    USE SIGNAL ;
    PORT
      LAYER met2 ;
        RECT 1067.360000 0.000000 1067.500000 0.485000 ;
    END
  END la_data_in[26]
  PIN la_data_in[25]
    DIRECTION INPUT ;
    USE SIGNAL ;
    PORT
      LAYER met2 ;
        RECT 1050.340000 0.000000 1050.480000 0.485000 ;
    END
  END la_data_in[25]
  PIN la_data_in[24]
    DIRECTION INPUT ;
    USE SIGNAL ;
    PORT
      LAYER met2 ;
        RECT 1032.860000 0.000000 1033.000000 0.485000 ;
    END
  END la_data_in[24]
  PIN la_data_in[23]
    DIRECTION INPUT ;
    USE SIGNAL ;
    PORT
      LAYER met2 ;
        RECT 1015.380000 0.000000 1015.520000 0.485000 ;
    END
  END la_data_in[23]
  PIN la_data_in[22]
    DIRECTION INPUT ;
    USE SIGNAL ;
    PORT
      LAYER met2 ;
        RECT 997.900000 0.000000 998.040000 0.485000 ;
    END
  END la_data_in[22]
  PIN la_data_in[21]
    DIRECTION INPUT ;
    USE SIGNAL ;
    PORT
      LAYER met2 ;
        RECT 980.420000 0.000000 980.560000 0.485000 ;
    END
  END la_data_in[21]
  PIN la_data_in[20]
    DIRECTION INPUT ;
    USE SIGNAL ;
    PORT
      LAYER met2 ;
        RECT 963.400000 0.000000 963.540000 0.485000 ;
    END
  END la_data_in[20]
  PIN la_data_in[19]
    DIRECTION INPUT ;
    USE SIGNAL ;
    PORT
      LAYER met2 ;
        RECT 945.920000 0.000000 946.060000 0.485000 ;
    END
  END la_data_in[19]
  PIN la_data_in[18]
    DIRECTION INPUT ;
    USE SIGNAL ;
    PORT
      LAYER met2 ;
        RECT 928.440000 0.000000 928.580000 0.485000 ;
    END
  END la_data_in[18]
  PIN la_data_in[17]
    DIRECTION INPUT ;
    USE SIGNAL ;
    PORT
      LAYER met2 ;
        RECT 910.960000 0.000000 911.100000 0.485000 ;
    END
  END la_data_in[17]
  PIN la_data_in[16]
    DIRECTION INPUT ;
    USE SIGNAL ;
    PORT
      LAYER met2 ;
        RECT 893.480000 0.000000 893.620000 0.485000 ;
    END
  END la_data_in[16]
  PIN la_data_in[15]
    DIRECTION INPUT ;
    USE SIGNAL ;
    PORT
      LAYER met2 ;
        RECT 876.000000 0.000000 876.140000 0.485000 ;
    END
  END la_data_in[15]
  PIN la_data_in[14]
    DIRECTION INPUT ;
    USE SIGNAL ;
    PORT
      LAYER met2 ;
        RECT 858.980000 0.000000 859.120000 0.485000 ;
    END
  END la_data_in[14]
  PIN la_data_in[13]
    DIRECTION INPUT ;
    USE SIGNAL ;
    PORT
      LAYER met2 ;
        RECT 841.500000 0.000000 841.640000 0.485000 ;
    END
  END la_data_in[13]
  PIN la_data_in[12]
    DIRECTION INPUT ;
    USE SIGNAL ;
    PORT
      LAYER met2 ;
        RECT 824.020000 0.000000 824.160000 0.485000 ;
    END
  END la_data_in[12]
  PIN la_data_in[11]
    DIRECTION INPUT ;
    USE SIGNAL ;
    PORT
      LAYER met2 ;
        RECT 806.540000 0.000000 806.680000 0.485000 ;
    END
  END la_data_in[11]
  PIN la_data_in[10]
    DIRECTION INPUT ;
    USE SIGNAL ;
    PORT
      LAYER met2 ;
        RECT 789.060000 0.000000 789.200000 0.485000 ;
    END
  END la_data_in[10]
  PIN la_data_in[9]
    DIRECTION INPUT ;
    USE SIGNAL ;
    PORT
      LAYER met2 ;
        RECT 771.580000 0.000000 771.720000 0.485000 ;
    END
  END la_data_in[9]
  PIN la_data_in[8]
    DIRECTION INPUT ;
    USE SIGNAL ;
    PORT
      LAYER met2 ;
        RECT 754.560000 0.000000 754.700000 0.485000 ;
    END
  END la_data_in[8]
  PIN la_data_in[7]
    DIRECTION INPUT ;
    USE SIGNAL ;
    PORT
      LAYER met2 ;
        RECT 737.080000 0.000000 737.220000 0.485000 ;
    END
  END la_data_in[7]
  PIN la_data_in[6]
    DIRECTION INPUT ;
    USE SIGNAL ;
    PORT
      LAYER met2 ;
        RECT 719.600000 0.000000 719.740000 0.485000 ;
    END
  END la_data_in[6]
  PIN la_data_in[5]
    DIRECTION INPUT ;
    USE SIGNAL ;
    PORT
      LAYER met2 ;
        RECT 702.120000 0.000000 702.260000 0.485000 ;
    END
  END la_data_in[5]
  PIN la_data_in[4]
    DIRECTION INPUT ;
    USE SIGNAL ;
    PORT
      LAYER met2 ;
        RECT 684.640000 0.000000 684.780000 0.485000 ;
    END
  END la_data_in[4]
  PIN la_data_in[3]
    DIRECTION INPUT ;
    USE SIGNAL ;
    PORT
      LAYER met2 ;
        RECT 667.160000 0.000000 667.300000 0.485000 ;
    END
  END la_data_in[3]
  PIN la_data_in[2]
    DIRECTION INPUT ;
    USE SIGNAL ;
    PORT
      LAYER met2 ;
        RECT 650.140000 0.000000 650.280000 0.485000 ;
    END
  END la_data_in[2]
  PIN la_data_in[1]
    DIRECTION INPUT ;
    USE SIGNAL ;
    PORT
      LAYER met2 ;
        RECT 632.660000 0.000000 632.800000 0.485000 ;
    END
  END la_data_in[1]
  PIN la_data_in[0]
    DIRECTION INPUT ;
    USE SIGNAL ;
    PORT
      LAYER met2 ;
        RECT 615.180000 0.000000 615.320000 0.485000 ;
    END
  END la_data_in[0]
  PIN la_data_out[127]
    DIRECTION OUTPUT ;
    USE SIGNAL ;
    PORT
      LAYER met2 ;
        RECT 2830.540000 0.000000 2830.680000 0.485000 ;
    END
  END la_data_out[127]
  PIN la_data_out[126]
    DIRECTION OUTPUT ;
    USE SIGNAL ;
    PORT
      LAYER met2 ;
        RECT 2813.520000 0.000000 2813.660000 0.485000 ;
    END
  END la_data_out[126]
  PIN la_data_out[125]
    DIRECTION OUTPUT ;
    USE SIGNAL ;
    PORT
      LAYER met2 ;
        RECT 2796.040000 0.000000 2796.180000 0.485000 ;
    END
  END la_data_out[125]
  PIN la_data_out[124]
    DIRECTION OUTPUT ;
    USE SIGNAL ;
    PORT
      LAYER met2 ;
        RECT 2778.560000 0.000000 2778.700000 0.485000 ;
    END
  END la_data_out[124]
  PIN la_data_out[123]
    DIRECTION OUTPUT ;
    USE SIGNAL ;
    PORT
      LAYER met2 ;
        RECT 2761.080000 0.000000 2761.220000 0.485000 ;
    END
  END la_data_out[123]
  PIN la_data_out[122]
    DIRECTION OUTPUT ;
    USE SIGNAL ;
    PORT
      LAYER met2 ;
        RECT 2743.600000 0.000000 2743.740000 0.485000 ;
    END
  END la_data_out[122]
  PIN la_data_out[121]
    DIRECTION OUTPUT ;
    USE SIGNAL ;
    PORT
      LAYER met2 ;
        RECT 2726.580000 0.000000 2726.720000 0.485000 ;
    END
  END la_data_out[121]
  PIN la_data_out[120]
    DIRECTION OUTPUT ;
    USE SIGNAL ;
    PORT
      LAYER met2 ;
        RECT 2709.100000 0.000000 2709.240000 0.485000 ;
    END
  END la_data_out[120]
  PIN la_data_out[119]
    DIRECTION OUTPUT ;
    USE SIGNAL ;
    PORT
      LAYER met2 ;
        RECT 2691.620000 0.000000 2691.760000 0.485000 ;
    END
  END la_data_out[119]
  PIN la_data_out[118]
    DIRECTION OUTPUT ;
    USE SIGNAL ;
    PORT
      LAYER met2 ;
        RECT 2674.140000 0.000000 2674.280000 0.485000 ;
    END
  END la_data_out[118]
  PIN la_data_out[117]
    DIRECTION OUTPUT ;
    USE SIGNAL ;
    PORT
      LAYER met2 ;
        RECT 2656.660000 0.000000 2656.800000 0.485000 ;
    END
  END la_data_out[117]
  PIN la_data_out[116]
    DIRECTION OUTPUT ;
    USE SIGNAL ;
    PORT
      LAYER met2 ;
        RECT 2639.180000 0.000000 2639.320000 0.485000 ;
    END
  END la_data_out[116]
  PIN la_data_out[115]
    DIRECTION OUTPUT ;
    USE SIGNAL ;
    PORT
      LAYER met2 ;
        RECT 2622.160000 0.000000 2622.300000 0.485000 ;
    END
  END la_data_out[115]
  PIN la_data_out[114]
    DIRECTION OUTPUT ;
    USE SIGNAL ;
    PORT
      LAYER met2 ;
        RECT 2604.680000 0.000000 2604.820000 0.485000 ;
    END
  END la_data_out[114]
  PIN la_data_out[113]
    DIRECTION OUTPUT ;
    USE SIGNAL ;
    PORT
      LAYER met2 ;
        RECT 2587.200000 0.000000 2587.340000 0.485000 ;
    END
  END la_data_out[113]
  PIN la_data_out[112]
    DIRECTION OUTPUT ;
    USE SIGNAL ;
    PORT
      LAYER met2 ;
        RECT 2569.720000 0.000000 2569.860000 0.485000 ;
    END
  END la_data_out[112]
  PIN la_data_out[111]
    DIRECTION OUTPUT ;
    USE SIGNAL ;
    PORT
      LAYER met2 ;
        RECT 2552.240000 0.000000 2552.380000 0.485000 ;
    END
  END la_data_out[111]
  PIN la_data_out[110]
    DIRECTION OUTPUT ;
    USE SIGNAL ;
    PORT
      LAYER met2 ;
        RECT 2534.760000 0.000000 2534.900000 0.485000 ;
    END
  END la_data_out[110]
  PIN la_data_out[109]
    DIRECTION OUTPUT ;
    USE SIGNAL ;
    PORT
      LAYER met2 ;
        RECT 2517.740000 0.000000 2517.880000 0.485000 ;
    END
  END la_data_out[109]
  PIN la_data_out[108]
    DIRECTION OUTPUT ;
    USE SIGNAL ;
    PORT
      LAYER met2 ;
        RECT 2500.260000 0.000000 2500.400000 0.485000 ;
    END
  END la_data_out[108]
  PIN la_data_out[107]
    DIRECTION OUTPUT ;
    USE SIGNAL ;
    PORT
      LAYER met2 ;
        RECT 2482.780000 0.000000 2482.920000 0.485000 ;
    END
  END la_data_out[107]
  PIN la_data_out[106]
    DIRECTION OUTPUT ;
    USE SIGNAL ;
    PORT
      LAYER met2 ;
        RECT 2465.300000 0.000000 2465.440000 0.485000 ;
    END
  END la_data_out[106]
  PIN la_data_out[105]
    DIRECTION OUTPUT ;
    USE SIGNAL ;
    PORT
      LAYER met2 ;
        RECT 2447.820000 0.000000 2447.960000 0.485000 ;
    END
  END la_data_out[105]
  PIN la_data_out[104]
    DIRECTION OUTPUT ;
    USE SIGNAL ;
    PORT
      LAYER met2 ;
        RECT 2430.340000 0.000000 2430.480000 0.485000 ;
    END
  END la_data_out[104]
  PIN la_data_out[103]
    DIRECTION OUTPUT ;
    USE SIGNAL ;
    PORT
      LAYER met2 ;
        RECT 2413.320000 0.000000 2413.460000 0.485000 ;
    END
  END la_data_out[103]
  PIN la_data_out[102]
    DIRECTION OUTPUT ;
    USE SIGNAL ;
    PORT
      LAYER met2 ;
        RECT 2395.840000 0.000000 2395.980000 0.485000 ;
    END
  END la_data_out[102]
  PIN la_data_out[101]
    DIRECTION OUTPUT ;
    USE SIGNAL ;
    PORT
      LAYER met2 ;
        RECT 2378.360000 0.000000 2378.500000 0.485000 ;
    END
  END la_data_out[101]
  PIN la_data_out[100]
    DIRECTION OUTPUT ;
    USE SIGNAL ;
    PORT
      LAYER met2 ;
        RECT 2360.880000 0.000000 2361.020000 0.485000 ;
    END
  END la_data_out[100]
  PIN la_data_out[99]
    DIRECTION OUTPUT ;
    USE SIGNAL ;
    PORT
      LAYER met2 ;
        RECT 2343.400000 0.000000 2343.540000 0.485000 ;
    END
  END la_data_out[99]
  PIN la_data_out[98]
    DIRECTION OUTPUT ;
    USE SIGNAL ;
    PORT
      LAYER met2 ;
        RECT 2326.380000 0.000000 2326.520000 0.485000 ;
    END
  END la_data_out[98]
  PIN la_data_out[97]
    DIRECTION OUTPUT ;
    USE SIGNAL ;
    PORT
      LAYER met2 ;
        RECT 2308.900000 0.000000 2309.040000 0.485000 ;
    END
  END la_data_out[97]
  PIN la_data_out[96]
    DIRECTION OUTPUT ;
    USE SIGNAL ;
    PORT
      LAYER met2 ;
        RECT 2291.420000 0.000000 2291.560000 0.485000 ;
    END
  END la_data_out[96]
  PIN la_data_out[95]
    DIRECTION OUTPUT ;
    USE SIGNAL ;
    PORT
      LAYER met2 ;
        RECT 2273.940000 0.000000 2274.080000 0.485000 ;
    END
  END la_data_out[95]
  PIN la_data_out[94]
    DIRECTION OUTPUT ;
    USE SIGNAL ;
    PORT
      LAYER met2 ;
        RECT 2256.460000 0.000000 2256.600000 0.485000 ;
    END
  END la_data_out[94]
  PIN la_data_out[93]
    DIRECTION OUTPUT ;
    USE SIGNAL ;
    PORT
      LAYER met2 ;
        RECT 2238.980000 0.000000 2239.120000 0.485000 ;
    END
  END la_data_out[93]
  PIN la_data_out[92]
    DIRECTION OUTPUT ;
    USE SIGNAL ;
    PORT
      LAYER met2 ;
        RECT 2221.960000 0.000000 2222.100000 0.485000 ;
    END
  END la_data_out[92]
  PIN la_data_out[91]
    DIRECTION OUTPUT ;
    USE SIGNAL ;
    PORT
      LAYER met2 ;
        RECT 2204.480000 0.000000 2204.620000 0.485000 ;
    END
  END la_data_out[91]
  PIN la_data_out[90]
    DIRECTION OUTPUT ;
    USE SIGNAL ;
    PORT
      LAYER met2 ;
        RECT 2187.000000 0.000000 2187.140000 0.485000 ;
    END
  END la_data_out[90]
  PIN la_data_out[89]
    DIRECTION OUTPUT ;
    USE SIGNAL ;
    PORT
      LAYER met2 ;
        RECT 2169.520000 0.000000 2169.660000 0.485000 ;
    END
  END la_data_out[89]
  PIN la_data_out[88]
    DIRECTION OUTPUT ;
    USE SIGNAL ;
    PORT
      LAYER met2 ;
        RECT 2152.040000 0.000000 2152.180000 0.485000 ;
    END
  END la_data_out[88]
  PIN la_data_out[87]
    DIRECTION OUTPUT ;
    USE SIGNAL ;
    PORT
      LAYER met2 ;
        RECT 2134.560000 0.000000 2134.700000 0.485000 ;
    END
  END la_data_out[87]
  PIN la_data_out[86]
    DIRECTION OUTPUT ;
    USE SIGNAL ;
    PORT
      LAYER met2 ;
        RECT 2117.540000 0.000000 2117.680000 0.485000 ;
    END
  END la_data_out[86]
  PIN la_data_out[85]
    DIRECTION OUTPUT ;
    USE SIGNAL ;
    PORT
      LAYER met2 ;
        RECT 2100.060000 0.000000 2100.200000 0.485000 ;
    END
  END la_data_out[85]
  PIN la_data_out[84]
    DIRECTION OUTPUT ;
    USE SIGNAL ;
    PORT
      LAYER met2 ;
        RECT 2082.580000 0.000000 2082.720000 0.485000 ;
    END
  END la_data_out[84]
  PIN la_data_out[83]
    DIRECTION OUTPUT ;
    USE SIGNAL ;
    PORT
      LAYER met2 ;
        RECT 2065.100000 0.000000 2065.240000 0.485000 ;
    END
  END la_data_out[83]
  PIN la_data_out[82]
    DIRECTION OUTPUT ;
    USE SIGNAL ;
    PORT
      LAYER met2 ;
        RECT 2047.620000 0.000000 2047.760000 0.485000 ;
    END
  END la_data_out[82]
  PIN la_data_out[81]
    DIRECTION OUTPUT ;
    USE SIGNAL ;
    PORT
      LAYER met2 ;
        RECT 2030.140000 0.000000 2030.280000 0.485000 ;
    END
  END la_data_out[81]
  PIN la_data_out[80]
    DIRECTION OUTPUT ;
    USE SIGNAL ;
    PORT
      LAYER met2 ;
        RECT 2013.120000 0.000000 2013.260000 0.485000 ;
    END
  END la_data_out[80]
  PIN la_data_out[79]
    DIRECTION OUTPUT ;
    USE SIGNAL ;
    PORT
      LAYER met2 ;
        RECT 1995.640000 0.000000 1995.780000 0.485000 ;
    END
  END la_data_out[79]
  PIN la_data_out[78]
    DIRECTION OUTPUT ;
    USE SIGNAL ;
    PORT
      LAYER met2 ;
        RECT 1978.160000 0.000000 1978.300000 0.485000 ;
    END
  END la_data_out[78]
  PIN la_data_out[77]
    DIRECTION OUTPUT ;
    USE SIGNAL ;
    PORT
      LAYER met2 ;
        RECT 1960.680000 0.000000 1960.820000 0.485000 ;
    END
  END la_data_out[77]
  PIN la_data_out[76]
    DIRECTION OUTPUT ;
    USE SIGNAL ;
    PORT
      LAYER met2 ;
        RECT 1943.200000 0.000000 1943.340000 0.485000 ;
    END
  END la_data_out[76]
  PIN la_data_out[75]
    DIRECTION OUTPUT ;
    USE SIGNAL ;
    PORT
      LAYER met2 ;
        RECT 1926.180000 0.000000 1926.320000 0.485000 ;
    END
  END la_data_out[75]
  PIN la_data_out[74]
    DIRECTION OUTPUT ;
    USE SIGNAL ;
    PORT
      LAYER met2 ;
        RECT 1908.700000 0.000000 1908.840000 0.485000 ;
    END
  END la_data_out[74]
  PIN la_data_out[73]
    DIRECTION OUTPUT ;
    USE SIGNAL ;
    PORT
      LAYER met2 ;
        RECT 1891.220000 0.000000 1891.360000 0.485000 ;
    END
  END la_data_out[73]
  PIN la_data_out[72]
    DIRECTION OUTPUT ;
    USE SIGNAL ;
    PORT
      LAYER met2 ;
        RECT 1873.740000 0.000000 1873.880000 0.485000 ;
    END
  END la_data_out[72]
  PIN la_data_out[71]
    DIRECTION OUTPUT ;
    USE SIGNAL ;
    PORT
      LAYER met2 ;
        RECT 1856.260000 0.000000 1856.400000 0.485000 ;
    END
  END la_data_out[71]
  PIN la_data_out[70]
    DIRECTION OUTPUT ;
    USE SIGNAL ;
    PORT
      LAYER met2 ;
        RECT 1838.780000 0.000000 1838.920000 0.485000 ;
    END
  END la_data_out[70]
  PIN la_data_out[69]
    DIRECTION OUTPUT ;
    USE SIGNAL ;
    PORT
      LAYER met2 ;
        RECT 1821.760000 0.000000 1821.900000 0.485000 ;
    END
  END la_data_out[69]
  PIN la_data_out[68]
    DIRECTION OUTPUT ;
    USE SIGNAL ;
    PORT
      LAYER met2 ;
        RECT 1804.280000 0.000000 1804.420000 0.485000 ;
    END
  END la_data_out[68]
  PIN la_data_out[67]
    DIRECTION OUTPUT ;
    USE SIGNAL ;
    PORT
      LAYER met2 ;
        RECT 1786.800000 0.000000 1786.940000 0.485000 ;
    END
  END la_data_out[67]
  PIN la_data_out[66]
    DIRECTION OUTPUT ;
    USE SIGNAL ;
    PORT
      LAYER met2 ;
        RECT 1769.320000 0.000000 1769.460000 0.485000 ;
    END
  END la_data_out[66]
  PIN la_data_out[65]
    DIRECTION OUTPUT ;
    USE SIGNAL ;
    PORT
      LAYER met2 ;
        RECT 1751.840000 0.000000 1751.980000 0.485000 ;
    END
  END la_data_out[65]
  PIN la_data_out[64]
    DIRECTION OUTPUT ;
    USE SIGNAL ;
    PORT
      LAYER met2 ;
        RECT 1734.360000 0.000000 1734.500000 0.485000 ;
    END
  END la_data_out[64]
  PIN la_data_out[63]
    DIRECTION OUTPUT ;
    USE SIGNAL ;
    PORT
      LAYER met2 ;
        RECT 1717.340000 0.000000 1717.480000 0.485000 ;
    END
  END la_data_out[63]
  PIN la_data_out[62]
    DIRECTION OUTPUT ;
    USE SIGNAL ;
    PORT
      LAYER met2 ;
        RECT 1699.860000 0.000000 1700.000000 0.485000 ;
    END
  END la_data_out[62]
  PIN la_data_out[61]
    DIRECTION OUTPUT ;
    USE SIGNAL ;
    PORT
      LAYER met2 ;
        RECT 1682.380000 0.000000 1682.520000 0.485000 ;
    END
  END la_data_out[61]
  PIN la_data_out[60]
    DIRECTION OUTPUT ;
    USE SIGNAL ;
    PORT
      LAYER met2 ;
        RECT 1664.900000 0.000000 1665.040000 0.485000 ;
    END
  END la_data_out[60]
  PIN la_data_out[59]
    DIRECTION OUTPUT ;
    USE SIGNAL ;
    PORT
      LAYER met2 ;
        RECT 1647.420000 0.000000 1647.560000 0.485000 ;
    END
  END la_data_out[59]
  PIN la_data_out[58]
    DIRECTION OUTPUT ;
    USE SIGNAL ;
    PORT
      LAYER met2 ;
        RECT 1629.940000 0.000000 1630.080000 0.485000 ;
    END
  END la_data_out[58]
  PIN la_data_out[57]
    DIRECTION OUTPUT ;
    USE SIGNAL ;
    PORT
      LAYER met2 ;
        RECT 1612.920000 0.000000 1613.060000 0.485000 ;
    END
  END la_data_out[57]
  PIN la_data_out[56]
    DIRECTION OUTPUT ;
    USE SIGNAL ;
    PORT
      LAYER met2 ;
        RECT 1595.440000 0.000000 1595.580000 0.485000 ;
    END
  END la_data_out[56]
  PIN la_data_out[55]
    DIRECTION OUTPUT ;
    USE SIGNAL ;
    PORT
      LAYER met2 ;
        RECT 1577.960000 0.000000 1578.100000 0.485000 ;
    END
  END la_data_out[55]
  PIN la_data_out[54]
    DIRECTION OUTPUT ;
    USE SIGNAL ;
    PORT
      LAYER met2 ;
        RECT 1560.480000 0.000000 1560.620000 0.485000 ;
    END
  END la_data_out[54]
  PIN la_data_out[53]
    DIRECTION OUTPUT ;
    USE SIGNAL ;
    PORT
      LAYER met2 ;
        RECT 1543.000000 0.000000 1543.140000 0.485000 ;
    END
  END la_data_out[53]
  PIN la_data_out[52]
    DIRECTION OUTPUT ;
    USE SIGNAL ;
    PORT
      LAYER met2 ;
        RECT 1525.980000 0.000000 1526.120000 0.485000 ;
    END
  END la_data_out[52]
  PIN la_data_out[51]
    DIRECTION OUTPUT ;
    USE SIGNAL ;
    PORT
      LAYER met2 ;
        RECT 1508.500000 0.000000 1508.640000 0.485000 ;
    END
  END la_data_out[51]
  PIN la_data_out[50]
    DIRECTION OUTPUT ;
    USE SIGNAL ;
    PORT
      LAYER met2 ;
        RECT 1491.020000 0.000000 1491.160000 0.485000 ;
    END
  END la_data_out[50]
  PIN la_data_out[49]
    DIRECTION OUTPUT ;
    USE SIGNAL ;
    PORT
      LAYER met2 ;
        RECT 1473.540000 0.000000 1473.680000 0.485000 ;
    END
  END la_data_out[49]
  PIN la_data_out[48]
    DIRECTION OUTPUT ;
    USE SIGNAL ;
    PORT
      LAYER met2 ;
        RECT 1456.060000 0.000000 1456.200000 0.485000 ;
    END
  END la_data_out[48]
  PIN la_data_out[47]
    DIRECTION OUTPUT ;
    USE SIGNAL ;
    PORT
      LAYER met2 ;
        RECT 1438.580000 0.000000 1438.720000 0.485000 ;
    END
  END la_data_out[47]
  PIN la_data_out[46]
    DIRECTION OUTPUT ;
    USE SIGNAL ;
    PORT
      LAYER met2 ;
        RECT 1421.560000 0.000000 1421.700000 0.485000 ;
    END
  END la_data_out[46]
  PIN la_data_out[45]
    DIRECTION OUTPUT ;
    USE SIGNAL ;
    PORT
      LAYER met2 ;
        RECT 1404.080000 0.000000 1404.220000 0.485000 ;
    END
  END la_data_out[45]
  PIN la_data_out[44]
    DIRECTION OUTPUT ;
    USE SIGNAL ;
    PORT
      LAYER met2 ;
        RECT 1386.600000 0.000000 1386.740000 0.485000 ;
    END
  END la_data_out[44]
  PIN la_data_out[43]
    DIRECTION OUTPUT ;
    USE SIGNAL ;
    PORT
      LAYER met2 ;
        RECT 1369.120000 0.000000 1369.260000 0.485000 ;
    END
  END la_data_out[43]
  PIN la_data_out[42]
    DIRECTION OUTPUT ;
    USE SIGNAL ;
    PORT
      LAYER met2 ;
        RECT 1351.640000 0.000000 1351.780000 0.485000 ;
    END
  END la_data_out[42]
  PIN la_data_out[41]
    DIRECTION OUTPUT ;
    USE SIGNAL ;
    PORT
      LAYER met2 ;
        RECT 1334.160000 0.000000 1334.300000 0.485000 ;
    END
  END la_data_out[41]
  PIN la_data_out[40]
    DIRECTION OUTPUT ;
    USE SIGNAL ;
    PORT
      LAYER met2 ;
        RECT 1317.140000 0.000000 1317.280000 0.485000 ;
    END
  END la_data_out[40]
  PIN la_data_out[39]
    DIRECTION OUTPUT ;
    USE SIGNAL ;
    PORT
      LAYER met2 ;
        RECT 1299.660000 0.000000 1299.800000 0.485000 ;
    END
  END la_data_out[39]
  PIN la_data_out[38]
    DIRECTION OUTPUT ;
    USE SIGNAL ;
    PORT
      LAYER met2 ;
        RECT 1282.180000 0.000000 1282.320000 0.485000 ;
    END
  END la_data_out[38]
  PIN la_data_out[37]
    DIRECTION OUTPUT ;
    USE SIGNAL ;
    PORT
      LAYER met2 ;
        RECT 1264.700000 0.000000 1264.840000 0.485000 ;
    END
  END la_data_out[37]
  PIN la_data_out[36]
    DIRECTION OUTPUT ;
    USE SIGNAL ;
    PORT
      LAYER met2 ;
        RECT 1247.220000 0.000000 1247.360000 0.485000 ;
    END
  END la_data_out[36]
  PIN la_data_out[35]
    DIRECTION OUTPUT ;
    USE SIGNAL ;
    PORT
      LAYER met2 ;
        RECT 1230.200000 0.000000 1230.340000 0.485000 ;
    END
  END la_data_out[35]
  PIN la_data_out[34]
    DIRECTION OUTPUT ;
    USE SIGNAL ;
    PORT
      LAYER met2 ;
        RECT 1212.720000 0.000000 1212.860000 0.485000 ;
    END
  END la_data_out[34]
  PIN la_data_out[33]
    DIRECTION OUTPUT ;
    USE SIGNAL ;
    PORT
      LAYER met2 ;
        RECT 1195.240000 0.000000 1195.380000 0.485000 ;
    END
  END la_data_out[33]
  PIN la_data_out[32]
    DIRECTION OUTPUT ;
    USE SIGNAL ;
    PORT
      LAYER met2 ;
        RECT 1177.760000 0.000000 1177.900000 0.485000 ;
    END
  END la_data_out[32]
  PIN la_data_out[31]
    DIRECTION OUTPUT ;
    USE SIGNAL ;
    PORT
      LAYER met2 ;
        RECT 1160.280000 0.000000 1160.420000 0.485000 ;
    END
  END la_data_out[31]
  PIN la_data_out[30]
    DIRECTION OUTPUT ;
    USE SIGNAL ;
    PORT
      LAYER met2 ;
        RECT 1142.800000 0.000000 1142.940000 0.485000 ;
    END
  END la_data_out[30]
  PIN la_data_out[29]
    DIRECTION OUTPUT ;
    USE SIGNAL ;
    PORT
      LAYER met2 ;
        RECT 1125.780000 0.000000 1125.920000 0.485000 ;
    END
  END la_data_out[29]
  PIN la_data_out[28]
    DIRECTION OUTPUT ;
    USE SIGNAL ;
    PORT
      LAYER met2 ;
        RECT 1108.300000 0.000000 1108.440000 0.485000 ;
    END
  END la_data_out[28]
  PIN la_data_out[27]
    DIRECTION OUTPUT ;
    USE SIGNAL ;
    PORT
      LAYER met2 ;
        RECT 1090.820000 0.000000 1090.960000 0.485000 ;
    END
  END la_data_out[27]
  PIN la_data_out[26]
    DIRECTION OUTPUT ;
    USE SIGNAL ;
    PORT
      LAYER met2 ;
        RECT 1073.340000 0.000000 1073.480000 0.485000 ;
    END
  END la_data_out[26]
  PIN la_data_out[25]
    DIRECTION OUTPUT ;
    USE SIGNAL ;
    PORT
      LAYER met2 ;
        RECT 1055.860000 0.000000 1056.000000 0.485000 ;
    END
  END la_data_out[25]
  PIN la_data_out[24]
    DIRECTION OUTPUT ;
    USE SIGNAL ;
    PORT
      LAYER met2 ;
        RECT 1038.380000 0.000000 1038.520000 0.485000 ;
    END
  END la_data_out[24]
  PIN la_data_out[23]
    DIRECTION OUTPUT ;
    USE SIGNAL ;
    PORT
      LAYER met2 ;
        RECT 1021.360000 0.000000 1021.500000 0.485000 ;
    END
  END la_data_out[23]
  PIN la_data_out[22]
    DIRECTION OUTPUT ;
    USE SIGNAL ;
    PORT
      LAYER met2 ;
        RECT 1003.880000 0.000000 1004.020000 0.485000 ;
    END
  END la_data_out[22]
  PIN la_data_out[21]
    DIRECTION OUTPUT ;
    USE SIGNAL ;
    PORT
      LAYER met2 ;
        RECT 986.400000 0.000000 986.540000 0.485000 ;
    END
  END la_data_out[21]
  PIN la_data_out[20]
    DIRECTION OUTPUT ;
    USE SIGNAL ;
    PORT
      LAYER met2 ;
        RECT 968.920000 0.000000 969.060000 0.485000 ;
    END
  END la_data_out[20]
  PIN la_data_out[19]
    DIRECTION OUTPUT ;
    USE SIGNAL ;
    PORT
      LAYER met2 ;
        RECT 951.440000 0.000000 951.580000 0.485000 ;
    END
  END la_data_out[19]
  PIN la_data_out[18]
    DIRECTION OUTPUT ;
    USE SIGNAL ;
    PORT
      LAYER met2 ;
        RECT 933.960000 0.000000 934.100000 0.485000 ;
    END
  END la_data_out[18]
  PIN la_data_out[17]
    DIRECTION OUTPUT ;
    USE SIGNAL ;
    PORT
      LAYER met2 ;
        RECT 916.940000 0.000000 917.080000 0.485000 ;
    END
  END la_data_out[17]
  PIN la_data_out[16]
    DIRECTION OUTPUT ;
    USE SIGNAL ;
    PORT
      LAYER met2 ;
        RECT 899.460000 0.000000 899.600000 0.485000 ;
    END
  END la_data_out[16]
  PIN la_data_out[15]
    DIRECTION OUTPUT ;
    USE SIGNAL ;
    PORT
      LAYER met2 ;
        RECT 881.980000 0.000000 882.120000 0.485000 ;
    END
  END la_data_out[15]
  PIN la_data_out[14]
    DIRECTION OUTPUT ;
    USE SIGNAL ;
    PORT
      LAYER met2 ;
        RECT 864.500000 0.000000 864.640000 0.485000 ;
    END
  END la_data_out[14]
  PIN la_data_out[13]
    DIRECTION OUTPUT ;
    USE SIGNAL ;
    PORT
      LAYER met2 ;
        RECT 847.020000 0.000000 847.160000 0.485000 ;
    END
  END la_data_out[13]
  PIN la_data_out[12]
    DIRECTION OUTPUT ;
    USE SIGNAL ;
    PORT
      LAYER met2 ;
        RECT 830.000000 0.000000 830.140000 0.485000 ;
    END
  END la_data_out[12]
  PIN la_data_out[11]
    DIRECTION OUTPUT ;
    USE SIGNAL ;
    PORT
      LAYER met2 ;
        RECT 812.520000 0.000000 812.660000 0.485000 ;
    END
  END la_data_out[11]
  PIN la_data_out[10]
    DIRECTION OUTPUT ;
    USE SIGNAL ;
    PORT
      LAYER met2 ;
        RECT 795.040000 0.000000 795.180000 0.485000 ;
    END
  END la_data_out[10]
  PIN la_data_out[9]
    DIRECTION OUTPUT ;
    USE SIGNAL ;
    PORT
      LAYER met2 ;
        RECT 777.560000 0.000000 777.700000 0.485000 ;
    END
  END la_data_out[9]
  PIN la_data_out[8]
    DIRECTION OUTPUT ;
    USE SIGNAL ;
    PORT
      LAYER met2 ;
        RECT 760.080000 0.000000 760.220000 0.485000 ;
    END
  END la_data_out[8]
  PIN la_data_out[7]
    DIRECTION OUTPUT ;
    USE SIGNAL ;
    PORT
      LAYER met2 ;
        RECT 742.600000 0.000000 742.740000 0.485000 ;
    END
  END la_data_out[7]
  PIN la_data_out[6]
    DIRECTION OUTPUT ;
    USE SIGNAL ;
    PORT
      LAYER met2 ;
        RECT 725.580000 0.000000 725.720000 0.485000 ;
    END
  END la_data_out[6]
  PIN la_data_out[5]
    DIRECTION OUTPUT ;
    USE SIGNAL ;
    PORT
      LAYER met2 ;
        RECT 708.100000 0.000000 708.240000 0.485000 ;
    END
  END la_data_out[5]
  PIN la_data_out[4]
    DIRECTION OUTPUT ;
    USE SIGNAL ;
    PORT
      LAYER met2 ;
        RECT 690.620000 0.000000 690.760000 0.485000 ;
    END
  END la_data_out[4]
  PIN la_data_out[3]
    DIRECTION OUTPUT ;
    USE SIGNAL ;
    PORT
      LAYER met2 ;
        RECT 673.140000 0.000000 673.280000 0.485000 ;
    END
  END la_data_out[3]
  PIN la_data_out[2]
    DIRECTION OUTPUT ;
    USE SIGNAL ;
    PORT
      LAYER met2 ;
        RECT 655.660000 0.000000 655.800000 0.485000 ;
    END
  END la_data_out[2]
  PIN la_data_out[1]
    DIRECTION OUTPUT ;
    USE SIGNAL ;
    PORT
      LAYER met2 ;
        RECT 638.180000 0.000000 638.320000 0.485000 ;
    END
  END la_data_out[1]
  PIN la_data_out[0]
    DIRECTION OUTPUT ;
    USE SIGNAL ;
    PORT
      LAYER met2 ;
        RECT 621.160000 0.000000 621.300000 0.485000 ;
    END
  END la_data_out[0]
  PIN la_oenb[127]
    DIRECTION INPUT ;
    USE SIGNAL ;
    PORT
      LAYER met2 ;
        RECT 2836.520000 0.000000 2836.660000 0.485000 ;
    END
  END la_oenb[127]
  PIN la_oenb[126]
    DIRECTION INPUT ;
    USE SIGNAL ;
    PORT
      LAYER met2 ;
        RECT 2819.040000 0.000000 2819.180000 0.485000 ;
    END
  END la_oenb[126]
  PIN la_oenb[125]
    DIRECTION INPUT ;
    USE SIGNAL ;
    PORT
      LAYER met2 ;
        RECT 2801.560000 0.000000 2801.700000 0.485000 ;
    END
  END la_oenb[125]
  PIN la_oenb[124]
    DIRECTION INPUT ;
    USE SIGNAL ;
    PORT
      LAYER met2 ;
        RECT 2784.540000 0.000000 2784.680000 0.485000 ;
    END
  END la_oenb[124]
  PIN la_oenb[123]
    DIRECTION INPUT ;
    USE SIGNAL ;
    PORT
      LAYER met2 ;
        RECT 2767.060000 0.000000 2767.200000 0.485000 ;
    END
  END la_oenb[123]
  PIN la_oenb[122]
    DIRECTION INPUT ;
    USE SIGNAL ;
    PORT
      LAYER met2 ;
        RECT 2749.580000 0.000000 2749.720000 0.485000 ;
    END
  END la_oenb[122]
  PIN la_oenb[121]
    DIRECTION INPUT ;
    USE SIGNAL ;
    PORT
      LAYER met2 ;
        RECT 2732.100000 0.000000 2732.240000 0.485000 ;
    END
  END la_oenb[121]
  PIN la_oenb[120]
    DIRECTION INPUT ;
    USE SIGNAL ;
    PORT
      LAYER met2 ;
        RECT 2714.620000 0.000000 2714.760000 0.485000 ;
    END
  END la_oenb[120]
  PIN la_oenb[119]
    DIRECTION INPUT ;
    USE SIGNAL ;
    PORT
      LAYER met2 ;
        RECT 2697.140000 0.000000 2697.280000 0.485000 ;
    END
  END la_oenb[119]
  PIN la_oenb[118]
    DIRECTION INPUT ;
    USE SIGNAL ;
    PORT
      LAYER met2 ;
        RECT 2680.120000 0.000000 2680.260000 0.485000 ;
    END
  END la_oenb[118]
  PIN la_oenb[117]
    DIRECTION INPUT ;
    USE SIGNAL ;
    PORT
      LAYER met2 ;
        RECT 2662.640000 0.000000 2662.780000 0.485000 ;
    END
  END la_oenb[117]
  PIN la_oenb[116]
    DIRECTION INPUT ;
    USE SIGNAL ;
    PORT
      LAYER met2 ;
        RECT 2645.160000 0.000000 2645.300000 0.485000 ;
    END
  END la_oenb[116]
  PIN la_oenb[115]
    DIRECTION INPUT ;
    USE SIGNAL ;
    PORT
      LAYER met2 ;
        RECT 2627.680000 0.000000 2627.820000 0.485000 ;
    END
  END la_oenb[115]
  PIN la_oenb[114]
    DIRECTION INPUT ;
    USE SIGNAL ;
    PORT
      LAYER met2 ;
        RECT 2610.200000 0.000000 2610.340000 0.485000 ;
    END
  END la_oenb[114]
  PIN la_oenb[113]
    DIRECTION INPUT ;
    USE SIGNAL ;
    PORT
      LAYER met2 ;
        RECT 2593.180000 0.000000 2593.320000 0.485000 ;
    END
  END la_oenb[113]
  PIN la_oenb[112]
    DIRECTION INPUT ;
    USE SIGNAL ;
    PORT
      LAYER met2 ;
        RECT 2575.700000 0.000000 2575.840000 0.485000 ;
    END
  END la_oenb[112]
  PIN la_oenb[111]
    DIRECTION INPUT ;
    USE SIGNAL ;
    PORT
      LAYER met2 ;
        RECT 2558.220000 0.000000 2558.360000 0.485000 ;
    END
  END la_oenb[111]
  PIN la_oenb[110]
    DIRECTION INPUT ;
    USE SIGNAL ;
    PORT
      LAYER met2 ;
        RECT 2540.740000 0.000000 2540.880000 0.485000 ;
    END
  END la_oenb[110]
  PIN la_oenb[109]
    DIRECTION INPUT ;
    USE SIGNAL ;
    PORT
      LAYER met2 ;
        RECT 2523.260000 0.000000 2523.400000 0.485000 ;
    END
  END la_oenb[109]
  PIN la_oenb[108]
    DIRECTION INPUT ;
    USE SIGNAL ;
    PORT
      LAYER met2 ;
        RECT 2505.780000 0.000000 2505.920000 0.485000 ;
    END
  END la_oenb[108]
  PIN la_oenb[107]
    DIRECTION INPUT ;
    USE SIGNAL ;
    PORT
      LAYER met2 ;
        RECT 2488.760000 0.000000 2488.900000 0.485000 ;
    END
  END la_oenb[107]
  PIN la_oenb[106]
    DIRECTION INPUT ;
    USE SIGNAL ;
    PORT
      LAYER met2 ;
        RECT 2471.280000 0.000000 2471.420000 0.485000 ;
    END
  END la_oenb[106]
  PIN la_oenb[105]
    DIRECTION INPUT ;
    USE SIGNAL ;
    PORT
      LAYER met2 ;
        RECT 2453.800000 0.000000 2453.940000 0.485000 ;
    END
  END la_oenb[105]
  PIN la_oenb[104]
    DIRECTION INPUT ;
    USE SIGNAL ;
    PORT
      LAYER met2 ;
        RECT 2436.320000 0.000000 2436.460000 0.485000 ;
    END
  END la_oenb[104]
  PIN la_oenb[103]
    DIRECTION INPUT ;
    USE SIGNAL ;
    PORT
      LAYER met2 ;
        RECT 2418.840000 0.000000 2418.980000 0.485000 ;
    END
  END la_oenb[103]
  PIN la_oenb[102]
    DIRECTION INPUT ;
    USE SIGNAL ;
    PORT
      LAYER met2 ;
        RECT 2401.360000 0.000000 2401.500000 0.485000 ;
    END
  END la_oenb[102]
  PIN la_oenb[101]
    DIRECTION INPUT ;
    USE SIGNAL ;
    PORT
      LAYER met2 ;
        RECT 2384.340000 0.000000 2384.480000 0.485000 ;
    END
  END la_oenb[101]
  PIN la_oenb[100]
    DIRECTION INPUT ;
    USE SIGNAL ;
    PORT
      LAYER met2 ;
        RECT 2366.860000 0.000000 2367.000000 0.485000 ;
    END
  END la_oenb[100]
  PIN la_oenb[99]
    DIRECTION INPUT ;
    USE SIGNAL ;
    PORT
      LAYER met2 ;
        RECT 2349.380000 0.000000 2349.520000 0.485000 ;
    END
  END la_oenb[99]
  PIN la_oenb[98]
    DIRECTION INPUT ;
    USE SIGNAL ;
    PORT
      LAYER met2 ;
        RECT 2331.900000 0.000000 2332.040000 0.485000 ;
    END
  END la_oenb[98]
  PIN la_oenb[97]
    DIRECTION INPUT ;
    USE SIGNAL ;
    PORT
      LAYER met2 ;
        RECT 2314.420000 0.000000 2314.560000 0.485000 ;
    END
  END la_oenb[97]
  PIN la_oenb[96]
    DIRECTION INPUT ;
    USE SIGNAL ;
    PORT
      LAYER met2 ;
        RECT 2296.940000 0.000000 2297.080000 0.485000 ;
    END
  END la_oenb[96]
  PIN la_oenb[95]
    DIRECTION INPUT ;
    USE SIGNAL ;
    PORT
      LAYER met2 ;
        RECT 2279.920000 0.000000 2280.060000 0.485000 ;
    END
  END la_oenb[95]
  PIN la_oenb[94]
    DIRECTION INPUT ;
    USE SIGNAL ;
    PORT
      LAYER met2 ;
        RECT 2262.440000 0.000000 2262.580000 0.485000 ;
    END
  END la_oenb[94]
  PIN la_oenb[93]
    DIRECTION INPUT ;
    USE SIGNAL ;
    PORT
      LAYER met2 ;
        RECT 2244.960000 0.000000 2245.100000 0.485000 ;
    END
  END la_oenb[93]
  PIN la_oenb[92]
    DIRECTION INPUT ;
    USE SIGNAL ;
    PORT
      LAYER met2 ;
        RECT 2227.480000 0.000000 2227.620000 0.485000 ;
    END
  END la_oenb[92]
  PIN la_oenb[91]
    DIRECTION INPUT ;
    USE SIGNAL ;
    PORT
      LAYER met2 ;
        RECT 2210.000000 0.000000 2210.140000 0.485000 ;
    END
  END la_oenb[91]
  PIN la_oenb[90]
    DIRECTION INPUT ;
    USE SIGNAL ;
    PORT
      LAYER met2 ;
        RECT 2192.980000 0.000000 2193.120000 0.485000 ;
    END
  END la_oenb[90]
  PIN la_oenb[89]
    DIRECTION INPUT ;
    USE SIGNAL ;
    PORT
      LAYER met2 ;
        RECT 2175.500000 0.000000 2175.640000 0.485000 ;
    END
  END la_oenb[89]
  PIN la_oenb[88]
    DIRECTION INPUT ;
    USE SIGNAL ;
    PORT
      LAYER met2 ;
        RECT 2158.020000 0.000000 2158.160000 0.485000 ;
    END
  END la_oenb[88]
  PIN la_oenb[87]
    DIRECTION INPUT ;
    USE SIGNAL ;
    PORT
      LAYER met2 ;
        RECT 2140.540000 0.000000 2140.680000 0.485000 ;
    END
  END la_oenb[87]
  PIN la_oenb[86]
    DIRECTION INPUT ;
    USE SIGNAL ;
    PORT
      LAYER met2 ;
        RECT 2123.060000 0.000000 2123.200000 0.485000 ;
    END
  END la_oenb[86]
  PIN la_oenb[85]
    DIRECTION INPUT ;
    USE SIGNAL ;
    PORT
      LAYER met2 ;
        RECT 2105.580000 0.000000 2105.720000 0.485000 ;
    END
  END la_oenb[85]
  PIN la_oenb[84]
    DIRECTION INPUT ;
    USE SIGNAL ;
    PORT
      LAYER met2 ;
        RECT 2088.560000 0.000000 2088.700000 0.485000 ;
    END
  END la_oenb[84]
  PIN la_oenb[83]
    DIRECTION INPUT ;
    USE SIGNAL ;
    PORT
      LAYER met2 ;
        RECT 2071.080000 0.000000 2071.220000 0.485000 ;
    END
  END la_oenb[83]
  PIN la_oenb[82]
    DIRECTION INPUT ;
    USE SIGNAL ;
    PORT
      LAYER met2 ;
        RECT 2053.600000 0.000000 2053.740000 0.485000 ;
    END
  END la_oenb[82]
  PIN la_oenb[81]
    DIRECTION INPUT ;
    USE SIGNAL ;
    PORT
      LAYER met2 ;
        RECT 2036.120000 0.000000 2036.260000 0.485000 ;
    END
  END la_oenb[81]
  PIN la_oenb[80]
    DIRECTION INPUT ;
    USE SIGNAL ;
    PORT
      LAYER met2 ;
        RECT 2018.640000 0.000000 2018.780000 0.485000 ;
    END
  END la_oenb[80]
  PIN la_oenb[79]
    DIRECTION INPUT ;
    USE SIGNAL ;
    PORT
      LAYER met2 ;
        RECT 2001.160000 0.000000 2001.300000 0.485000 ;
    END
  END la_oenb[79]
  PIN la_oenb[78]
    DIRECTION INPUT ;
    USE SIGNAL ;
    PORT
      LAYER met2 ;
        RECT 1984.140000 0.000000 1984.280000 0.485000 ;
    END
  END la_oenb[78]
  PIN la_oenb[77]
    DIRECTION INPUT ;
    USE SIGNAL ;
    PORT
      LAYER met2 ;
        RECT 1966.660000 0.000000 1966.800000 0.485000 ;
    END
  END la_oenb[77]
  PIN la_oenb[76]
    DIRECTION INPUT ;
    USE SIGNAL ;
    PORT
      LAYER met2 ;
        RECT 1949.180000 0.000000 1949.320000 0.485000 ;
    END
  END la_oenb[76]
  PIN la_oenb[75]
    DIRECTION INPUT ;
    USE SIGNAL ;
    PORT
      LAYER met2 ;
        RECT 1931.700000 0.000000 1931.840000 0.485000 ;
    END
  END la_oenb[75]
  PIN la_oenb[74]
    DIRECTION INPUT ;
    USE SIGNAL ;
    PORT
      LAYER met2 ;
        RECT 1914.220000 0.000000 1914.360000 0.485000 ;
    END
  END la_oenb[74]
  PIN la_oenb[73]
    DIRECTION INPUT ;
    USE SIGNAL ;
    PORT
      LAYER met2 ;
        RECT 1896.740000 0.000000 1896.880000 0.485000 ;
    END
  END la_oenb[73]
  PIN la_oenb[72]
    DIRECTION INPUT ;
    USE SIGNAL ;
    PORT
      LAYER met2 ;
        RECT 1879.720000 0.000000 1879.860000 0.485000 ;
    END
  END la_oenb[72]
  PIN la_oenb[71]
    DIRECTION INPUT ;
    USE SIGNAL ;
    PORT
      LAYER met2 ;
        RECT 1862.240000 0.000000 1862.380000 0.485000 ;
    END
  END la_oenb[71]
  PIN la_oenb[70]
    DIRECTION INPUT ;
    USE SIGNAL ;
    PORT
      LAYER met2 ;
        RECT 1844.760000 0.000000 1844.900000 0.485000 ;
    END
  END la_oenb[70]
  PIN la_oenb[69]
    DIRECTION INPUT ;
    USE SIGNAL ;
    PORT
      LAYER met2 ;
        RECT 1827.280000 0.000000 1827.420000 0.485000 ;
    END
  END la_oenb[69]
  PIN la_oenb[68]
    DIRECTION INPUT ;
    USE SIGNAL ;
    PORT
      LAYER met2 ;
        RECT 1809.800000 0.000000 1809.940000 0.485000 ;
    END
  END la_oenb[68]
  PIN la_oenb[67]
    DIRECTION INPUT ;
    USE SIGNAL ;
    PORT
      LAYER met2 ;
        RECT 1792.780000 0.000000 1792.920000 0.485000 ;
    END
  END la_oenb[67]
  PIN la_oenb[66]
    DIRECTION INPUT ;
    USE SIGNAL ;
    PORT
      LAYER met2 ;
        RECT 1775.300000 0.000000 1775.440000 0.485000 ;
    END
  END la_oenb[66]
  PIN la_oenb[65]
    DIRECTION INPUT ;
    USE SIGNAL ;
    PORT
      LAYER met2 ;
        RECT 1757.820000 0.000000 1757.960000 0.485000 ;
    END
  END la_oenb[65]
  PIN la_oenb[64]
    DIRECTION INPUT ;
    USE SIGNAL ;
    PORT
      LAYER met2 ;
        RECT 1740.340000 0.000000 1740.480000 0.485000 ;
    END
  END la_oenb[64]
  PIN la_oenb[63]
    DIRECTION INPUT ;
    USE SIGNAL ;
    PORT
      LAYER met2 ;
        RECT 1722.860000 0.000000 1723.000000 0.485000 ;
    END
  END la_oenb[63]
  PIN la_oenb[62]
    DIRECTION INPUT ;
    USE SIGNAL ;
    PORT
      LAYER met2 ;
        RECT 1705.380000 0.000000 1705.520000 0.485000 ;
    END
  END la_oenb[62]
  PIN la_oenb[61]
    DIRECTION INPUT ;
    USE SIGNAL ;
    PORT
      LAYER met2 ;
        RECT 1688.360000 0.000000 1688.500000 0.485000 ;
    END
  END la_oenb[61]
  PIN la_oenb[60]
    DIRECTION INPUT ;
    USE SIGNAL ;
    PORT
      LAYER met2 ;
        RECT 1670.880000 0.000000 1671.020000 0.485000 ;
    END
  END la_oenb[60]
  PIN la_oenb[59]
    DIRECTION INPUT ;
    USE SIGNAL ;
    PORT
      LAYER met2 ;
        RECT 1653.400000 0.000000 1653.540000 0.485000 ;
    END
  END la_oenb[59]
  PIN la_oenb[58]
    DIRECTION INPUT ;
    USE SIGNAL ;
    PORT
      LAYER met2 ;
        RECT 1635.920000 0.000000 1636.060000 0.485000 ;
    END
  END la_oenb[58]
  PIN la_oenb[57]
    DIRECTION INPUT ;
    USE SIGNAL ;
    PORT
      LAYER met2 ;
        RECT 1618.440000 0.000000 1618.580000 0.485000 ;
    END
  END la_oenb[57]
  PIN la_oenb[56]
    DIRECTION INPUT ;
    USE SIGNAL ;
    PORT
      LAYER met2 ;
        RECT 1600.960000 0.000000 1601.100000 0.485000 ;
    END
  END la_oenb[56]
  PIN la_oenb[55]
    DIRECTION INPUT ;
    USE SIGNAL ;
    PORT
      LAYER met2 ;
        RECT 1583.940000 0.000000 1584.080000 0.485000 ;
    END
  END la_oenb[55]
  PIN la_oenb[54]
    DIRECTION INPUT ;
    USE SIGNAL ;
    PORT
      LAYER met2 ;
        RECT 1566.460000 0.000000 1566.600000 0.485000 ;
    END
  END la_oenb[54]
  PIN la_oenb[53]
    DIRECTION INPUT ;
    USE SIGNAL ;
    PORT
      LAYER met2 ;
        RECT 1548.980000 0.000000 1549.120000 0.485000 ;
    END
  END la_oenb[53]
  PIN la_oenb[52]
    DIRECTION INPUT ;
    USE SIGNAL ;
    PORT
      LAYER met2 ;
        RECT 1531.500000 0.000000 1531.640000 0.485000 ;
    END
  END la_oenb[52]
  PIN la_oenb[51]
    DIRECTION INPUT ;
    USE SIGNAL ;
    PORT
      LAYER met2 ;
        RECT 1514.020000 0.000000 1514.160000 0.485000 ;
    END
  END la_oenb[51]
  PIN la_oenb[50]
    DIRECTION INPUT ;
    USE SIGNAL ;
    PORT
      LAYER met2 ;
        RECT 1496.540000 0.000000 1496.680000 0.485000 ;
    END
  END la_oenb[50]
  PIN la_oenb[49]
    DIRECTION INPUT ;
    USE SIGNAL ;
    PORT
      LAYER met2 ;
        RECT 1479.520000 0.000000 1479.660000 0.485000 ;
    END
  END la_oenb[49]
  PIN la_oenb[48]
    DIRECTION INPUT ;
    USE SIGNAL ;
    PORT
      LAYER met2 ;
        RECT 1462.040000 0.000000 1462.180000 0.485000 ;
    END
  END la_oenb[48]
  PIN la_oenb[47]
    DIRECTION INPUT ;
    USE SIGNAL ;
    PORT
      LAYER met2 ;
        RECT 1444.560000 0.000000 1444.700000 0.485000 ;
    END
  END la_oenb[47]
  PIN la_oenb[46]
    DIRECTION INPUT ;
    USE SIGNAL ;
    PORT
      LAYER met2 ;
        RECT 1427.080000 0.000000 1427.220000 0.485000 ;
    END
  END la_oenb[46]
  PIN la_oenb[45]
    DIRECTION INPUT ;
    USE SIGNAL ;
    PORT
      LAYER met2 ;
        RECT 1409.600000 0.000000 1409.740000 0.485000 ;
    END
  END la_oenb[45]
  PIN la_oenb[44]
    DIRECTION INPUT ;
    USE SIGNAL ;
    PORT
      LAYER met2 ;
        RECT 1392.580000 0.000000 1392.720000 0.485000 ;
    END
  END la_oenb[44]
  PIN la_oenb[43]
    DIRECTION INPUT ;
    USE SIGNAL ;
    PORT
      LAYER met2 ;
        RECT 1375.100000 0.000000 1375.240000 0.485000 ;
    END
  END la_oenb[43]
  PIN la_oenb[42]
    DIRECTION INPUT ;
    USE SIGNAL ;
    PORT
      LAYER met2 ;
        RECT 1357.620000 0.000000 1357.760000 0.485000 ;
    END
  END la_oenb[42]
  PIN la_oenb[41]
    DIRECTION INPUT ;
    USE SIGNAL ;
    PORT
      LAYER met2 ;
        RECT 1340.140000 0.000000 1340.280000 0.485000 ;
    END
  END la_oenb[41]
  PIN la_oenb[40]
    DIRECTION INPUT ;
    USE SIGNAL ;
    PORT
      LAYER met2 ;
        RECT 1322.660000 0.000000 1322.800000 0.485000 ;
    END
  END la_oenb[40]
  PIN la_oenb[39]
    DIRECTION INPUT ;
    USE SIGNAL ;
    PORT
      LAYER met2 ;
        RECT 1305.180000 0.000000 1305.320000 0.485000 ;
    END
  END la_oenb[39]
  PIN la_oenb[38]
    DIRECTION INPUT ;
    USE SIGNAL ;
    PORT
      LAYER met2 ;
        RECT 1288.160000 0.000000 1288.300000 0.485000 ;
    END
  END la_oenb[38]
  PIN la_oenb[37]
    DIRECTION INPUT ;
    USE SIGNAL ;
    PORT
      LAYER met2 ;
        RECT 1270.680000 0.000000 1270.820000 0.485000 ;
    END
  END la_oenb[37]
  PIN la_oenb[36]
    DIRECTION INPUT ;
    USE SIGNAL ;
    PORT
      LAYER met2 ;
        RECT 1253.200000 0.000000 1253.340000 0.485000 ;
    END
  END la_oenb[36]
  PIN la_oenb[35]
    DIRECTION INPUT ;
    USE SIGNAL ;
    PORT
      LAYER met2 ;
        RECT 1235.720000 0.000000 1235.860000 0.485000 ;
    END
  END la_oenb[35]
  PIN la_oenb[34]
    DIRECTION INPUT ;
    USE SIGNAL ;
    PORT
      LAYER met2 ;
        RECT 1218.240000 0.000000 1218.380000 0.485000 ;
    END
  END la_oenb[34]
  PIN la_oenb[33]
    DIRECTION INPUT ;
    USE SIGNAL ;
    PORT
      LAYER met2 ;
        RECT 1200.760000 0.000000 1200.900000 0.485000 ;
    END
  END la_oenb[33]
  PIN la_oenb[32]
    DIRECTION INPUT ;
    USE SIGNAL ;
    PORT
      LAYER met2 ;
        RECT 1183.740000 0.000000 1183.880000 0.485000 ;
    END
  END la_oenb[32]
  PIN la_oenb[31]
    DIRECTION INPUT ;
    USE SIGNAL ;
    PORT
      LAYER met2 ;
        RECT 1166.260000 0.000000 1166.400000 0.485000 ;
    END
  END la_oenb[31]
  PIN la_oenb[30]
    DIRECTION INPUT ;
    USE SIGNAL ;
    PORT
      LAYER met2 ;
        RECT 1148.780000 0.000000 1148.920000 0.485000 ;
    END
  END la_oenb[30]
  PIN la_oenb[29]
    DIRECTION INPUT ;
    USE SIGNAL ;
    PORT
      LAYER met2 ;
        RECT 1131.300000 0.000000 1131.440000 0.485000 ;
    END
  END la_oenb[29]
  PIN la_oenb[28]
    DIRECTION INPUT ;
    USE SIGNAL ;
    PORT
      LAYER met2 ;
        RECT 1113.820000 0.000000 1113.960000 0.485000 ;
    END
  END la_oenb[28]
  PIN la_oenb[27]
    DIRECTION INPUT ;
    USE SIGNAL ;
    PORT
      LAYER met2 ;
        RECT 1096.800000 0.000000 1096.940000 0.485000 ;
    END
  END la_oenb[27]
  PIN la_oenb[26]
    DIRECTION INPUT ;
    USE SIGNAL ;
    PORT
      LAYER met2 ;
        RECT 1079.320000 0.000000 1079.460000 0.485000 ;
    END
  END la_oenb[26]
  PIN la_oenb[25]
    DIRECTION INPUT ;
    USE SIGNAL ;
    PORT
      LAYER met2 ;
        RECT 1061.840000 0.000000 1061.980000 0.485000 ;
    END
  END la_oenb[25]
  PIN la_oenb[24]
    DIRECTION INPUT ;
    USE SIGNAL ;
    PORT
      LAYER met2 ;
        RECT 1044.360000 0.000000 1044.500000 0.485000 ;
    END
  END la_oenb[24]
  PIN la_oenb[23]
    DIRECTION INPUT ;
    USE SIGNAL ;
    PORT
      LAYER met2 ;
        RECT 1026.880000 0.000000 1027.020000 0.485000 ;
    END
  END la_oenb[23]
  PIN la_oenb[22]
    DIRECTION INPUT ;
    USE SIGNAL ;
    PORT
      LAYER met2 ;
        RECT 1009.400000 0.000000 1009.540000 0.485000 ;
    END
  END la_oenb[22]
  PIN la_oenb[21]
    DIRECTION INPUT ;
    USE SIGNAL ;
    PORT
      LAYER met2 ;
        RECT 992.380000 0.000000 992.520000 0.485000 ;
    END
  END la_oenb[21]
  PIN la_oenb[20]
    DIRECTION INPUT ;
    USE SIGNAL ;
    PORT
      LAYER met2 ;
        RECT 974.900000 0.000000 975.040000 0.485000 ;
    END
  END la_oenb[20]
  PIN la_oenb[19]
    DIRECTION INPUT ;
    USE SIGNAL ;
    PORT
      LAYER met2 ;
        RECT 957.420000 0.000000 957.560000 0.485000 ;
    END
  END la_oenb[19]
  PIN la_oenb[18]
    DIRECTION INPUT ;
    USE SIGNAL ;
    PORT
      LAYER met2 ;
        RECT 939.940000 0.000000 940.080000 0.485000 ;
    END
  END la_oenb[18]
  PIN la_oenb[17]
    DIRECTION INPUT ;
    USE SIGNAL ;
    PORT
      LAYER met2 ;
        RECT 922.460000 0.000000 922.600000 0.485000 ;
    END
  END la_oenb[17]
  PIN la_oenb[16]
    DIRECTION INPUT ;
    USE SIGNAL ;
    PORT
      LAYER met2 ;
        RECT 904.980000 0.000000 905.120000 0.485000 ;
    END
  END la_oenb[16]
  PIN la_oenb[15]
    DIRECTION INPUT ;
    USE SIGNAL ;
    PORT
      LAYER met2 ;
        RECT 887.960000 0.000000 888.100000 0.485000 ;
    END
  END la_oenb[15]
  PIN la_oenb[14]
    DIRECTION INPUT ;
    USE SIGNAL ;
    PORT
      LAYER met2 ;
        RECT 870.480000 0.000000 870.620000 0.485000 ;
    END
  END la_oenb[14]
  PIN la_oenb[13]
    DIRECTION INPUT ;
    USE SIGNAL ;
    PORT
      LAYER met2 ;
        RECT 853.000000 0.000000 853.140000 0.485000 ;
    END
  END la_oenb[13]
  PIN la_oenb[12]
    DIRECTION INPUT ;
    USE SIGNAL ;
    PORT
      LAYER met2 ;
        RECT 835.520000 0.000000 835.660000 0.485000 ;
    END
  END la_oenb[12]
  PIN la_oenb[11]
    DIRECTION INPUT ;
    USE SIGNAL ;
    PORT
      LAYER met2 ;
        RECT 818.040000 0.000000 818.180000 0.485000 ;
    END
  END la_oenb[11]
  PIN la_oenb[10]
    DIRECTION INPUT ;
    USE SIGNAL ;
    PORT
      LAYER met2 ;
        RECT 800.560000 0.000000 800.700000 0.485000 ;
    END
  END la_oenb[10]
  PIN la_oenb[9]
    DIRECTION INPUT ;
    USE SIGNAL ;
    PORT
      LAYER met2 ;
        RECT 783.540000 0.000000 783.680000 0.485000 ;
    END
  END la_oenb[9]
  PIN la_oenb[8]
    DIRECTION INPUT ;
    USE SIGNAL ;
    PORT
      LAYER met2 ;
        RECT 766.060000 0.000000 766.200000 0.485000 ;
    END
  END la_oenb[8]
  PIN la_oenb[7]
    DIRECTION INPUT ;
    USE SIGNAL ;
    PORT
      LAYER met2 ;
        RECT 748.580000 0.000000 748.720000 0.485000 ;
    END
  END la_oenb[7]
  PIN la_oenb[6]
    DIRECTION INPUT ;
    USE SIGNAL ;
    PORT
      LAYER met2 ;
        RECT 731.100000 0.000000 731.240000 0.485000 ;
    END
  END la_oenb[6]
  PIN la_oenb[5]
    DIRECTION INPUT ;
    USE SIGNAL ;
    PORT
      LAYER met2 ;
        RECT 713.620000 0.000000 713.760000 0.485000 ;
    END
  END la_oenb[5]
  PIN la_oenb[4]
    DIRECTION INPUT ;
    USE SIGNAL ;
    PORT
      LAYER met2 ;
        RECT 696.600000 0.000000 696.740000 0.485000 ;
    END
  END la_oenb[4]
  PIN la_oenb[3]
    DIRECTION INPUT ;
    USE SIGNAL ;
    PORT
      LAYER met2 ;
        RECT 679.120000 0.000000 679.260000 0.485000 ;
    END
  END la_oenb[3]
  PIN la_oenb[2]
    DIRECTION INPUT ;
    USE SIGNAL ;
    PORT
      LAYER met2 ;
        RECT 661.640000 0.000000 661.780000 0.485000 ;
    END
  END la_oenb[2]
  PIN la_oenb[1]
    DIRECTION INPUT ;
    USE SIGNAL ;
    PORT
      LAYER met2 ;
        RECT 644.160000 0.000000 644.300000 0.485000 ;
    END
  END la_oenb[1]
  PIN la_oenb[0]
    DIRECTION INPUT ;
    USE SIGNAL ;
    PORT
      LAYER met2 ;
        RECT 626.680000 0.000000 626.820000 0.485000 ;
    END
  END la_oenb[0]
  PIN io_in[37]
    DIRECTION INPUT ;
    USE SIGNAL ;
    PORT
      LAYER met3 ;
        RECT 0.000000 131.060000 0.800000 131.360000 ;
    END
  END io_in[37]
  PIN io_in[36]
    DIRECTION INPUT ;
    USE SIGNAL ;
    PORT
      LAYER met3 ;
        RECT 0.000000 327.480000 0.800000 327.780000 ;
    END
  END io_in[36]
  PIN io_in[35]
    DIRECTION INPUT ;
    USE SIGNAL ;
    PORT
      LAYER met3 ;
        RECT 0.000000 523.900000 0.800000 524.200000 ;
    END
  END io_in[35]
  PIN io_in[34]
    DIRECTION INPUT ;
    USE SIGNAL ;
    PORT
      LAYER met3 ;
        RECT 0.000000 785.590000 0.800000 785.890000 ;
    END
  END io_in[34]
  PIN io_in[33]
    DIRECTION INPUT ;
    USE SIGNAL ;
    PORT
      LAYER met3 ;
        RECT 0.000000 1047.280000 0.800000 1047.580000 ;
    END
  END io_in[33]
  PIN io_in[32]
    DIRECTION INPUT ;
    USE SIGNAL ;
    PORT
      LAYER met3 ;
        RECT 0.000000 1309.580000 0.800000 1309.880000 ;
    END
  END io_in[32]
  PIN io_in[31]
    DIRECTION INPUT ;
    USE SIGNAL ;
    PORT
      LAYER met3 ;
        RECT 0.000000 1571.270000 0.800000 1571.570000 ;
    END
  END io_in[31]
  PIN io_in[30]
    DIRECTION INPUT ;
    USE SIGNAL ;
    PORT
      LAYER met3 ;
        RECT 0.000000 1832.960000 0.800000 1833.260000 ;
    END
  END io_in[30]
  PIN io_in[29]
    DIRECTION INPUT ;
    USE SIGNAL ;
    PORT
      LAYER met3 ;
        RECT 0.000000 2094.650000 0.800000 2094.950000 ;
    END
  END io_in[29]
  PIN io_in[28]
    DIRECTION INPUT ;
    USE SIGNAL ;
    PORT
      LAYER met3 ;
        RECT 0.000000 2356.340000 0.800000 2356.640000 ;
    END
  END io_in[28]
  PIN io_in[27]
    DIRECTION INPUT ;
    USE SIGNAL ;
    PORT
      LAYER met3 ;
        RECT 0.000000 2618.640000 0.800000 2618.940000 ;
    END
  END io_in[27]
  PIN io_in[26]
    DIRECTION INPUT ;
    USE SIGNAL ;
    PORT
      LAYER met3 ;
        RECT 0.000000 2880.330000 0.800000 2880.630000 ;
    END
  END io_in[26]
  PIN io_in[25]
    DIRECTION INPUT ;
    USE SIGNAL ;
    PORT
      LAYER met3 ;
        RECT 0.000000 3142.020000 0.800000 3142.320000 ;
    END
  END io_in[25]
  PIN io_in[24]
    DIRECTION INPUT ;
    USE SIGNAL ;
    PORT
      LAYER met3 ;
        RECT 0.000000 3403.710000 0.800000 3404.010000 ;
    END
  END io_in[24]
  PIN io_in[23]
    DIRECTION INPUT ;
    USE SIGNAL ;
    PORT
      LAYER met2 ;
        RECT 163.460000 3469.555000 163.600000 3470.040000 ;
    END
  END io_in[23]
  PIN io_in[22]
    DIRECTION INPUT ;
    USE SIGNAL ;
    PORT
      LAYER met2 ;
        RECT 490.060000 3469.555000 490.200000 3470.040000 ;
    END
  END io_in[22]
  PIN io_in[21]
    DIRECTION INPUT ;
    USE SIGNAL ;
    PORT
      LAYER met2 ;
        RECT 816.660000 3469.555000 816.800000 3470.040000 ;
    END
  END io_in[21]
  PIN io_in[20]
    DIRECTION INPUT ;
    USE SIGNAL ;
    PORT
      LAYER met2 ;
        RECT 1143.720000 3469.555000 1143.860000 3470.040000 ;
    END
  END io_in[20]
  PIN io_in[19]
    DIRECTION INPUT ;
    USE SIGNAL ;
    PORT
      LAYER met2 ;
        RECT 1470.320000 3469.555000 1470.460000 3470.040000 ;
    END
  END io_in[19]
  PIN io_in[18]
    DIRECTION INPUT ;
    USE SIGNAL ;
    PORT
      LAYER met2 ;
        RECT 1797.380000 3469.555000 1797.520000 3470.040000 ;
    END
  END io_in[18]
  PIN io_in[17]
    DIRECTION INPUT ;
    USE SIGNAL ;
    PORT
      LAYER met2 ;
        RECT 2123.980000 3469.555000 2124.120000 3470.040000 ;
    END
  END io_in[17]
  PIN io_in[16]
    DIRECTION INPUT ;
    USE SIGNAL ;
    PORT
      LAYER met2 ;
        RECT 2451.040000 3469.555000 2451.180000 3470.040000 ;
    END
  END io_in[16]
  PIN io_in[15]
    DIRECTION INPUT ;
    USE SIGNAL ;
    PORT
      LAYER met2 ;
        RECT 2777.640000 3469.555000 2777.780000 3470.040000 ;
    END
  END io_in[15]
  PIN io_in[14]
    DIRECTION INPUT ;
    USE SIGNAL ;
    PORT
      LAYER met3 ;
        RECT 2859.020000 3336.610000 2859.820000 3336.910000 ;
    END
  END io_in[14]
  PIN io_in[13]
    DIRECTION INPUT ;
    USE SIGNAL ;
    PORT
      LAYER met3 ;
        RECT 2859.020000 3069.430000 2859.820000 3069.730000 ;
    END
  END io_in[13]
  PIN io_in[12]
    DIRECTION INPUT ;
    USE SIGNAL ;
    PORT
      LAYER met3 ;
        RECT 2859.020000 2802.860000 2859.820000 2803.160000 ;
    END
  END io_in[12]
  PIN io_in[11]
    DIRECTION INPUT ;
    USE SIGNAL ;
    PORT
      LAYER met3 ;
        RECT 2859.020000 2535.680000 2859.820000 2535.980000 ;
    END
  END io_in[11]
  PIN io_in[10]
    DIRECTION INPUT ;
    USE SIGNAL ;
    PORT
      LAYER met3 ;
        RECT 2859.020000 2269.110000 2859.820000 2269.410000 ;
    END
  END io_in[10]
  PIN io_in[9]
    DIRECTION INPUT ;
    USE SIGNAL ;
    PORT
      LAYER met3 ;
        RECT 2859.020000 2001.930000 2859.820000 2002.230000 ;
    END
  END io_in[9]
  PIN io_in[8]
    DIRECTION INPUT ;
    USE SIGNAL ;
    PORT
      LAYER met3 ;
        RECT 2859.020000 1735.360000 2859.820000 1735.660000 ;
    END
  END io_in[8]
  PIN io_in[7]
    DIRECTION INPUT ;
    USE SIGNAL ;
    PORT
      LAYER met3 ;
        RECT 2859.020000 1468.790000 2859.820000 1469.090000 ;
    END
  END io_in[7]
  PIN io_in[6]
    DIRECTION INPUT ;
    USE SIGNAL ;
    PORT
      LAYER met3 ;
        RECT 2859.020000 1201.610000 2859.820000 1201.910000 ;
    END
  END io_in[6]
  PIN io_in[5]
    DIRECTION INPUT ;
    USE SIGNAL ;
    PORT
      LAYER met3 ;
        RECT 2859.020000 1001.530000 2859.820000 1001.830000 ;
    END
  END io_in[5]
  PIN io_in[4]
    DIRECTION INPUT ;
    USE SIGNAL ;
    PORT
      LAYER met3 ;
        RECT 2859.020000 801.450000 2859.820000 801.750000 ;
    END
  END io_in[4]
  PIN io_in[3]
    DIRECTION INPUT ;
    USE SIGNAL ;
    PORT
      LAYER met3 ;
        RECT 2859.020000 601.370000 2859.820000 601.670000 ;
    END
  END io_in[3]
  PIN io_in[2]
    DIRECTION INPUT ;
    USE SIGNAL ;
    PORT
      LAYER met3 ;
        RECT 2859.020000 401.290000 2859.820000 401.590000 ;
    END
  END io_in[2]
  PIN io_in[1]
    DIRECTION INPUT ;
    USE SIGNAL ;
    PORT
      LAYER met3 ;
        RECT 2859.020000 201.210000 2859.820000 201.510000 ;
    END
  END io_in[1]
  PIN io_in[0]
    DIRECTION INPUT ;
    USE SIGNAL ;
    PORT
      LAYER met3 ;
        RECT 2859.020000 0.520000 2859.820000 0.820000 ;
    END
  END io_in[0]
  PIN io_out[37]
    DIRECTION OUTPUT ;
    USE SIGNAL ;
    PORT
      LAYER met3 ;
        RECT 0.000000 65.790000 0.800000 66.090000 ;
    END
  END io_out[37]
  PIN io_out[36]
    DIRECTION OUTPUT ;
    USE SIGNAL ;
    PORT
      LAYER met3 ;
        RECT 0.000000 262.210000 0.800000 262.510000 ;
    END
  END io_out[36]
  PIN io_out[35]
    DIRECTION OUTPUT ;
    USE SIGNAL ;
    PORT
      LAYER met3 ;
        RECT 0.000000 458.630000 0.800000 458.930000 ;
    END
  END io_out[35]
  PIN io_out[34]
    DIRECTION OUTPUT ;
    USE SIGNAL ;
    PORT
      LAYER met3 ;
        RECT 0.000000 720.320000 0.800000 720.620000 ;
    END
  END io_out[34]
  PIN io_out[33]
    DIRECTION OUTPUT ;
    USE SIGNAL ;
    PORT
      LAYER met3 ;
        RECT 0.000000 982.010000 0.800000 982.310000 ;
    END
  END io_out[33]
  PIN io_out[32]
    DIRECTION OUTPUT ;
    USE SIGNAL ;
    PORT
      LAYER met3 ;
        RECT 0.000000 1243.700000 0.800000 1244.000000 ;
    END
  END io_out[32]
  PIN io_out[31]
    DIRECTION OUTPUT ;
    USE SIGNAL ;
    PORT
      LAYER met3 ;
        RECT 0.000000 1505.390000 0.800000 1505.690000 ;
    END
  END io_out[31]
  PIN io_out[30]
    DIRECTION OUTPUT ;
    USE SIGNAL ;
    PORT
      LAYER met3 ;
        RECT 0.000000 1767.690000 0.800000 1767.990000 ;
    END
  END io_out[30]
  PIN io_out[29]
    DIRECTION OUTPUT ;
    USE SIGNAL ;
    PORT
      LAYER met3 ;
        RECT 0.000000 2029.380000 0.800000 2029.680000 ;
    END
  END io_out[29]
  PIN io_out[28]
    DIRECTION OUTPUT ;
    USE SIGNAL ;
    PORT
      LAYER met3 ;
        RECT 0.000000 2291.070000 0.800000 2291.370000 ;
    END
  END io_out[28]
  PIN io_out[27]
    DIRECTION OUTPUT ;
    USE SIGNAL ;
    PORT
      LAYER met3 ;
        RECT 0.000000 2552.760000 0.800000 2553.060000 ;
    END
  END io_out[27]
  PIN io_out[26]
    DIRECTION OUTPUT ;
    USE SIGNAL ;
    PORT
      LAYER met3 ;
        RECT 0.000000 2814.450000 0.800000 2814.750000 ;
    END
  END io_out[26]
  PIN io_out[25]
    DIRECTION OUTPUT ;
    USE SIGNAL ;
    PORT
      LAYER met3 ;
        RECT 0.000000 3076.750000 0.800000 3077.050000 ;
    END
  END io_out[25]
  PIN io_out[24]
    DIRECTION OUTPUT ;
    USE SIGNAL ;
    PORT
      LAYER met3 ;
        RECT 0.000000 3338.440000 0.800000 3338.740000 ;
    END
  END io_out[24]
  PIN io_out[23]
    DIRECTION OUTPUT ;
    USE SIGNAL ;
    PORT
      LAYER met2 ;
        RECT 81.580000 3469.555000 81.720000 3470.040000 ;
    END
  END io_out[23]
  PIN io_out[22]
    DIRECTION OUTPUT ;
    USE SIGNAL ;
    PORT
      LAYER met2 ;
        RECT 408.640000 3469.555000 408.780000 3470.040000 ;
    END
  END io_out[22]
  PIN io_out[21]
    DIRECTION OUTPUT ;
    USE SIGNAL ;
    PORT
      LAYER met2 ;
        RECT 735.240000 3469.555000 735.380000 3470.040000 ;
    END
  END io_out[21]
  PIN io_out[20]
    DIRECTION OUTPUT ;
    USE SIGNAL ;
    PORT
      LAYER met2 ;
        RECT 1061.840000 3469.555000 1061.980000 3470.040000 ;
    END
  END io_out[20]
  PIN io_out[19]
    DIRECTION OUTPUT ;
    USE SIGNAL ;
    PORT
      LAYER met2 ;
        RECT 1388.900000 3469.555000 1389.040000 3470.040000 ;
    END
  END io_out[19]
  PIN io_out[18]
    DIRECTION OUTPUT ;
    USE SIGNAL ;
    PORT
      LAYER met2 ;
        RECT 1715.500000 3469.555000 1715.640000 3470.040000 ;
    END
  END io_out[18]
  PIN io_out[17]
    DIRECTION OUTPUT ;
    USE SIGNAL ;
    PORT
      LAYER met2 ;
        RECT 2042.100000 3469.555000 2042.240000 3470.040000 ;
    END
  END io_out[17]
  PIN io_out[16]
    DIRECTION OUTPUT ;
    USE SIGNAL ;
    PORT
      LAYER met2 ;
        RECT 2369.160000 3469.555000 2369.300000 3470.040000 ;
    END
  END io_out[16]
  PIN io_out[15]
    DIRECTION OUTPUT ;
    USE SIGNAL ;
    PORT
      LAYER met2 ;
        RECT 2695.760000 3469.555000 2695.900000 3470.040000 ;
    END
  END io_out[15]
  PIN io_out[14]
    DIRECTION OUTPUT ;
    USE SIGNAL ;
    PORT
      LAYER met3 ;
        RECT 2859.020000 3403.100000 2859.820000 3403.400000 ;
    END
  END io_out[14]
  PIN io_out[13]
    DIRECTION OUTPUT ;
    USE SIGNAL ;
    PORT
      LAYER met3 ;
        RECT 2859.020000 3136.530000 2859.820000 3136.830000 ;
    END
  END io_out[13]
  PIN io_out[12]
    DIRECTION OUTPUT ;
    USE SIGNAL ;
    PORT
      LAYER met3 ;
        RECT 2859.020000 2869.350000 2859.820000 2869.650000 ;
    END
  END io_out[12]
  PIN io_out[11]
    DIRECTION OUTPUT ;
    USE SIGNAL ;
    PORT
      LAYER met3 ;
        RECT 2859.020000 2602.780000 2859.820000 2603.080000 ;
    END
  END io_out[11]
  PIN io_out[10]
    DIRECTION OUTPUT ;
    USE SIGNAL ;
    PORT
      LAYER met3 ;
        RECT 2859.020000 2335.600000 2859.820000 2335.900000 ;
    END
  END io_out[10]
  PIN io_out[9]
    DIRECTION OUTPUT ;
    USE SIGNAL ;
    PORT
      LAYER met3 ;
        RECT 2859.020000 2069.030000 2859.820000 2069.330000 ;
    END
  END io_out[9]
  PIN io_out[8]
    DIRECTION OUTPUT ;
    USE SIGNAL ;
    PORT
      LAYER met3 ;
        RECT 2859.020000 1801.850000 2859.820000 1802.150000 ;
    END
  END io_out[8]
  PIN io_out[7]
    DIRECTION OUTPUT ;
    USE SIGNAL ;
    PORT
      LAYER met3 ;
        RECT 2859.020000 1535.280000 2859.820000 1535.580000 ;
    END
  END io_out[7]
  PIN io_out[6]
    DIRECTION OUTPUT ;
    USE SIGNAL ;
    PORT
      LAYER met3 ;
        RECT 2859.020000 1268.100000 2859.820000 1268.400000 ;
    END
  END io_out[6]
  PIN io_out[5]
    DIRECTION OUTPUT ;
    USE SIGNAL ;
    PORT
      LAYER met3 ;
        RECT 2859.020000 1068.020000 2859.820000 1068.320000 ;
    END
  END io_out[5]
  PIN io_out[4]
    DIRECTION OUTPUT ;
    USE SIGNAL ;
    PORT
      LAYER met3 ;
        RECT 2859.020000 867.940000 2859.820000 868.240000 ;
    END
  END io_out[4]
  PIN io_out[3]
    DIRECTION OUTPUT ;
    USE SIGNAL ;
    PORT
      LAYER met3 ;
        RECT 2859.020000 667.860000 2859.820000 668.160000 ;
    END
  END io_out[3]
  PIN io_out[2]
    DIRECTION OUTPUT ;
    USE SIGNAL ;
    PORT
      LAYER met3 ;
        RECT 2859.020000 467.780000 2859.820000 468.080000 ;
    END
  END io_out[2]
  PIN io_out[1]
    DIRECTION OUTPUT ;
    USE SIGNAL ;
    PORT
      LAYER met3 ;
        RECT 2859.020000 267.700000 2859.820000 268.000000 ;
    END
  END io_out[1]
  PIN io_out[0]
    DIRECTION OUTPUT ;
    USE SIGNAL ;
    PORT
      LAYER met3 ;
        RECT 2859.020000 67.620000 2859.820000 67.920000 ;
    END
  END io_out[0]
  PIN io_oeb[37]
    DIRECTION OUTPUT ;
    USE SIGNAL ;
    PORT
      LAYER met3 ;
        RECT 0.000000 0.520000 0.800000 0.820000 ;
    END
  END io_oeb[37]
  PIN io_oeb[36]
    DIRECTION OUTPUT ;
    USE SIGNAL ;
    PORT
      LAYER met3 ;
        RECT 0.000000 196.330000 0.800000 196.630000 ;
    END
  END io_oeb[36]
  PIN io_oeb[35]
    DIRECTION OUTPUT ;
    USE SIGNAL ;
    PORT
      LAYER met3 ;
        RECT 0.000000 392.750000 0.800000 393.050000 ;
    END
  END io_oeb[35]
  PIN io_oeb[34]
    DIRECTION OUTPUT ;
    USE SIGNAL ;
    PORT
      LAYER met3 ;
        RECT 0.000000 655.050000 0.800000 655.350000 ;
    END
  END io_oeb[34]
  PIN io_oeb[33]
    DIRECTION OUTPUT ;
    USE SIGNAL ;
    PORT
      LAYER met3 ;
        RECT 0.000000 916.740000 0.800000 917.040000 ;
    END
  END io_oeb[33]
  PIN io_oeb[32]
    DIRECTION OUTPUT ;
    USE SIGNAL ;
    PORT
      LAYER met3 ;
        RECT 0.000000 1178.430000 0.800000 1178.730000 ;
    END
  END io_oeb[32]
  PIN io_oeb[31]
    DIRECTION OUTPUT ;
    USE SIGNAL ;
    PORT
      LAYER met3 ;
        RECT 0.000000 1440.120000 0.800000 1440.420000 ;
    END
  END io_oeb[31]
  PIN io_oeb[30]
    DIRECTION OUTPUT ;
    USE SIGNAL ;
    PORT
      LAYER met3 ;
        RECT 0.000000 1701.810000 0.800000 1702.110000 ;
    END
  END io_oeb[30]
  PIN io_oeb[29]
    DIRECTION OUTPUT ;
    USE SIGNAL ;
    PORT
      LAYER met3 ;
        RECT 0.000000 1964.110000 0.800000 1964.410000 ;
    END
  END io_oeb[29]
  PIN io_oeb[28]
    DIRECTION OUTPUT ;
    USE SIGNAL ;
    PORT
      LAYER met3 ;
        RECT 0.000000 2225.800000 0.800000 2226.100000 ;
    END
  END io_oeb[28]
  PIN io_oeb[27]
    DIRECTION OUTPUT ;
    USE SIGNAL ;
    PORT
      LAYER met3 ;
        RECT 0.000000 2487.490000 0.800000 2487.790000 ;
    END
  END io_oeb[27]
  PIN io_oeb[26]
    DIRECTION OUTPUT ;
    USE SIGNAL ;
    PORT
      LAYER met3 ;
        RECT 0.000000 2749.180000 0.800000 2749.480000 ;
    END
  END io_oeb[26]
  PIN io_oeb[25]
    DIRECTION OUTPUT ;
    USE SIGNAL ;
    PORT
      LAYER met3 ;
        RECT 0.000000 3010.870000 0.800000 3011.170000 ;
    END
  END io_oeb[25]
  PIN io_oeb[24]
    DIRECTION OUTPUT ;
    USE SIGNAL ;
    PORT
      LAYER met3 ;
        RECT 0.000000 3273.170000 0.800000 3273.470000 ;
    END
  END io_oeb[24]
  PIN io_oeb[23]
    DIRECTION OUTPUT ;
    USE SIGNAL ;
    PORT
      LAYER met2 ;
        RECT 0.160000 3469.555000 0.300000 3470.040000 ;
    END
  END io_oeb[23]
  PIN io_oeb[22]
    DIRECTION OUTPUT ;
    USE SIGNAL ;
    PORT
      LAYER met2 ;
        RECT 326.760000 3469.555000 326.900000 3470.040000 ;
    END
  END io_oeb[22]
  PIN io_oeb[21]
    DIRECTION OUTPUT ;
    USE SIGNAL ;
    PORT
      LAYER met2 ;
        RECT 653.360000 3469.555000 653.500000 3470.040000 ;
    END
  END io_oeb[21]
  PIN io_oeb[20]
    DIRECTION OUTPUT ;
    USE SIGNAL ;
    PORT
      LAYER met2 ;
        RECT 980.420000 3469.555000 980.560000 3470.040000 ;
    END
  END io_oeb[20]
  PIN io_oeb[19]
    DIRECTION OUTPUT ;
    USE SIGNAL ;
    PORT
      LAYER met2 ;
        RECT 1307.020000 3469.555000 1307.160000 3470.040000 ;
    END
  END io_oeb[19]
  PIN io_oeb[18]
    DIRECTION OUTPUT ;
    USE SIGNAL ;
    PORT
      LAYER met2 ;
        RECT 1633.620000 3469.555000 1633.760000 3470.040000 ;
    END
  END io_oeb[18]
  PIN io_oeb[17]
    DIRECTION OUTPUT ;
    USE SIGNAL ;
    PORT
      LAYER met2 ;
        RECT 1960.680000 3469.555000 1960.820000 3470.040000 ;
    END
  END io_oeb[17]
  PIN io_oeb[16]
    DIRECTION OUTPUT ;
    USE SIGNAL ;
    PORT
      LAYER met2 ;
        RECT 2287.280000 3469.555000 2287.420000 3470.040000 ;
    END
  END io_oeb[16]
  PIN io_oeb[15]
    DIRECTION OUTPUT ;
    USE SIGNAL ;
    PORT
      LAYER met2 ;
        RECT 2614.340000 3469.555000 2614.480000 3470.040000 ;
    END
  END io_oeb[15]
  PIN io_oeb[14]
    DIRECTION OUTPUT ;
    USE SIGNAL ;
    PORT
      LAYER met3 ;
        RECT 2859.020000 3469.590000 2859.820000 3469.890000 ;
    END
  END io_oeb[14]
  PIN io_oeb[13]
    DIRECTION OUTPUT ;
    USE SIGNAL ;
    PORT
      LAYER met3 ;
        RECT 2859.020000 3203.020000 2859.820000 3203.320000 ;
    END
  END io_oeb[13]
  PIN io_oeb[12]
    DIRECTION OUTPUT ;
    USE SIGNAL ;
    PORT
      LAYER met3 ;
        RECT 2859.020000 2936.450000 2859.820000 2936.750000 ;
    END
  END io_oeb[12]
  PIN io_oeb[11]
    DIRECTION OUTPUT ;
    USE SIGNAL ;
    PORT
      LAYER met3 ;
        RECT 2859.020000 2669.270000 2859.820000 2669.570000 ;
    END
  END io_oeb[11]
  PIN io_oeb[10]
    DIRECTION OUTPUT ;
    USE SIGNAL ;
    PORT
      LAYER met3 ;
        RECT 2859.020000 2402.700000 2859.820000 2403.000000 ;
    END
  END io_oeb[10]
  PIN io_oeb[9]
    DIRECTION OUTPUT ;
    USE SIGNAL ;
    PORT
      LAYER met3 ;
        RECT 2859.020000 2135.520000 2859.820000 2135.820000 ;
    END
  END io_oeb[9]
  PIN io_oeb[8]
    DIRECTION OUTPUT ;
    USE SIGNAL ;
    PORT
      LAYER met3 ;
        RECT 2859.020000 1868.950000 2859.820000 1869.250000 ;
    END
  END io_oeb[8]
  PIN io_oeb[7]
    DIRECTION OUTPUT ;
    USE SIGNAL ;
    PORT
      LAYER met3 ;
        RECT 2859.020000 1601.770000 2859.820000 1602.070000 ;
    END
  END io_oeb[7]
  PIN io_oeb[6]
    DIRECTION OUTPUT ;
    USE SIGNAL ;
    PORT
      LAYER met3 ;
        RECT 2859.020000 1335.200000 2859.820000 1335.500000 ;
    END
  END io_oeb[6]
  PIN io_oeb[5]
    DIRECTION OUTPUT ;
    USE SIGNAL ;
    PORT
      LAYER met3 ;
        RECT 2859.020000 1135.120000 2859.820000 1135.420000 ;
    END
  END io_oeb[5]
  PIN io_oeb[4]
    DIRECTION OUTPUT ;
    USE SIGNAL ;
    PORT
      LAYER met3 ;
        RECT 2859.020000 935.040000 2859.820000 935.340000 ;
    END
  END io_oeb[4]
  PIN io_oeb[3]
    DIRECTION OUTPUT ;
    USE SIGNAL ;
    PORT
      LAYER met3 ;
        RECT 2859.020000 734.960000 2859.820000 735.260000 ;
    END
  END io_oeb[3]
  PIN io_oeb[2]
    DIRECTION OUTPUT ;
    USE SIGNAL ;
    PORT
      LAYER met3 ;
        RECT 2859.020000 534.270000 2859.820000 534.570000 ;
    END
  END io_oeb[2]
  PIN io_oeb[1]
    DIRECTION OUTPUT ;
    USE SIGNAL ;
    PORT
      LAYER met3 ;
        RECT 2859.020000 334.190000 2859.820000 334.490000 ;
    END
  END io_oeb[1]
  PIN io_oeb[0]
    DIRECTION OUTPUT ;
    USE SIGNAL ;
    PORT
      LAYER met3 ;
        RECT 2859.020000 134.110000 2859.820000 134.410000 ;
    END
  END io_oeb[0]
  PIN analog_io[28]
    DIRECTION INOUT ;
    USE SIGNAL ;
    PORT
      LAYER met3 ;
        RECT 0.000000 589.170000 0.800000 589.470000 ;
    END
  END analog_io[28]
  PIN analog_io[27]
    DIRECTION INOUT ;
    USE SIGNAL ;
    PORT
      LAYER met3 ;
        RECT 0.000000 850.860000 0.800000 851.160000 ;
    END
  END analog_io[27]
  PIN analog_io[26]
    DIRECTION INOUT ;
    USE SIGNAL ;
    PORT
      LAYER met3 ;
        RECT 0.000000 1113.160000 0.800000 1113.460000 ;
    END
  END analog_io[26]
  PIN analog_io[25]
    DIRECTION INOUT ;
    USE SIGNAL ;
    PORT
      LAYER met3 ;
        RECT 0.000000 1374.850000 0.800000 1375.150000 ;
    END
  END analog_io[25]
  PIN analog_io[24]
    DIRECTION INOUT ;
    USE SIGNAL ;
    PORT
      LAYER met3 ;
        RECT 0.000000 1636.540000 0.800000 1636.840000 ;
    END
  END analog_io[24]
  PIN analog_io[23]
    DIRECTION INOUT ;
    USE SIGNAL ;
    PORT
      LAYER met3 ;
        RECT 0.000000 1898.230000 0.800000 1898.530000 ;
    END
  END analog_io[23]
  PIN analog_io[22]
    DIRECTION INOUT ;
    USE SIGNAL ;
    PORT
      LAYER met3 ;
        RECT 0.000000 2159.920000 0.800000 2160.220000 ;
    END
  END analog_io[22]
  PIN analog_io[21]
    DIRECTION INOUT ;
    USE SIGNAL ;
    PORT
      LAYER met3 ;
        RECT 0.000000 2422.220000 0.800000 2422.520000 ;
    END
  END analog_io[21]
  PIN analog_io[20]
    DIRECTION INOUT ;
    USE SIGNAL ;
    PORT
      LAYER met3 ;
        RECT 0.000000 2683.910000 0.800000 2684.210000 ;
    END
  END analog_io[20]
  PIN analog_io[19]
    DIRECTION INOUT ;
    USE SIGNAL ;
    PORT
      LAYER met3 ;
        RECT 0.000000 2945.600000 0.800000 2945.900000 ;
    END
  END analog_io[19]
  PIN analog_io[18]
    DIRECTION INOUT ;
    USE SIGNAL ;
    PORT
      LAYER met3 ;
        RECT 0.000000 3207.290000 0.800000 3207.590000 ;
    END
  END analog_io[18]
  PIN analog_io[17]
    DIRECTION INOUT ;
    USE SIGNAL ;
    PORT
      LAYER met3 ;
        RECT 0.000000 3469.590000 0.800000 3469.890000 ;
    END
  END analog_io[17]
  PIN analog_io[16]
    DIRECTION INOUT ;
    USE SIGNAL ;
    PORT
      LAYER met2 ;
        RECT 244.880000 3469.555000 245.020000 3470.040000 ;
    END
  END analog_io[16]
  PIN analog_io[15]
    DIRECTION INOUT ;
    USE SIGNAL ;
    PORT
      LAYER met2 ;
        RECT 571.940000 3469.555000 572.080000 3470.040000 ;
    END
  END analog_io[15]
  PIN analog_io[14]
    DIRECTION INOUT ;
    USE SIGNAL ;
    PORT
      LAYER met2 ;
        RECT 898.540000 3469.555000 898.680000 3470.040000 ;
    END
  END analog_io[14]
  PIN analog_io[13]
    DIRECTION INOUT ;
    USE SIGNAL ;
    PORT
      LAYER met2 ;
        RECT 1225.140000 3469.555000 1225.280000 3470.040000 ;
    END
  END analog_io[13]
  PIN analog_io[12]
    DIRECTION INOUT ;
    USE SIGNAL ;
    PORT
      LAYER met2 ;
        RECT 1552.200000 3469.555000 1552.340000 3470.040000 ;
    END
  END analog_io[12]
  PIN analog_io[11]
    DIRECTION INOUT ;
    USE SIGNAL ;
    PORT
      LAYER met2 ;
        RECT 1878.800000 3469.555000 1878.940000 3470.040000 ;
    END
  END analog_io[11]
  PIN analog_io[10]
    DIRECTION INOUT ;
    USE SIGNAL ;
    PORT
      LAYER met2 ;
        RECT 2205.860000 3469.555000 2206.000000 3470.040000 ;
    END
  END analog_io[10]
  PIN analog_io[9]
    DIRECTION INOUT ;
    USE SIGNAL ;
    PORT
      LAYER met2 ;
        RECT 2532.460000 3469.555000 2532.600000 3470.040000 ;
    END
  END analog_io[9]
  PIN analog_io[8]
    DIRECTION INOUT ;
    USE SIGNAL ;
    PORT
      LAYER met2 ;
        RECT 2859.520000 3469.555000 2859.660000 3470.040000 ;
    END
  END analog_io[8]
  PIN analog_io[7]
    DIRECTION INOUT ;
    USE SIGNAL ;
    PORT
      LAYER met3 ;
        RECT 2859.020000 3269.510000 2859.820000 3269.810000 ;
    END
  END analog_io[7]
  PIN analog_io[6]
    DIRECTION INOUT ;
    USE SIGNAL ;
    PORT
      LAYER met3 ;
        RECT 2859.020000 3002.940000 2859.820000 3003.240000 ;
    END
  END analog_io[6]
  PIN analog_io[5]
    DIRECTION INOUT ;
    USE SIGNAL ;
    PORT
      LAYER met3 ;
        RECT 2859.020000 2735.760000 2859.820000 2736.060000 ;
    END
  END analog_io[5]
  PIN analog_io[4]
    DIRECTION INOUT ;
    USE SIGNAL ;
    PORT
      LAYER met3 ;
        RECT 2859.020000 2469.190000 2859.820000 2469.490000 ;
    END
  END analog_io[4]
  PIN analog_io[3]
    DIRECTION INOUT ;
    USE SIGNAL ;
    PORT
      LAYER met3 ;
        RECT 2859.020000 2202.620000 2859.820000 2202.920000 ;
    END
  END analog_io[3]
  PIN analog_io[2]
    DIRECTION INOUT ;
    USE SIGNAL ;
    PORT
      LAYER met3 ;
        RECT 2859.020000 1935.440000 2859.820000 1935.740000 ;
    END
  END analog_io[2]
  PIN analog_io[1]
    DIRECTION INOUT ;
    USE SIGNAL ;
    PORT
      LAYER met3 ;
        RECT 2859.020000 1668.870000 2859.820000 1669.170000 ;
    END
  END analog_io[1]
  PIN analog_io[0]
    DIRECTION INOUT ;
    USE SIGNAL ;
    PORT
      LAYER met3 ;
        RECT 2859.020000 1401.690000 2859.820000 1401.990000 ;
    END
  END analog_io[0]
  PIN user_clock2
    DIRECTION INPUT ;
    USE SIGNAL ;
    PORT
      LAYER met2 ;
        RECT 2842.500000 0.000000 2842.640000 0.485000 ;
    END
  END user_clock2
  PIN user_irq[2]
    DIRECTION OUTPUT ;
    USE SIGNAL ;
    PORT
      LAYER met2 ;
        RECT 2859.520000 0.000000 2859.660000 0.485000 ;
    END
  END user_irq[2]
  PIN user_irq[1]
    DIRECTION OUTPUT ;
    USE SIGNAL ;
    PORT
      LAYER met2 ;
        RECT 2854.000000 0.000000 2854.140000 0.485000 ;
    END
  END user_irq[1]
  PIN user_irq[0]
    DIRECTION OUTPUT ;
    USE SIGNAL ;
    PORT
      LAYER met2 ;
        RECT 2848.020000 0.000000 2848.160000 0.485000 ;
    END
  END user_irq[0]
  PIN vssd1
    DIRECTION INOUT ;
    USE GROUND ;
    PORT
      LAYER met5 ;
        RECT 2856.720000 3445.640000 2859.820000 3448.740000 ;
    END
    PORT
      LAYER met5 ;
        RECT 0.000000 3445.640000 3.100000 3448.740000 ;
    END
    PORT
      LAYER met5 ;
        RECT 2856.720000 19.260000 2859.820000 22.360000 ;
    END
    PORT
      LAYER met5 ;
        RECT 0.000000 19.260000 3.100000 22.360000 ;
    END
    PORT
      LAYER met4 ;
        RECT 2837.500000 3466.940000 2840.600000 3470.040000 ;
    END
    PORT
      LAYER met4 ;
        RECT 2837.500000 0.000000 2840.600000 3.100000 ;
    END
    PORT
      LAYER met4 ;
        RECT 19.220000 3466.940000 22.320000 3470.040000 ;
    END
    PORT
      LAYER met4 ;
        RECT 19.220000 0.000000 22.320000 3.100000 ;
    END

# P/G power stripe data as pin
    PORT
      LAYER met4 ;
        RECT 2690.000000 19.260000 2693.100000 3448.740000 ;
        RECT 2330.000000 19.260000 2333.100000 3448.740000 ;
        RECT 1970.000000 19.260000 1973.100000 3448.740000 ;
        RECT 1610.000000 19.260000 1613.100000 3448.740000 ;
        RECT 1250.000000 19.260000 1253.100000 3448.740000 ;
        RECT 890.000000 19.260000 893.100000 3448.740000 ;
        RECT 530.000000 19.260000 533.100000 3448.740000 ;
        RECT 170.000000 19.260000 173.100000 3448.740000 ;
        RECT 2510.000000 1407.920000 2513.100000 2090.600000 ;
        RECT 1790.000000 1407.920000 1793.100000 2090.600000 ;
        RECT 1070.000000 1407.920000 1073.100000 2090.600000 ;
        RECT 350.000000 1407.920000 353.100000 2090.600000 ;
        RECT 2837.500000 0.000000 2840.600000 3470.040000 ;
        RECT 19.220000 0.000000 22.320000 3470.040000 ;
        RECT 350.000000 19.260000 353.100000 355.600000 ;
        RECT 350.000000 539.920000 353.100000 789.600000 ;
        RECT 710.000000 19.260000 713.100000 789.600000 ;
        RECT 1070.000000 19.260000 1073.100000 355.600000 ;
        RECT 1070.000000 539.920000 1073.100000 789.600000 ;
        RECT 350.000000 973.920000 353.100000 1223.600000 ;
        RECT 710.000000 973.920000 713.100000 1657.600000 ;
        RECT 1070.000000 973.920000 1073.100000 1223.600000 ;
        RECT 1430.000000 19.260000 1433.100000 1657.600000 ;
        RECT 2150.000000 19.260000 2153.100000 789.600000 ;
        RECT 1790.000000 19.260000 1793.100000 355.600000 ;
        RECT 1790.000000 539.920000 1793.100000 789.600000 ;
        RECT 2510.000000 19.260000 2513.100000 355.600000 ;
        RECT 2510.000000 539.920000 2513.100000 789.600000 ;
        RECT 2150.000000 973.920000 2153.100000 1657.600000 ;
        RECT 1790.000000 973.920000 1793.100000 1223.600000 ;
        RECT 2510.000000 973.920000 2513.100000 1223.600000 ;
        RECT 350.000000 2274.920000 353.100000 2524.600000 ;
        RECT 710.000000 1841.920000 713.100000 2524.600000 ;
        RECT 1070.000000 2274.920000 1073.100000 2524.600000 ;
        RECT 350.000000 2708.920000 353.100000 2958.600000 ;
        RECT 350.000000 3142.920000 353.100000 3448.740000 ;
        RECT 710.000000 2708.920000 713.100000 3448.740000 ;
        RECT 1070.000000 2708.920000 1073.100000 2958.600000 ;
        RECT 1070.000000 3142.920000 1073.100000 3448.740000 ;
        RECT 1430.000000 1841.920000 1433.100000 3448.740000 ;
        RECT 2150.000000 1841.920000 2153.100000 2524.600000 ;
        RECT 1790.000000 2274.920000 1793.100000 2524.600000 ;
        RECT 2510.000000 2274.920000 2513.100000 2524.600000 ;
        RECT 2150.000000 2708.920000 2153.100000 3448.740000 ;
        RECT 1790.000000 2708.920000 1793.100000 2958.600000 ;
        RECT 1790.000000 3142.920000 1793.100000 3448.740000 ;
        RECT 2510.000000 2708.920000 2513.100000 2958.600000 ;
        RECT 2510.000000 3142.920000 2513.100000 3448.740000 ;
      LAYER met5 ;
        RECT 0.000000 19.260000 2859.820000 22.360000 ;
        RECT 0.000000 3445.640000 2859.820000 3448.740000 ;
    END
# end of P/G power stripe data as pin

  END vssd1
  PIN vccd1
    DIRECTION INOUT ;
    USE POWER ;
    PORT
      LAYER met5 ;
        RECT 2856.720000 3439.440000 2859.820000 3442.540000 ;
    END
    PORT
      LAYER met5 ;
        RECT 0.000000 3439.440000 3.100000 3442.540000 ;
    END
    PORT
      LAYER met5 ;
        RECT 2856.720000 25.460000 2859.820000 28.560000 ;
    END
    PORT
      LAYER met5 ;
        RECT 0.000000 25.460000 3.100000 28.560000 ;
    END
    PORT
      LAYER met4 ;
        RECT 2831.300000 3466.940000 2834.400000 3470.040000 ;
    END
    PORT
      LAYER met4 ;
        RECT 2831.300000 0.000000 2834.400000 3.100000 ;
    END
    PORT
      LAYER met4 ;
        RECT 25.420000 3466.940000 28.520000 3470.040000 ;
    END
    PORT
      LAYER met4 ;
        RECT 25.420000 0.000000 28.520000 3.100000 ;
    END

# P/G power stripe data as pin
    PORT
      LAYER met4 ;
        RECT 2783.100000 25.460000 2786.200000 3442.540000 ;
        RECT 2423.100000 25.460000 2426.200000 3442.540000 ;
        RECT 2063.100000 25.460000 2066.200000 3442.540000 ;
        RECT 1703.100000 25.460000 1706.200000 3442.540000 ;
        RECT 1343.100000 25.460000 1346.200000 3442.540000 ;
        RECT 983.100000 25.460000 986.200000 3442.540000 ;
        RECT 623.100000 25.460000 626.200000 3442.540000 ;
        RECT 263.100000 25.460000 266.200000 3442.540000 ;
        RECT 2603.100000 1407.920000 2606.200000 2090.600000 ;
        RECT 1883.100000 1407.920000 1886.200000 2090.600000 ;
        RECT 1163.100000 1407.920000 1166.200000 2090.600000 ;
        RECT 443.100000 1407.920000 446.200000 2090.600000 ;
        RECT 2831.300000 0.000000 2834.400000 3470.040000 ;
        RECT 25.420000 0.000000 28.520000 3470.040000 ;
        RECT 443.100000 25.460000 446.200000 355.600000 ;
        RECT 443.100000 539.920000 446.200000 789.600000 ;
        RECT 803.100000 25.460000 806.200000 789.600000 ;
        RECT 1163.100000 25.460000 1166.200000 355.600000 ;
        RECT 1163.100000 539.920000 1166.200000 789.600000 ;
        RECT 443.100000 973.920000 446.200000 1223.600000 ;
        RECT 803.100000 973.920000 806.200000 1657.600000 ;
        RECT 1163.100000 973.920000 1166.200000 1223.600000 ;
        RECT 1523.100000 25.460000 1526.200000 1657.600000 ;
        RECT 2243.100000 25.460000 2246.200000 789.600000 ;
        RECT 1883.100000 25.460000 1886.200000 355.600000 ;
        RECT 1883.100000 539.920000 1886.200000 789.600000 ;
        RECT 2603.100000 25.460000 2606.200000 355.600000 ;
        RECT 2603.100000 539.920000 2606.200000 789.600000 ;
        RECT 2243.100000 973.920000 2246.200000 1657.600000 ;
        RECT 1883.100000 973.920000 1886.200000 1223.600000 ;
        RECT 2603.100000 973.920000 2606.200000 1223.600000 ;
        RECT 443.100000 2274.920000 446.200000 2524.600000 ;
        RECT 803.100000 1841.920000 806.200000 2524.600000 ;
        RECT 1163.100000 2274.920000 1166.200000 2524.600000 ;
        RECT 443.100000 2708.920000 446.200000 2958.600000 ;
        RECT 443.100000 3142.920000 446.200000 3442.540000 ;
        RECT 803.100000 2708.920000 806.200000 3442.540000 ;
        RECT 1163.100000 2708.920000 1166.200000 2958.600000 ;
        RECT 1163.100000 3142.920000 1166.200000 3442.540000 ;
        RECT 1523.100000 1841.920000 1526.200000 3442.540000 ;
        RECT 2243.100000 1841.920000 2246.200000 2524.600000 ;
        RECT 1883.100000 2274.920000 1886.200000 2524.600000 ;
        RECT 2603.100000 2274.920000 2606.200000 2524.600000 ;
        RECT 2243.100000 2708.920000 2246.200000 3442.540000 ;
        RECT 1883.100000 2708.920000 1886.200000 2958.600000 ;
        RECT 1883.100000 3142.920000 1886.200000 3442.540000 ;
        RECT 2603.100000 2708.920000 2606.200000 2958.600000 ;
        RECT 2603.100000 3142.920000 2606.200000 3442.540000 ;
      LAYER met5 ;
        RECT 0.000000 25.460000 2859.820000 28.560000 ;
        RECT 0.000000 3439.440000 2859.820000 3442.540000 ;
    END
# end of P/G power stripe data as pin

  END vccd1
  OBS
    LAYER li1 ;
      RECT 0.000000 0.000000 2859.820000 3470.040000 ;
    LAYER met1 ;
      RECT 0.000000 0.000000 2859.820000 3470.040000 ;
    LAYER met2 ;
      RECT 2778.060000 3469.275000 2859.240000 3470.040000 ;
      RECT 2696.180000 3469.275000 2777.360000 3470.040000 ;
      RECT 2614.760000 3469.275000 2695.480000 3470.040000 ;
      RECT 2532.880000 3469.275000 2614.060000 3470.040000 ;
      RECT 2451.460000 3469.275000 2532.180000 3470.040000 ;
      RECT 2369.580000 3469.275000 2450.760000 3470.040000 ;
      RECT 2287.700000 3469.275000 2368.880000 3470.040000 ;
      RECT 2206.280000 3469.275000 2287.000000 3470.040000 ;
      RECT 2124.400000 3469.275000 2205.580000 3470.040000 ;
      RECT 2042.520000 3469.275000 2123.700000 3470.040000 ;
      RECT 1961.100000 3469.275000 2041.820000 3470.040000 ;
      RECT 1879.220000 3469.275000 1960.400000 3470.040000 ;
      RECT 1797.800000 3469.275000 1878.520000 3470.040000 ;
      RECT 1715.920000 3469.275000 1797.100000 3470.040000 ;
      RECT 1634.040000 3469.275000 1715.220000 3470.040000 ;
      RECT 1552.620000 3469.275000 1633.340000 3470.040000 ;
      RECT 1470.740000 3469.275000 1551.920000 3470.040000 ;
      RECT 1389.320000 3469.275000 1470.040000 3470.040000 ;
      RECT 1307.440000 3469.275000 1388.620000 3470.040000 ;
      RECT 1225.560000 3469.275000 1306.740000 3470.040000 ;
      RECT 1144.140000 3469.275000 1224.860000 3470.040000 ;
      RECT 1062.260000 3469.275000 1143.440000 3470.040000 ;
      RECT 980.840000 3469.275000 1061.560000 3470.040000 ;
      RECT 898.960000 3469.275000 980.140000 3470.040000 ;
      RECT 817.080000 3469.275000 898.260000 3470.040000 ;
      RECT 735.660000 3469.275000 816.380000 3470.040000 ;
      RECT 653.780000 3469.275000 734.960000 3470.040000 ;
      RECT 572.360000 3469.275000 653.080000 3470.040000 ;
      RECT 490.480000 3469.275000 571.660000 3470.040000 ;
      RECT 409.060000 3469.275000 489.780000 3470.040000 ;
      RECT 327.180000 3469.275000 408.360000 3470.040000 ;
      RECT 245.300000 3469.275000 326.480000 3470.040000 ;
      RECT 163.880000 3469.275000 244.600000 3470.040000 ;
      RECT 82.000000 3469.275000 163.180000 3470.040000 ;
      RECT 0.580000 3469.275000 81.300000 3470.040000 ;
      RECT 0.000000 0.765000 2859.820000 3469.275000 ;
      RECT 2854.420000 0.000000 2859.240000 0.765000 ;
      RECT 2848.440000 0.000000 2853.720000 0.765000 ;
      RECT 2842.920000 0.000000 2847.740000 0.765000 ;
      RECT 2836.940000 0.000000 2842.220000 0.765000 ;
      RECT 2830.960000 0.000000 2836.240000 0.765000 ;
      RECT 2825.440000 0.000000 2830.260000 0.765000 ;
      RECT 2819.460000 0.000000 2824.740000 0.765000 ;
      RECT 2813.940000 0.000000 2818.760000 0.765000 ;
      RECT 2807.960000 0.000000 2813.240000 0.765000 ;
      RECT 2801.980000 0.000000 2807.260000 0.765000 ;
      RECT 2796.460000 0.000000 2801.280000 0.765000 ;
      RECT 2790.480000 0.000000 2795.760000 0.765000 ;
      RECT 2784.960000 0.000000 2789.780000 0.765000 ;
      RECT 2778.980000 0.000000 2784.260000 0.765000 ;
      RECT 2773.000000 0.000000 2778.280000 0.765000 ;
      RECT 2767.480000 0.000000 2772.300000 0.765000 ;
      RECT 2761.500000 0.000000 2766.780000 0.765000 ;
      RECT 2755.980000 0.000000 2760.800000 0.765000 ;
      RECT 2750.000000 0.000000 2755.280000 0.765000 ;
      RECT 2744.020000 0.000000 2749.300000 0.765000 ;
      RECT 2738.500000 0.000000 2743.320000 0.765000 ;
      RECT 2732.520000 0.000000 2737.800000 0.765000 ;
      RECT 2727.000000 0.000000 2731.820000 0.765000 ;
      RECT 2721.020000 0.000000 2726.300000 0.765000 ;
      RECT 2715.040000 0.000000 2720.320000 0.765000 ;
      RECT 2709.520000 0.000000 2714.340000 0.765000 ;
      RECT 2703.540000 0.000000 2708.820000 0.765000 ;
      RECT 2697.560000 0.000000 2702.840000 0.765000 ;
      RECT 2692.040000 0.000000 2696.860000 0.765000 ;
      RECT 2686.060000 0.000000 2691.340000 0.765000 ;
      RECT 2680.540000 0.000000 2685.360000 0.765000 ;
      RECT 2674.560000 0.000000 2679.840000 0.765000 ;
      RECT 2668.580000 0.000000 2673.860000 0.765000 ;
      RECT 2663.060000 0.000000 2667.880000 0.765000 ;
      RECT 2657.080000 0.000000 2662.360000 0.765000 ;
      RECT 2651.560000 0.000000 2656.380000 0.765000 ;
      RECT 2645.580000 0.000000 2650.860000 0.765000 ;
      RECT 2639.600000 0.000000 2644.880000 0.765000 ;
      RECT 2634.080000 0.000000 2638.900000 0.765000 ;
      RECT 2628.100000 0.000000 2633.380000 0.765000 ;
      RECT 2622.580000 0.000000 2627.400000 0.765000 ;
      RECT 2616.600000 0.000000 2621.880000 0.765000 ;
      RECT 2610.620000 0.000000 2615.900000 0.765000 ;
      RECT 2605.100000 0.000000 2609.920000 0.765000 ;
      RECT 2599.120000 0.000000 2604.400000 0.765000 ;
      RECT 2593.600000 0.000000 2598.420000 0.765000 ;
      RECT 2587.620000 0.000000 2592.900000 0.765000 ;
      RECT 2581.640000 0.000000 2586.920000 0.765000 ;
      RECT 2576.120000 0.000000 2580.940000 0.765000 ;
      RECT 2570.140000 0.000000 2575.420000 0.765000 ;
      RECT 2564.160000 0.000000 2569.440000 0.765000 ;
      RECT 2558.640000 0.000000 2563.460000 0.765000 ;
      RECT 2552.660000 0.000000 2557.940000 0.765000 ;
      RECT 2547.140000 0.000000 2551.960000 0.765000 ;
      RECT 2541.160000 0.000000 2546.440000 0.765000 ;
      RECT 2535.180000 0.000000 2540.460000 0.765000 ;
      RECT 2529.660000 0.000000 2534.480000 0.765000 ;
      RECT 2523.680000 0.000000 2528.960000 0.765000 ;
      RECT 2518.160000 0.000000 2522.980000 0.765000 ;
      RECT 2512.180000 0.000000 2517.460000 0.765000 ;
      RECT 2506.200000 0.000000 2511.480000 0.765000 ;
      RECT 2500.680000 0.000000 2505.500000 0.765000 ;
      RECT 2494.700000 0.000000 2499.980000 0.765000 ;
      RECT 2489.180000 0.000000 2494.000000 0.765000 ;
      RECT 2483.200000 0.000000 2488.480000 0.765000 ;
      RECT 2477.220000 0.000000 2482.500000 0.765000 ;
      RECT 2471.700000 0.000000 2476.520000 0.765000 ;
      RECT 2465.720000 0.000000 2471.000000 0.765000 ;
      RECT 2460.200000 0.000000 2465.020000 0.765000 ;
      RECT 2454.220000 0.000000 2459.500000 0.765000 ;
      RECT 2448.240000 0.000000 2453.520000 0.765000 ;
      RECT 2442.720000 0.000000 2447.540000 0.765000 ;
      RECT 2436.740000 0.000000 2442.020000 0.765000 ;
      RECT 2430.760000 0.000000 2436.040000 0.765000 ;
      RECT 2425.240000 0.000000 2430.060000 0.765000 ;
      RECT 2419.260000 0.000000 2424.540000 0.765000 ;
      RECT 2413.740000 0.000000 2418.560000 0.765000 ;
      RECT 2407.760000 0.000000 2413.040000 0.765000 ;
      RECT 2401.780000 0.000000 2407.060000 0.765000 ;
      RECT 2396.260000 0.000000 2401.080000 0.765000 ;
      RECT 2390.280000 0.000000 2395.560000 0.765000 ;
      RECT 2384.760000 0.000000 2389.580000 0.765000 ;
      RECT 2378.780000 0.000000 2384.060000 0.765000 ;
      RECT 2372.800000 0.000000 2378.080000 0.765000 ;
      RECT 2367.280000 0.000000 2372.100000 0.765000 ;
      RECT 2361.300000 0.000000 2366.580000 0.765000 ;
      RECT 2355.780000 0.000000 2360.600000 0.765000 ;
      RECT 2349.800000 0.000000 2355.080000 0.765000 ;
      RECT 2343.820000 0.000000 2349.100000 0.765000 ;
      RECT 2338.300000 0.000000 2343.120000 0.765000 ;
      RECT 2332.320000 0.000000 2337.600000 0.765000 ;
      RECT 2326.800000 0.000000 2331.620000 0.765000 ;
      RECT 2320.820000 0.000000 2326.100000 0.765000 ;
      RECT 2314.840000 0.000000 2320.120000 0.765000 ;
      RECT 2309.320000 0.000000 2314.140000 0.765000 ;
      RECT 2303.340000 0.000000 2308.620000 0.765000 ;
      RECT 2297.360000 0.000000 2302.640000 0.765000 ;
      RECT 2291.840000 0.000000 2296.660000 0.765000 ;
      RECT 2285.860000 0.000000 2291.140000 0.765000 ;
      RECT 2280.340000 0.000000 2285.160000 0.765000 ;
      RECT 2274.360000 0.000000 2279.640000 0.765000 ;
      RECT 2268.380000 0.000000 2273.660000 0.765000 ;
      RECT 2262.860000 0.000000 2267.680000 0.765000 ;
      RECT 2256.880000 0.000000 2262.160000 0.765000 ;
      RECT 2251.360000 0.000000 2256.180000 0.765000 ;
      RECT 2245.380000 0.000000 2250.660000 0.765000 ;
      RECT 2239.400000 0.000000 2244.680000 0.765000 ;
      RECT 2233.880000 0.000000 2238.700000 0.765000 ;
      RECT 2227.900000 0.000000 2233.180000 0.765000 ;
      RECT 2222.380000 0.000000 2227.200000 0.765000 ;
      RECT 2216.400000 0.000000 2221.680000 0.765000 ;
      RECT 2210.420000 0.000000 2215.700000 0.765000 ;
      RECT 2204.900000 0.000000 2209.720000 0.765000 ;
      RECT 2198.920000 0.000000 2204.200000 0.765000 ;
      RECT 2193.400000 0.000000 2198.220000 0.765000 ;
      RECT 2187.420000 0.000000 2192.700000 0.765000 ;
      RECT 2181.440000 0.000000 2186.720000 0.765000 ;
      RECT 2175.920000 0.000000 2180.740000 0.765000 ;
      RECT 2169.940000 0.000000 2175.220000 0.765000 ;
      RECT 2163.960000 0.000000 2169.240000 0.765000 ;
      RECT 2158.440000 0.000000 2163.260000 0.765000 ;
      RECT 2152.460000 0.000000 2157.740000 0.765000 ;
      RECT 2146.940000 0.000000 2151.760000 0.765000 ;
      RECT 2140.960000 0.000000 2146.240000 0.765000 ;
      RECT 2134.980000 0.000000 2140.260000 0.765000 ;
      RECT 2129.460000 0.000000 2134.280000 0.765000 ;
      RECT 2123.480000 0.000000 2128.760000 0.765000 ;
      RECT 2117.960000 0.000000 2122.780000 0.765000 ;
      RECT 2111.980000 0.000000 2117.260000 0.765000 ;
      RECT 2106.000000 0.000000 2111.280000 0.765000 ;
      RECT 2100.480000 0.000000 2105.300000 0.765000 ;
      RECT 2094.500000 0.000000 2099.780000 0.765000 ;
      RECT 2088.980000 0.000000 2093.800000 0.765000 ;
      RECT 2083.000000 0.000000 2088.280000 0.765000 ;
      RECT 2077.020000 0.000000 2082.300000 0.765000 ;
      RECT 2071.500000 0.000000 2076.320000 0.765000 ;
      RECT 2065.520000 0.000000 2070.800000 0.765000 ;
      RECT 2060.000000 0.000000 2064.820000 0.765000 ;
      RECT 2054.020000 0.000000 2059.300000 0.765000 ;
      RECT 2048.040000 0.000000 2053.320000 0.765000 ;
      RECT 2042.520000 0.000000 2047.340000 0.765000 ;
      RECT 2036.540000 0.000000 2041.820000 0.765000 ;
      RECT 2030.560000 0.000000 2035.840000 0.765000 ;
      RECT 2025.040000 0.000000 2029.860000 0.765000 ;
      RECT 2019.060000 0.000000 2024.340000 0.765000 ;
      RECT 2013.540000 0.000000 2018.360000 0.765000 ;
      RECT 2007.560000 0.000000 2012.840000 0.765000 ;
      RECT 2001.580000 0.000000 2006.860000 0.765000 ;
      RECT 1996.060000 0.000000 2000.880000 0.765000 ;
      RECT 1990.080000 0.000000 1995.360000 0.765000 ;
      RECT 1984.560000 0.000000 1989.380000 0.765000 ;
      RECT 1978.580000 0.000000 1983.860000 0.765000 ;
      RECT 1972.600000 0.000000 1977.880000 0.765000 ;
      RECT 1967.080000 0.000000 1971.900000 0.765000 ;
      RECT 1961.100000 0.000000 1966.380000 0.765000 ;
      RECT 1955.580000 0.000000 1960.400000 0.765000 ;
      RECT 1949.600000 0.000000 1954.880000 0.765000 ;
      RECT 1943.620000 0.000000 1948.900000 0.765000 ;
      RECT 1938.100000 0.000000 1942.920000 0.765000 ;
      RECT 1932.120000 0.000000 1937.400000 0.765000 ;
      RECT 1926.600000 0.000000 1931.420000 0.765000 ;
      RECT 1920.620000 0.000000 1925.900000 0.765000 ;
      RECT 1914.640000 0.000000 1919.920000 0.765000 ;
      RECT 1909.120000 0.000000 1913.940000 0.765000 ;
      RECT 1903.140000 0.000000 1908.420000 0.765000 ;
      RECT 1897.160000 0.000000 1902.440000 0.765000 ;
      RECT 1891.640000 0.000000 1896.460000 0.765000 ;
      RECT 1885.660000 0.000000 1890.940000 0.765000 ;
      RECT 1880.140000 0.000000 1884.960000 0.765000 ;
      RECT 1874.160000 0.000000 1879.440000 0.765000 ;
      RECT 1868.180000 0.000000 1873.460000 0.765000 ;
      RECT 1862.660000 0.000000 1867.480000 0.765000 ;
      RECT 1856.680000 0.000000 1861.960000 0.765000 ;
      RECT 1851.160000 0.000000 1855.980000 0.765000 ;
      RECT 1845.180000 0.000000 1850.460000 0.765000 ;
      RECT 1839.200000 0.000000 1844.480000 0.765000 ;
      RECT 1833.680000 0.000000 1838.500000 0.765000 ;
      RECT 1827.700000 0.000000 1832.980000 0.765000 ;
      RECT 1822.180000 0.000000 1827.000000 0.765000 ;
      RECT 1816.200000 0.000000 1821.480000 0.765000 ;
      RECT 1810.220000 0.000000 1815.500000 0.765000 ;
      RECT 1804.700000 0.000000 1809.520000 0.765000 ;
      RECT 1798.720000 0.000000 1804.000000 0.765000 ;
      RECT 1793.200000 0.000000 1798.020000 0.765000 ;
      RECT 1787.220000 0.000000 1792.500000 0.765000 ;
      RECT 1781.240000 0.000000 1786.520000 0.765000 ;
      RECT 1775.720000 0.000000 1780.540000 0.765000 ;
      RECT 1769.740000 0.000000 1775.020000 0.765000 ;
      RECT 1763.760000 0.000000 1769.040000 0.765000 ;
      RECT 1758.240000 0.000000 1763.060000 0.765000 ;
      RECT 1752.260000 0.000000 1757.540000 0.765000 ;
      RECT 1746.740000 0.000000 1751.560000 0.765000 ;
      RECT 1740.760000 0.000000 1746.040000 0.765000 ;
      RECT 1734.780000 0.000000 1740.060000 0.765000 ;
      RECT 1729.260000 0.000000 1734.080000 0.765000 ;
      RECT 1723.280000 0.000000 1728.560000 0.765000 ;
      RECT 1717.760000 0.000000 1722.580000 0.765000 ;
      RECT 1711.780000 0.000000 1717.060000 0.765000 ;
      RECT 1705.800000 0.000000 1711.080000 0.765000 ;
      RECT 1700.280000 0.000000 1705.100000 0.765000 ;
      RECT 1694.300000 0.000000 1699.580000 0.765000 ;
      RECT 1688.780000 0.000000 1693.600000 0.765000 ;
      RECT 1682.800000 0.000000 1688.080000 0.765000 ;
      RECT 1676.820000 0.000000 1682.100000 0.765000 ;
      RECT 1671.300000 0.000000 1676.120000 0.765000 ;
      RECT 1665.320000 0.000000 1670.600000 0.765000 ;
      RECT 1659.800000 0.000000 1664.620000 0.765000 ;
      RECT 1653.820000 0.000000 1659.100000 0.765000 ;
      RECT 1647.840000 0.000000 1653.120000 0.765000 ;
      RECT 1642.320000 0.000000 1647.140000 0.765000 ;
      RECT 1636.340000 0.000000 1641.620000 0.765000 ;
      RECT 1630.360000 0.000000 1635.640000 0.765000 ;
      RECT 1624.840000 0.000000 1629.660000 0.765000 ;
      RECT 1618.860000 0.000000 1624.140000 0.765000 ;
      RECT 1613.340000 0.000000 1618.160000 0.765000 ;
      RECT 1607.360000 0.000000 1612.640000 0.765000 ;
      RECT 1601.380000 0.000000 1606.660000 0.765000 ;
      RECT 1595.860000 0.000000 1600.680000 0.765000 ;
      RECT 1589.880000 0.000000 1595.160000 0.765000 ;
      RECT 1584.360000 0.000000 1589.180000 0.765000 ;
      RECT 1578.380000 0.000000 1583.660000 0.765000 ;
      RECT 1572.400000 0.000000 1577.680000 0.765000 ;
      RECT 1566.880000 0.000000 1571.700000 0.765000 ;
      RECT 1560.900000 0.000000 1566.180000 0.765000 ;
      RECT 1555.380000 0.000000 1560.200000 0.765000 ;
      RECT 1549.400000 0.000000 1554.680000 0.765000 ;
      RECT 1543.420000 0.000000 1548.700000 0.765000 ;
      RECT 1537.900000 0.000000 1542.720000 0.765000 ;
      RECT 1531.920000 0.000000 1537.200000 0.765000 ;
      RECT 1526.400000 0.000000 1531.220000 0.765000 ;
      RECT 1520.420000 0.000000 1525.700000 0.765000 ;
      RECT 1514.440000 0.000000 1519.720000 0.765000 ;
      RECT 1508.920000 0.000000 1513.740000 0.765000 ;
      RECT 1502.940000 0.000000 1508.220000 0.765000 ;
      RECT 1496.960000 0.000000 1502.240000 0.765000 ;
      RECT 1491.440000 0.000000 1496.260000 0.765000 ;
      RECT 1485.460000 0.000000 1490.740000 0.765000 ;
      RECT 1479.940000 0.000000 1484.760000 0.765000 ;
      RECT 1473.960000 0.000000 1479.240000 0.765000 ;
      RECT 1467.980000 0.000000 1473.260000 0.765000 ;
      RECT 1462.460000 0.000000 1467.280000 0.765000 ;
      RECT 1456.480000 0.000000 1461.760000 0.765000 ;
      RECT 1450.960000 0.000000 1455.780000 0.765000 ;
      RECT 1444.980000 0.000000 1450.260000 0.765000 ;
      RECT 1439.000000 0.000000 1444.280000 0.765000 ;
      RECT 1433.480000 0.000000 1438.300000 0.765000 ;
      RECT 1427.500000 0.000000 1432.780000 0.765000 ;
      RECT 1421.980000 0.000000 1426.800000 0.765000 ;
      RECT 1416.000000 0.000000 1421.280000 0.765000 ;
      RECT 1410.020000 0.000000 1415.300000 0.765000 ;
      RECT 1404.500000 0.000000 1409.320000 0.765000 ;
      RECT 1398.520000 0.000000 1403.800000 0.765000 ;
      RECT 1393.000000 0.000000 1397.820000 0.765000 ;
      RECT 1387.020000 0.000000 1392.300000 0.765000 ;
      RECT 1381.040000 0.000000 1386.320000 0.765000 ;
      RECT 1375.520000 0.000000 1380.340000 0.765000 ;
      RECT 1369.540000 0.000000 1374.820000 0.765000 ;
      RECT 1364.020000 0.000000 1368.840000 0.765000 ;
      RECT 1358.040000 0.000000 1363.320000 0.765000 ;
      RECT 1352.060000 0.000000 1357.340000 0.765000 ;
      RECT 1346.540000 0.000000 1351.360000 0.765000 ;
      RECT 1340.560000 0.000000 1345.840000 0.765000 ;
      RECT 1334.580000 0.000000 1339.860000 0.765000 ;
      RECT 1329.060000 0.000000 1333.880000 0.765000 ;
      RECT 1323.080000 0.000000 1328.360000 0.765000 ;
      RECT 1317.560000 0.000000 1322.380000 0.765000 ;
      RECT 1311.580000 0.000000 1316.860000 0.765000 ;
      RECT 1305.600000 0.000000 1310.880000 0.765000 ;
      RECT 1300.080000 0.000000 1304.900000 0.765000 ;
      RECT 1294.100000 0.000000 1299.380000 0.765000 ;
      RECT 1288.580000 0.000000 1293.400000 0.765000 ;
      RECT 1282.600000 0.000000 1287.880000 0.765000 ;
      RECT 1276.620000 0.000000 1281.900000 0.765000 ;
      RECT 1271.100000 0.000000 1275.920000 0.765000 ;
      RECT 1265.120000 0.000000 1270.400000 0.765000 ;
      RECT 1259.600000 0.000000 1264.420000 0.765000 ;
      RECT 1253.620000 0.000000 1258.900000 0.765000 ;
      RECT 1247.640000 0.000000 1252.920000 0.765000 ;
      RECT 1242.120000 0.000000 1246.940000 0.765000 ;
      RECT 1236.140000 0.000000 1241.420000 0.765000 ;
      RECT 1230.620000 0.000000 1235.440000 0.765000 ;
      RECT 1224.640000 0.000000 1229.920000 0.765000 ;
      RECT 1218.660000 0.000000 1223.940000 0.765000 ;
      RECT 1213.140000 0.000000 1217.960000 0.765000 ;
      RECT 1207.160000 0.000000 1212.440000 0.765000 ;
      RECT 1201.180000 0.000000 1206.460000 0.765000 ;
      RECT 1195.660000 0.000000 1200.480000 0.765000 ;
      RECT 1189.680000 0.000000 1194.960000 0.765000 ;
      RECT 1184.160000 0.000000 1188.980000 0.765000 ;
      RECT 1178.180000 0.000000 1183.460000 0.765000 ;
      RECT 1172.200000 0.000000 1177.480000 0.765000 ;
      RECT 1166.680000 0.000000 1171.500000 0.765000 ;
      RECT 1160.700000 0.000000 1165.980000 0.765000 ;
      RECT 1155.180000 0.000000 1160.000000 0.765000 ;
      RECT 1149.200000 0.000000 1154.480000 0.765000 ;
      RECT 1143.220000 0.000000 1148.500000 0.765000 ;
      RECT 1137.700000 0.000000 1142.520000 0.765000 ;
      RECT 1131.720000 0.000000 1137.000000 0.765000 ;
      RECT 1126.200000 0.000000 1131.020000 0.765000 ;
      RECT 1120.220000 0.000000 1125.500000 0.765000 ;
      RECT 1114.240000 0.000000 1119.520000 0.765000 ;
      RECT 1108.720000 0.000000 1113.540000 0.765000 ;
      RECT 1102.740000 0.000000 1108.020000 0.765000 ;
      RECT 1097.220000 0.000000 1102.040000 0.765000 ;
      RECT 1091.240000 0.000000 1096.520000 0.765000 ;
      RECT 1085.260000 0.000000 1090.540000 0.765000 ;
      RECT 1079.740000 0.000000 1084.560000 0.765000 ;
      RECT 1073.760000 0.000000 1079.040000 0.765000 ;
      RECT 1067.780000 0.000000 1073.060000 0.765000 ;
      RECT 1062.260000 0.000000 1067.080000 0.765000 ;
      RECT 1056.280000 0.000000 1061.560000 0.765000 ;
      RECT 1050.760000 0.000000 1055.580000 0.765000 ;
      RECT 1044.780000 0.000000 1050.060000 0.765000 ;
      RECT 1038.800000 0.000000 1044.080000 0.765000 ;
      RECT 1033.280000 0.000000 1038.100000 0.765000 ;
      RECT 1027.300000 0.000000 1032.580000 0.765000 ;
      RECT 1021.780000 0.000000 1026.600000 0.765000 ;
      RECT 1015.800000 0.000000 1021.080000 0.765000 ;
      RECT 1009.820000 0.000000 1015.100000 0.765000 ;
      RECT 1004.300000 0.000000 1009.120000 0.765000 ;
      RECT 998.320000 0.000000 1003.600000 0.765000 ;
      RECT 992.800000 0.000000 997.620000 0.765000 ;
      RECT 986.820000 0.000000 992.100000 0.765000 ;
      RECT 980.840000 0.000000 986.120000 0.765000 ;
      RECT 975.320000 0.000000 980.140000 0.765000 ;
      RECT 969.340000 0.000000 974.620000 0.765000 ;
      RECT 963.820000 0.000000 968.640000 0.765000 ;
      RECT 957.840000 0.000000 963.120000 0.765000 ;
      RECT 951.860000 0.000000 957.140000 0.765000 ;
      RECT 946.340000 0.000000 951.160000 0.765000 ;
      RECT 940.360000 0.000000 945.640000 0.765000 ;
      RECT 934.380000 0.000000 939.660000 0.765000 ;
      RECT 928.860000 0.000000 933.680000 0.765000 ;
      RECT 922.880000 0.000000 928.160000 0.765000 ;
      RECT 917.360000 0.000000 922.180000 0.765000 ;
      RECT 911.380000 0.000000 916.660000 0.765000 ;
      RECT 905.400000 0.000000 910.680000 0.765000 ;
      RECT 899.880000 0.000000 904.700000 0.765000 ;
      RECT 893.900000 0.000000 899.180000 0.765000 ;
      RECT 888.380000 0.000000 893.200000 0.765000 ;
      RECT 882.400000 0.000000 887.680000 0.765000 ;
      RECT 876.420000 0.000000 881.700000 0.765000 ;
      RECT 870.900000 0.000000 875.720000 0.765000 ;
      RECT 864.920000 0.000000 870.200000 0.765000 ;
      RECT 859.400000 0.000000 864.220000 0.765000 ;
      RECT 853.420000 0.000000 858.700000 0.765000 ;
      RECT 847.440000 0.000000 852.720000 0.765000 ;
      RECT 841.920000 0.000000 846.740000 0.765000 ;
      RECT 835.940000 0.000000 841.220000 0.765000 ;
      RECT 830.420000 0.000000 835.240000 0.765000 ;
      RECT 824.440000 0.000000 829.720000 0.765000 ;
      RECT 818.460000 0.000000 823.740000 0.765000 ;
      RECT 812.940000 0.000000 817.760000 0.765000 ;
      RECT 806.960000 0.000000 812.240000 0.765000 ;
      RECT 800.980000 0.000000 806.260000 0.765000 ;
      RECT 795.460000 0.000000 800.280000 0.765000 ;
      RECT 789.480000 0.000000 794.760000 0.765000 ;
      RECT 783.960000 0.000000 788.780000 0.765000 ;
      RECT 777.980000 0.000000 783.260000 0.765000 ;
      RECT 772.000000 0.000000 777.280000 0.765000 ;
      RECT 766.480000 0.000000 771.300000 0.765000 ;
      RECT 760.500000 0.000000 765.780000 0.765000 ;
      RECT 754.980000 0.000000 759.800000 0.765000 ;
      RECT 749.000000 0.000000 754.280000 0.765000 ;
      RECT 743.020000 0.000000 748.300000 0.765000 ;
      RECT 737.500000 0.000000 742.320000 0.765000 ;
      RECT 731.520000 0.000000 736.800000 0.765000 ;
      RECT 726.000000 0.000000 730.820000 0.765000 ;
      RECT 720.020000 0.000000 725.300000 0.765000 ;
      RECT 714.040000 0.000000 719.320000 0.765000 ;
      RECT 708.520000 0.000000 713.340000 0.765000 ;
      RECT 702.540000 0.000000 707.820000 0.765000 ;
      RECT 697.020000 0.000000 701.840000 0.765000 ;
      RECT 691.040000 0.000000 696.320000 0.765000 ;
      RECT 685.060000 0.000000 690.340000 0.765000 ;
      RECT 679.540000 0.000000 684.360000 0.765000 ;
      RECT 673.560000 0.000000 678.840000 0.765000 ;
      RECT 667.580000 0.000000 672.860000 0.765000 ;
      RECT 662.060000 0.000000 666.880000 0.765000 ;
      RECT 656.080000 0.000000 661.360000 0.765000 ;
      RECT 650.560000 0.000000 655.380000 0.765000 ;
      RECT 644.580000 0.000000 649.860000 0.765000 ;
      RECT 638.600000 0.000000 643.880000 0.765000 ;
      RECT 633.080000 0.000000 637.900000 0.765000 ;
      RECT 627.100000 0.000000 632.380000 0.765000 ;
      RECT 621.580000 0.000000 626.400000 0.765000 ;
      RECT 615.600000 0.000000 620.880000 0.765000 ;
      RECT 609.620000 0.000000 614.900000 0.765000 ;
      RECT 604.100000 0.000000 608.920000 0.765000 ;
      RECT 598.120000 0.000000 603.400000 0.765000 ;
      RECT 592.600000 0.000000 597.420000 0.765000 ;
      RECT 586.620000 0.000000 591.900000 0.765000 ;
      RECT 580.640000 0.000000 585.920000 0.765000 ;
      RECT 575.120000 0.000000 579.940000 0.765000 ;
      RECT 569.140000 0.000000 574.420000 0.765000 ;
      RECT 563.620000 0.000000 568.440000 0.765000 ;
      RECT 557.640000 0.000000 562.920000 0.765000 ;
      RECT 551.660000 0.000000 556.940000 0.765000 ;
      RECT 546.140000 0.000000 550.960000 0.765000 ;
      RECT 540.160000 0.000000 545.440000 0.765000 ;
      RECT 534.180000 0.000000 539.460000 0.765000 ;
      RECT 528.660000 0.000000 533.480000 0.765000 ;
      RECT 522.680000 0.000000 527.960000 0.765000 ;
      RECT 517.160000 0.000000 521.980000 0.765000 ;
      RECT 511.180000 0.000000 516.460000 0.765000 ;
      RECT 505.200000 0.000000 510.480000 0.765000 ;
      RECT 499.680000 0.000000 504.500000 0.765000 ;
      RECT 493.700000 0.000000 498.980000 0.765000 ;
      RECT 488.180000 0.000000 493.000000 0.765000 ;
      RECT 482.200000 0.000000 487.480000 0.765000 ;
      RECT 476.220000 0.000000 481.500000 0.765000 ;
      RECT 470.700000 0.000000 475.520000 0.765000 ;
      RECT 464.720000 0.000000 470.000000 0.765000 ;
      RECT 459.200000 0.000000 464.020000 0.765000 ;
      RECT 453.220000 0.000000 458.500000 0.765000 ;
      RECT 447.240000 0.000000 452.520000 0.765000 ;
      RECT 441.720000 0.000000 446.540000 0.765000 ;
      RECT 435.740000 0.000000 441.020000 0.765000 ;
      RECT 430.220000 0.000000 435.040000 0.765000 ;
      RECT 424.240000 0.000000 429.520000 0.765000 ;
      RECT 418.260000 0.000000 423.540000 0.765000 ;
      RECT 412.740000 0.000000 417.560000 0.765000 ;
      RECT 406.760000 0.000000 412.040000 0.765000 ;
      RECT 400.780000 0.000000 406.060000 0.765000 ;
      RECT 395.260000 0.000000 400.080000 0.765000 ;
      RECT 389.280000 0.000000 394.560000 0.765000 ;
      RECT 383.760000 0.000000 388.580000 0.765000 ;
      RECT 377.780000 0.000000 383.060000 0.765000 ;
      RECT 371.800000 0.000000 377.080000 0.765000 ;
      RECT 366.280000 0.000000 371.100000 0.765000 ;
      RECT 360.300000 0.000000 365.580000 0.765000 ;
      RECT 354.780000 0.000000 359.600000 0.765000 ;
      RECT 348.800000 0.000000 354.080000 0.765000 ;
      RECT 342.820000 0.000000 348.100000 0.765000 ;
      RECT 337.300000 0.000000 342.120000 0.765000 ;
      RECT 331.320000 0.000000 336.600000 0.765000 ;
      RECT 325.800000 0.000000 330.620000 0.765000 ;
      RECT 319.820000 0.000000 325.100000 0.765000 ;
      RECT 313.840000 0.000000 319.120000 0.765000 ;
      RECT 308.320000 0.000000 313.140000 0.765000 ;
      RECT 302.340000 0.000000 307.620000 0.765000 ;
      RECT 296.820000 0.000000 301.640000 0.765000 ;
      RECT 290.840000 0.000000 296.120000 0.765000 ;
      RECT 284.860000 0.000000 290.140000 0.765000 ;
      RECT 279.340000 0.000000 284.160000 0.765000 ;
      RECT 273.360000 0.000000 278.640000 0.765000 ;
      RECT 267.380000 0.000000 272.660000 0.765000 ;
      RECT 261.860000 0.000000 266.680000 0.765000 ;
      RECT 255.880000 0.000000 261.160000 0.765000 ;
      RECT 250.360000 0.000000 255.180000 0.765000 ;
      RECT 244.380000 0.000000 249.660000 0.765000 ;
      RECT 238.400000 0.000000 243.680000 0.765000 ;
      RECT 232.880000 0.000000 237.700000 0.765000 ;
      RECT 226.900000 0.000000 232.180000 0.765000 ;
      RECT 221.380000 0.000000 226.200000 0.765000 ;
      RECT 215.400000 0.000000 220.680000 0.765000 ;
      RECT 209.420000 0.000000 214.700000 0.765000 ;
      RECT 203.900000 0.000000 208.720000 0.765000 ;
      RECT 197.920000 0.000000 203.200000 0.765000 ;
      RECT 192.400000 0.000000 197.220000 0.765000 ;
      RECT 186.420000 0.000000 191.700000 0.765000 ;
      RECT 180.440000 0.000000 185.720000 0.765000 ;
      RECT 174.920000 0.000000 179.740000 0.765000 ;
      RECT 168.940000 0.000000 174.220000 0.765000 ;
      RECT 163.420000 0.000000 168.240000 0.765000 ;
      RECT 157.440000 0.000000 162.720000 0.765000 ;
      RECT 151.460000 0.000000 156.740000 0.765000 ;
      RECT 145.940000 0.000000 150.760000 0.765000 ;
      RECT 139.960000 0.000000 145.240000 0.765000 ;
      RECT 133.980000 0.000000 139.260000 0.765000 ;
      RECT 128.460000 0.000000 133.280000 0.765000 ;
      RECT 122.480000 0.000000 127.760000 0.765000 ;
      RECT 116.960000 0.000000 121.780000 0.765000 ;
      RECT 110.980000 0.000000 116.260000 0.765000 ;
      RECT 105.000000 0.000000 110.280000 0.765000 ;
      RECT 99.480000 0.000000 104.300000 0.765000 ;
      RECT 93.500000 0.000000 98.780000 0.765000 ;
      RECT 87.980000 0.000000 92.800000 0.765000 ;
      RECT 82.000000 0.000000 87.280000 0.765000 ;
      RECT 76.020000 0.000000 81.300000 0.765000 ;
      RECT 70.500000 0.000000 75.320000 0.765000 ;
      RECT 64.520000 0.000000 69.800000 0.765000 ;
      RECT 59.000000 0.000000 63.820000 0.765000 ;
      RECT 53.020000 0.000000 58.300000 0.765000 ;
      RECT 47.040000 0.000000 52.320000 0.765000 ;
      RECT 41.520000 0.000000 46.340000 0.765000 ;
      RECT 35.540000 0.000000 40.820000 0.765000 ;
      RECT 30.020000 0.000000 34.840000 0.765000 ;
      RECT 24.040000 0.000000 29.320000 0.765000 ;
      RECT 18.060000 0.000000 23.340000 0.765000 ;
      RECT 12.540000 0.000000 17.360000 0.765000 ;
      RECT 6.560000 0.000000 11.840000 0.765000 ;
      RECT 1.040000 0.000000 5.860000 0.765000 ;
      RECT 0.000000 0.000000 0.340000 0.765000 ;
    LAYER met3 ;
      RECT 1.200000 3469.190000 2858.620000 3470.040000 ;
      RECT 0.000000 3404.410000 2859.820000 3469.190000 ;
      RECT 1.200000 3403.800000 2859.820000 3404.410000 ;
      RECT 1.200000 3403.310000 2858.620000 3403.800000 ;
      RECT 0.000000 3402.700000 2858.620000 3403.310000 ;
      RECT 0.000000 3339.140000 2859.820000 3402.700000 ;
      RECT 1.200000 3338.040000 2859.820000 3339.140000 ;
      RECT 0.000000 3337.310000 2859.820000 3338.040000 ;
      RECT 0.000000 3336.210000 2858.620000 3337.310000 ;
      RECT 0.000000 3273.870000 2859.820000 3336.210000 ;
      RECT 1.200000 3272.770000 2859.820000 3273.870000 ;
      RECT 0.000000 3270.210000 2859.820000 3272.770000 ;
      RECT 0.000000 3269.110000 2858.620000 3270.210000 ;
      RECT 0.000000 3207.990000 2859.820000 3269.110000 ;
      RECT 1.200000 3206.890000 2859.820000 3207.990000 ;
      RECT 0.000000 3203.720000 2859.820000 3206.890000 ;
      RECT 0.000000 3202.620000 2858.620000 3203.720000 ;
      RECT 0.000000 3142.720000 2859.820000 3202.620000 ;
      RECT 1.200000 3141.620000 2859.820000 3142.720000 ;
      RECT 0.000000 3137.230000 2859.820000 3141.620000 ;
      RECT 0.000000 3136.130000 2858.620000 3137.230000 ;
      RECT 0.000000 3077.450000 2859.820000 3136.130000 ;
      RECT 1.200000 3076.350000 2859.820000 3077.450000 ;
      RECT 0.000000 3070.130000 2859.820000 3076.350000 ;
      RECT 0.000000 3069.030000 2858.620000 3070.130000 ;
      RECT 0.000000 3011.570000 2859.820000 3069.030000 ;
      RECT 1.200000 3010.470000 2859.820000 3011.570000 ;
      RECT 0.000000 3003.640000 2859.820000 3010.470000 ;
      RECT 0.000000 3002.540000 2858.620000 3003.640000 ;
      RECT 0.000000 2946.300000 2859.820000 3002.540000 ;
      RECT 1.200000 2945.200000 2859.820000 2946.300000 ;
      RECT 0.000000 2937.150000 2859.820000 2945.200000 ;
      RECT 0.000000 2936.050000 2858.620000 2937.150000 ;
      RECT 0.000000 2881.030000 2859.820000 2936.050000 ;
      RECT 1.200000 2879.930000 2859.820000 2881.030000 ;
      RECT 0.000000 2870.050000 2859.820000 2879.930000 ;
      RECT 0.000000 2868.950000 2858.620000 2870.050000 ;
      RECT 0.000000 2815.150000 2859.820000 2868.950000 ;
      RECT 1.200000 2814.050000 2859.820000 2815.150000 ;
      RECT 0.000000 2803.560000 2859.820000 2814.050000 ;
      RECT 0.000000 2802.460000 2858.620000 2803.560000 ;
      RECT 0.000000 2749.880000 2859.820000 2802.460000 ;
      RECT 1.200000 2748.780000 2859.820000 2749.880000 ;
      RECT 0.000000 2736.460000 2859.820000 2748.780000 ;
      RECT 0.000000 2735.360000 2858.620000 2736.460000 ;
      RECT 0.000000 2684.610000 2859.820000 2735.360000 ;
      RECT 1.200000 2683.510000 2859.820000 2684.610000 ;
      RECT 0.000000 2669.970000 2859.820000 2683.510000 ;
      RECT 0.000000 2668.870000 2858.620000 2669.970000 ;
      RECT 0.000000 2619.340000 2859.820000 2668.870000 ;
      RECT 1.200000 2618.240000 2859.820000 2619.340000 ;
      RECT 0.000000 2603.480000 2859.820000 2618.240000 ;
      RECT 0.000000 2602.380000 2858.620000 2603.480000 ;
      RECT 0.000000 2553.460000 2859.820000 2602.380000 ;
      RECT 1.200000 2552.360000 2859.820000 2553.460000 ;
      RECT 0.000000 2536.380000 2859.820000 2552.360000 ;
      RECT 0.000000 2535.280000 2858.620000 2536.380000 ;
      RECT 0.000000 2488.190000 2859.820000 2535.280000 ;
      RECT 1.200000 2487.090000 2859.820000 2488.190000 ;
      RECT 0.000000 2469.890000 2859.820000 2487.090000 ;
      RECT 0.000000 2468.790000 2858.620000 2469.890000 ;
      RECT 0.000000 2422.920000 2859.820000 2468.790000 ;
      RECT 1.200000 2421.820000 2859.820000 2422.920000 ;
      RECT 0.000000 2403.400000 2859.820000 2421.820000 ;
      RECT 0.000000 2402.300000 2858.620000 2403.400000 ;
      RECT 0.000000 2357.040000 2859.820000 2402.300000 ;
      RECT 1.200000 2355.940000 2859.820000 2357.040000 ;
      RECT 0.000000 2336.300000 2859.820000 2355.940000 ;
      RECT 0.000000 2335.200000 2858.620000 2336.300000 ;
      RECT 0.000000 2291.770000 2859.820000 2335.200000 ;
      RECT 1.200000 2290.670000 2859.820000 2291.770000 ;
      RECT 0.000000 2269.810000 2859.820000 2290.670000 ;
      RECT 0.000000 2268.710000 2858.620000 2269.810000 ;
      RECT 0.000000 2226.500000 2859.820000 2268.710000 ;
      RECT 1.200000 2225.400000 2859.820000 2226.500000 ;
      RECT 0.000000 2203.320000 2859.820000 2225.400000 ;
      RECT 0.000000 2202.220000 2858.620000 2203.320000 ;
      RECT 0.000000 2160.620000 2859.820000 2202.220000 ;
      RECT 1.200000 2159.520000 2859.820000 2160.620000 ;
      RECT 0.000000 2136.220000 2859.820000 2159.520000 ;
      RECT 0.000000 2135.120000 2858.620000 2136.220000 ;
      RECT 0.000000 2095.350000 2859.820000 2135.120000 ;
      RECT 1.200000 2094.250000 2859.820000 2095.350000 ;
      RECT 0.000000 2069.730000 2859.820000 2094.250000 ;
      RECT 0.000000 2068.630000 2858.620000 2069.730000 ;
      RECT 0.000000 2030.080000 2859.820000 2068.630000 ;
      RECT 1.200000 2028.980000 2859.820000 2030.080000 ;
      RECT 0.000000 2002.630000 2859.820000 2028.980000 ;
      RECT 0.000000 2001.530000 2858.620000 2002.630000 ;
      RECT 0.000000 1964.810000 2859.820000 2001.530000 ;
      RECT 1.200000 1963.710000 2859.820000 1964.810000 ;
      RECT 0.000000 1936.140000 2859.820000 1963.710000 ;
      RECT 0.000000 1935.040000 2858.620000 1936.140000 ;
      RECT 0.000000 1898.930000 2859.820000 1935.040000 ;
      RECT 1.200000 1897.830000 2859.820000 1898.930000 ;
      RECT 0.000000 1869.650000 2859.820000 1897.830000 ;
      RECT 0.000000 1868.550000 2858.620000 1869.650000 ;
      RECT 0.000000 1833.660000 2859.820000 1868.550000 ;
      RECT 1.200000 1832.560000 2859.820000 1833.660000 ;
      RECT 0.000000 1802.550000 2859.820000 1832.560000 ;
      RECT 0.000000 1801.450000 2858.620000 1802.550000 ;
      RECT 0.000000 1768.390000 2859.820000 1801.450000 ;
      RECT 1.200000 1767.290000 2859.820000 1768.390000 ;
      RECT 0.000000 1736.060000 2859.820000 1767.290000 ;
      RECT 0.000000 1734.960000 2858.620000 1736.060000 ;
      RECT 0.000000 1702.510000 2859.820000 1734.960000 ;
      RECT 1.200000 1701.410000 2859.820000 1702.510000 ;
      RECT 0.000000 1669.570000 2859.820000 1701.410000 ;
      RECT 0.000000 1668.470000 2858.620000 1669.570000 ;
      RECT 0.000000 1637.240000 2859.820000 1668.470000 ;
      RECT 1.200000 1636.140000 2859.820000 1637.240000 ;
      RECT 0.000000 1602.470000 2859.820000 1636.140000 ;
      RECT 0.000000 1601.370000 2858.620000 1602.470000 ;
      RECT 0.000000 1571.970000 2859.820000 1601.370000 ;
      RECT 1.200000 1570.870000 2859.820000 1571.970000 ;
      RECT 0.000000 1535.980000 2859.820000 1570.870000 ;
      RECT 0.000000 1534.880000 2858.620000 1535.980000 ;
      RECT 0.000000 1506.090000 2859.820000 1534.880000 ;
      RECT 1.200000 1504.990000 2859.820000 1506.090000 ;
      RECT 0.000000 1469.490000 2859.820000 1504.990000 ;
      RECT 0.000000 1468.390000 2858.620000 1469.490000 ;
      RECT 0.000000 1440.820000 2859.820000 1468.390000 ;
      RECT 1.200000 1439.720000 2859.820000 1440.820000 ;
      RECT 0.000000 1402.390000 2859.820000 1439.720000 ;
      RECT 0.000000 1401.290000 2858.620000 1402.390000 ;
      RECT 0.000000 1375.550000 2859.820000 1401.290000 ;
      RECT 1.200000 1374.450000 2859.820000 1375.550000 ;
      RECT 0.000000 1335.900000 2859.820000 1374.450000 ;
      RECT 0.000000 1334.800000 2858.620000 1335.900000 ;
      RECT 0.000000 1310.280000 2859.820000 1334.800000 ;
      RECT 1.200000 1309.180000 2859.820000 1310.280000 ;
      RECT 0.000000 1268.800000 2859.820000 1309.180000 ;
      RECT 0.000000 1267.700000 2858.620000 1268.800000 ;
      RECT 0.000000 1244.400000 2859.820000 1267.700000 ;
      RECT 1.200000 1243.300000 2859.820000 1244.400000 ;
      RECT 0.000000 1202.310000 2859.820000 1243.300000 ;
      RECT 0.000000 1201.210000 2858.620000 1202.310000 ;
      RECT 0.000000 1179.130000 2859.820000 1201.210000 ;
      RECT 1.200000 1178.030000 2859.820000 1179.130000 ;
      RECT 0.000000 1135.820000 2859.820000 1178.030000 ;
      RECT 0.000000 1134.720000 2858.620000 1135.820000 ;
      RECT 0.000000 1113.860000 2859.820000 1134.720000 ;
      RECT 1.200000 1112.760000 2859.820000 1113.860000 ;
      RECT 0.000000 1068.720000 2859.820000 1112.760000 ;
      RECT 0.000000 1067.620000 2858.620000 1068.720000 ;
      RECT 0.000000 1047.980000 2859.820000 1067.620000 ;
      RECT 1.200000 1046.880000 2859.820000 1047.980000 ;
      RECT 0.000000 1002.230000 2859.820000 1046.880000 ;
      RECT 0.000000 1001.130000 2858.620000 1002.230000 ;
      RECT 0.000000 982.710000 2859.820000 1001.130000 ;
      RECT 1.200000 981.610000 2859.820000 982.710000 ;
      RECT 0.000000 935.740000 2859.820000 981.610000 ;
      RECT 0.000000 934.640000 2858.620000 935.740000 ;
      RECT 0.000000 917.440000 2859.820000 934.640000 ;
      RECT 1.200000 916.340000 2859.820000 917.440000 ;
      RECT 0.000000 868.640000 2859.820000 916.340000 ;
      RECT 0.000000 867.540000 2858.620000 868.640000 ;
      RECT 0.000000 851.560000 2859.820000 867.540000 ;
      RECT 1.200000 850.460000 2859.820000 851.560000 ;
      RECT 0.000000 802.150000 2859.820000 850.460000 ;
      RECT 0.000000 801.050000 2858.620000 802.150000 ;
      RECT 0.000000 786.290000 2859.820000 801.050000 ;
      RECT 1.200000 785.190000 2859.820000 786.290000 ;
      RECT 0.000000 735.660000 2859.820000 785.190000 ;
      RECT 0.000000 734.560000 2858.620000 735.660000 ;
      RECT 0.000000 721.020000 2859.820000 734.560000 ;
      RECT 1.200000 719.920000 2859.820000 721.020000 ;
      RECT 0.000000 668.560000 2859.820000 719.920000 ;
      RECT 0.000000 667.460000 2858.620000 668.560000 ;
      RECT 0.000000 655.750000 2859.820000 667.460000 ;
      RECT 1.200000 654.650000 2859.820000 655.750000 ;
      RECT 0.000000 602.070000 2859.820000 654.650000 ;
      RECT 0.000000 600.970000 2858.620000 602.070000 ;
      RECT 0.000000 589.870000 2859.820000 600.970000 ;
      RECT 1.200000 588.770000 2859.820000 589.870000 ;
      RECT 0.000000 534.970000 2859.820000 588.770000 ;
      RECT 0.000000 533.870000 2858.620000 534.970000 ;
      RECT 0.000000 524.600000 2859.820000 533.870000 ;
      RECT 1.200000 523.500000 2859.820000 524.600000 ;
      RECT 0.000000 468.480000 2859.820000 523.500000 ;
      RECT 0.000000 467.380000 2858.620000 468.480000 ;
      RECT 0.000000 459.330000 2859.820000 467.380000 ;
      RECT 1.200000 458.230000 2859.820000 459.330000 ;
      RECT 0.000000 401.990000 2859.820000 458.230000 ;
      RECT 0.000000 400.890000 2858.620000 401.990000 ;
      RECT 0.000000 393.450000 2859.820000 400.890000 ;
      RECT 1.200000 392.350000 2859.820000 393.450000 ;
      RECT 0.000000 334.890000 2859.820000 392.350000 ;
      RECT 0.000000 333.790000 2858.620000 334.890000 ;
      RECT 0.000000 328.180000 2859.820000 333.790000 ;
      RECT 1.200000 327.080000 2859.820000 328.180000 ;
      RECT 0.000000 268.400000 2859.820000 327.080000 ;
      RECT 0.000000 267.300000 2858.620000 268.400000 ;
      RECT 0.000000 262.910000 2859.820000 267.300000 ;
      RECT 1.200000 261.810000 2859.820000 262.910000 ;
      RECT 0.000000 201.910000 2859.820000 261.810000 ;
      RECT 0.000000 200.810000 2858.620000 201.910000 ;
      RECT 0.000000 197.030000 2859.820000 200.810000 ;
      RECT 1.200000 195.930000 2859.820000 197.030000 ;
      RECT 0.000000 134.810000 2859.820000 195.930000 ;
      RECT 0.000000 133.710000 2858.620000 134.810000 ;
      RECT 0.000000 131.760000 2859.820000 133.710000 ;
      RECT 1.200000 130.660000 2859.820000 131.760000 ;
      RECT 0.000000 68.320000 2859.820000 130.660000 ;
      RECT 0.000000 67.220000 2858.620000 68.320000 ;
      RECT 0.000000 66.490000 2859.820000 67.220000 ;
      RECT 1.200000 65.390000 2859.820000 66.490000 ;
      RECT 0.000000 1.220000 2859.820000 65.390000 ;
      RECT 1.200000 0.120000 2858.620000 1.220000 ;
      RECT 0.000000 0.000000 2859.820000 0.120000 ;
    LAYER met4 ;
      RECT 28.920000 3449.140000 2830.900000 3470.040000 ;
      RECT 2693.500000 3442.940000 2830.900000 3449.140000 ;
      RECT 2513.500000 3442.940000 2689.600000 3449.140000 ;
      RECT 2333.500000 3442.940000 2509.600000 3449.140000 ;
      RECT 2153.500000 3442.940000 2329.600000 3449.140000 ;
      RECT 1973.500000 3442.940000 2149.600000 3449.140000 ;
      RECT 1793.500000 3442.940000 1969.600000 3449.140000 ;
      RECT 1613.500000 3442.940000 1789.600000 3449.140000 ;
      RECT 1433.500000 3442.940000 1609.600000 3449.140000 ;
      RECT 1253.500000 3442.940000 1429.600000 3449.140000 ;
      RECT 1073.500000 3442.940000 1249.600000 3449.140000 ;
      RECT 893.500000 3442.940000 1069.600000 3449.140000 ;
      RECT 713.500000 3442.940000 889.600000 3449.140000 ;
      RECT 533.500000 3442.940000 709.600000 3449.140000 ;
      RECT 353.500000 3442.940000 529.600000 3449.140000 ;
      RECT 173.500000 3442.940000 349.600000 3449.140000 ;
      RECT 2606.600000 3142.520000 2689.600000 3442.940000 ;
      RECT 2513.500000 3142.520000 2602.700000 3442.940000 ;
      RECT 2426.600000 3142.520000 2509.600000 3442.940000 ;
      RECT 1886.600000 3142.520000 1969.600000 3442.940000 ;
      RECT 1793.500000 3142.520000 1882.700000 3442.940000 ;
      RECT 1706.600000 3142.520000 1789.600000 3442.940000 ;
      RECT 1166.600000 3142.520000 1249.600000 3442.940000 ;
      RECT 1073.500000 3142.520000 1162.700000 3442.940000 ;
      RECT 986.600000 3142.520000 1069.600000 3442.940000 ;
      RECT 446.600000 3142.520000 529.600000 3442.940000 ;
      RECT 353.500000 3142.520000 442.700000 3442.940000 ;
      RECT 266.600000 3142.520000 349.600000 3442.940000 ;
      RECT 2426.600000 2959.000000 2689.600000 3142.520000 ;
      RECT 1706.600000 2959.000000 1969.600000 3142.520000 ;
      RECT 986.600000 2959.000000 1249.600000 3142.520000 ;
      RECT 266.600000 2959.000000 529.600000 3142.520000 ;
      RECT 2606.600000 2708.520000 2689.600000 2959.000000 ;
      RECT 2513.500000 2708.520000 2602.700000 2959.000000 ;
      RECT 2426.600000 2708.520000 2509.600000 2959.000000 ;
      RECT 2246.600000 2708.520000 2329.600000 3442.940000 ;
      RECT 2153.500000 2708.520000 2242.700000 3442.940000 ;
      RECT 2066.600000 2708.520000 2149.600000 3442.940000 ;
      RECT 1886.600000 2708.520000 1969.600000 2959.000000 ;
      RECT 1793.500000 2708.520000 1882.700000 2959.000000 ;
      RECT 1706.600000 2708.520000 1789.600000 2959.000000 ;
      RECT 1166.600000 2708.520000 1249.600000 2959.000000 ;
      RECT 1073.500000 2708.520000 1162.700000 2959.000000 ;
      RECT 986.600000 2708.520000 1069.600000 2959.000000 ;
      RECT 806.600000 2708.520000 889.600000 3442.940000 ;
      RECT 713.500000 2708.520000 802.700000 3442.940000 ;
      RECT 626.600000 2708.520000 709.600000 3442.940000 ;
      RECT 446.600000 2708.520000 529.600000 2959.000000 ;
      RECT 353.500000 2708.520000 442.700000 2959.000000 ;
      RECT 266.600000 2708.520000 349.600000 2959.000000 ;
      RECT 2426.600000 2525.000000 2689.600000 2708.520000 ;
      RECT 2066.600000 2525.000000 2329.600000 2708.520000 ;
      RECT 1706.600000 2525.000000 1969.600000 2708.520000 ;
      RECT 986.600000 2525.000000 1249.600000 2708.520000 ;
      RECT 626.600000 2525.000000 889.600000 2708.520000 ;
      RECT 266.600000 2525.000000 529.600000 2708.520000 ;
      RECT 2606.600000 2274.520000 2689.600000 2525.000000 ;
      RECT 2513.500000 2274.520000 2602.700000 2525.000000 ;
      RECT 2426.600000 2274.520000 2509.600000 2525.000000 ;
      RECT 1886.600000 2274.520000 1969.600000 2525.000000 ;
      RECT 1793.500000 2274.520000 1882.700000 2525.000000 ;
      RECT 1706.600000 2274.520000 1789.600000 2525.000000 ;
      RECT 1166.600000 2274.520000 1249.600000 2525.000000 ;
      RECT 1073.500000 2274.520000 1162.700000 2525.000000 ;
      RECT 986.600000 2274.520000 1069.600000 2525.000000 ;
      RECT 446.600000 2274.520000 529.600000 2525.000000 ;
      RECT 353.500000 2274.520000 442.700000 2525.000000 ;
      RECT 266.600000 2274.520000 349.600000 2525.000000 ;
      RECT 2426.600000 2091.000000 2689.600000 2274.520000 ;
      RECT 1706.600000 2091.000000 1969.600000 2274.520000 ;
      RECT 986.600000 2091.000000 1249.600000 2274.520000 ;
      RECT 266.600000 2091.000000 529.600000 2274.520000 ;
      RECT 2246.600000 1841.520000 2329.600000 2525.000000 ;
      RECT 2153.500000 1841.520000 2242.700000 2525.000000 ;
      RECT 2066.600000 1841.520000 2149.600000 2525.000000 ;
      RECT 1526.600000 1841.520000 1609.600000 3442.940000 ;
      RECT 1433.500000 1841.520000 1522.700000 3442.940000 ;
      RECT 1346.600000 1841.520000 1429.600000 3442.940000 ;
      RECT 806.600000 1841.520000 889.600000 2525.000000 ;
      RECT 713.500000 1841.520000 802.700000 2525.000000 ;
      RECT 626.600000 1841.520000 709.600000 2525.000000 ;
      RECT 2066.600000 1658.000000 2329.600000 1841.520000 ;
      RECT 1346.600000 1658.000000 1609.600000 1841.520000 ;
      RECT 626.600000 1658.000000 889.600000 1841.520000 ;
      RECT 2606.600000 1407.520000 2689.600000 2091.000000 ;
      RECT 2513.500000 1407.520000 2602.700000 2091.000000 ;
      RECT 2426.600000 1407.520000 2509.600000 2091.000000 ;
      RECT 1886.600000 1407.520000 1969.600000 2091.000000 ;
      RECT 1793.500000 1407.520000 1882.700000 2091.000000 ;
      RECT 1706.600000 1407.520000 1789.600000 2091.000000 ;
      RECT 1166.600000 1407.520000 1249.600000 2091.000000 ;
      RECT 1073.500000 1407.520000 1162.700000 2091.000000 ;
      RECT 986.600000 1407.520000 1069.600000 2091.000000 ;
      RECT 446.600000 1407.520000 529.600000 2091.000000 ;
      RECT 353.500000 1407.520000 442.700000 2091.000000 ;
      RECT 266.600000 1407.520000 349.600000 2091.000000 ;
      RECT 2426.600000 1224.000000 2689.600000 1407.520000 ;
      RECT 1706.600000 1224.000000 1969.600000 1407.520000 ;
      RECT 986.600000 1224.000000 1249.600000 1407.520000 ;
      RECT 266.600000 1224.000000 529.600000 1407.520000 ;
      RECT 2606.600000 973.520000 2689.600000 1224.000000 ;
      RECT 2513.500000 973.520000 2602.700000 1224.000000 ;
      RECT 2426.600000 973.520000 2509.600000 1224.000000 ;
      RECT 2246.600000 973.520000 2329.600000 1658.000000 ;
      RECT 2153.500000 973.520000 2242.700000 1658.000000 ;
      RECT 2066.600000 973.520000 2149.600000 1658.000000 ;
      RECT 1886.600000 973.520000 1969.600000 1224.000000 ;
      RECT 1793.500000 973.520000 1882.700000 1224.000000 ;
      RECT 1706.600000 973.520000 1789.600000 1224.000000 ;
      RECT 1166.600000 973.520000 1249.600000 1224.000000 ;
      RECT 1073.500000 973.520000 1162.700000 1224.000000 ;
      RECT 986.600000 973.520000 1069.600000 1224.000000 ;
      RECT 806.600000 973.520000 889.600000 1658.000000 ;
      RECT 713.500000 973.520000 802.700000 1658.000000 ;
      RECT 626.600000 973.520000 709.600000 1658.000000 ;
      RECT 446.600000 973.520000 529.600000 1224.000000 ;
      RECT 353.500000 973.520000 442.700000 1224.000000 ;
      RECT 266.600000 973.520000 349.600000 1224.000000 ;
      RECT 2426.600000 790.000000 2689.600000 973.520000 ;
      RECT 2066.600000 790.000000 2329.600000 973.520000 ;
      RECT 1706.600000 790.000000 1969.600000 973.520000 ;
      RECT 986.600000 790.000000 1249.600000 973.520000 ;
      RECT 626.600000 790.000000 889.600000 973.520000 ;
      RECT 266.600000 790.000000 529.600000 973.520000 ;
      RECT 2606.600000 539.520000 2689.600000 790.000000 ;
      RECT 2513.500000 539.520000 2602.700000 790.000000 ;
      RECT 2426.600000 539.520000 2509.600000 790.000000 ;
      RECT 1886.600000 539.520000 1969.600000 790.000000 ;
      RECT 1793.500000 539.520000 1882.700000 790.000000 ;
      RECT 1706.600000 539.520000 1789.600000 790.000000 ;
      RECT 1166.600000 539.520000 1249.600000 790.000000 ;
      RECT 1073.500000 539.520000 1162.700000 790.000000 ;
      RECT 986.600000 539.520000 1069.600000 790.000000 ;
      RECT 446.600000 539.520000 529.600000 790.000000 ;
      RECT 353.500000 539.520000 442.700000 790.000000 ;
      RECT 266.600000 539.520000 349.600000 790.000000 ;
      RECT 2426.600000 356.000000 2689.600000 539.520000 ;
      RECT 1706.600000 356.000000 1969.600000 539.520000 ;
      RECT 986.600000 356.000000 1249.600000 539.520000 ;
      RECT 266.600000 356.000000 529.600000 539.520000 ;
      RECT 2786.600000 25.060000 2830.900000 3442.940000 ;
      RECT 2693.500000 25.060000 2782.700000 3442.940000 ;
      RECT 2606.600000 25.060000 2689.600000 356.000000 ;
      RECT 2513.500000 25.060000 2602.700000 356.000000 ;
      RECT 2426.600000 25.060000 2509.600000 356.000000 ;
      RECT 2333.500000 25.060000 2422.700000 3442.940000 ;
      RECT 2246.600000 25.060000 2329.600000 790.000000 ;
      RECT 2153.500000 25.060000 2242.700000 790.000000 ;
      RECT 2066.600000 25.060000 2149.600000 790.000000 ;
      RECT 1973.500000 25.060000 2062.700000 3442.940000 ;
      RECT 1886.600000 25.060000 1969.600000 356.000000 ;
      RECT 1793.500000 25.060000 1882.700000 356.000000 ;
      RECT 1706.600000 25.060000 1789.600000 356.000000 ;
      RECT 1613.500000 25.060000 1702.700000 3442.940000 ;
      RECT 1526.600000 25.060000 1609.600000 1658.000000 ;
      RECT 1433.500000 25.060000 1522.700000 1658.000000 ;
      RECT 1346.600000 25.060000 1429.600000 1658.000000 ;
      RECT 1253.500000 25.060000 1342.700000 3442.940000 ;
      RECT 1166.600000 25.060000 1249.600000 356.000000 ;
      RECT 1073.500000 25.060000 1162.700000 356.000000 ;
      RECT 986.600000 25.060000 1069.600000 356.000000 ;
      RECT 893.500000 25.060000 982.700000 3442.940000 ;
      RECT 806.600000 25.060000 889.600000 790.000000 ;
      RECT 713.500000 25.060000 802.700000 790.000000 ;
      RECT 626.600000 25.060000 709.600000 790.000000 ;
      RECT 533.500000 25.060000 622.700000 3442.940000 ;
      RECT 446.600000 25.060000 529.600000 356.000000 ;
      RECT 353.500000 25.060000 442.700000 356.000000 ;
      RECT 266.600000 25.060000 349.600000 356.000000 ;
      RECT 173.500000 25.060000 262.700000 3442.940000 ;
      RECT 2693.500000 18.860000 2830.900000 25.060000 ;
      RECT 2513.500000 18.860000 2689.600000 25.060000 ;
      RECT 2333.500000 18.860000 2509.600000 25.060000 ;
      RECT 2153.500000 18.860000 2329.600000 25.060000 ;
      RECT 1973.500000 18.860000 2149.600000 25.060000 ;
      RECT 1793.500000 18.860000 1969.600000 25.060000 ;
      RECT 1613.500000 18.860000 1789.600000 25.060000 ;
      RECT 1433.500000 18.860000 1609.600000 25.060000 ;
      RECT 1253.500000 18.860000 1429.600000 25.060000 ;
      RECT 1073.500000 18.860000 1249.600000 25.060000 ;
      RECT 893.500000 18.860000 1069.600000 25.060000 ;
      RECT 713.500000 18.860000 889.600000 25.060000 ;
      RECT 533.500000 18.860000 709.600000 25.060000 ;
      RECT 353.500000 18.860000 529.600000 25.060000 ;
      RECT 173.500000 18.860000 349.600000 25.060000 ;
      RECT 28.920000 18.860000 169.600000 3449.140000 ;
      RECT 2841.000000 0.000000 2859.820000 3470.040000 ;
      RECT 2834.800000 0.000000 2837.100000 3470.040000 ;
      RECT 28.920000 0.000000 2830.900000 18.860000 ;
      RECT 22.720000 0.000000 25.020000 3470.040000 ;
      RECT 0.000000 0.000000 18.820000 3470.040000 ;
 END
END user_proj_example

END LIBRARY
